VERSION 5.8 ;
BUSBITCHARS "[]" ;
DIVIDERCHAR "/" ;
CLEARANCEMEASURE EUCLIDEAN ;

SITE coresite
    SIZE 0.0450 BY 0.1440 ;
    CLASS CORE ;
    SYMMETRY X Y ;
END coresite

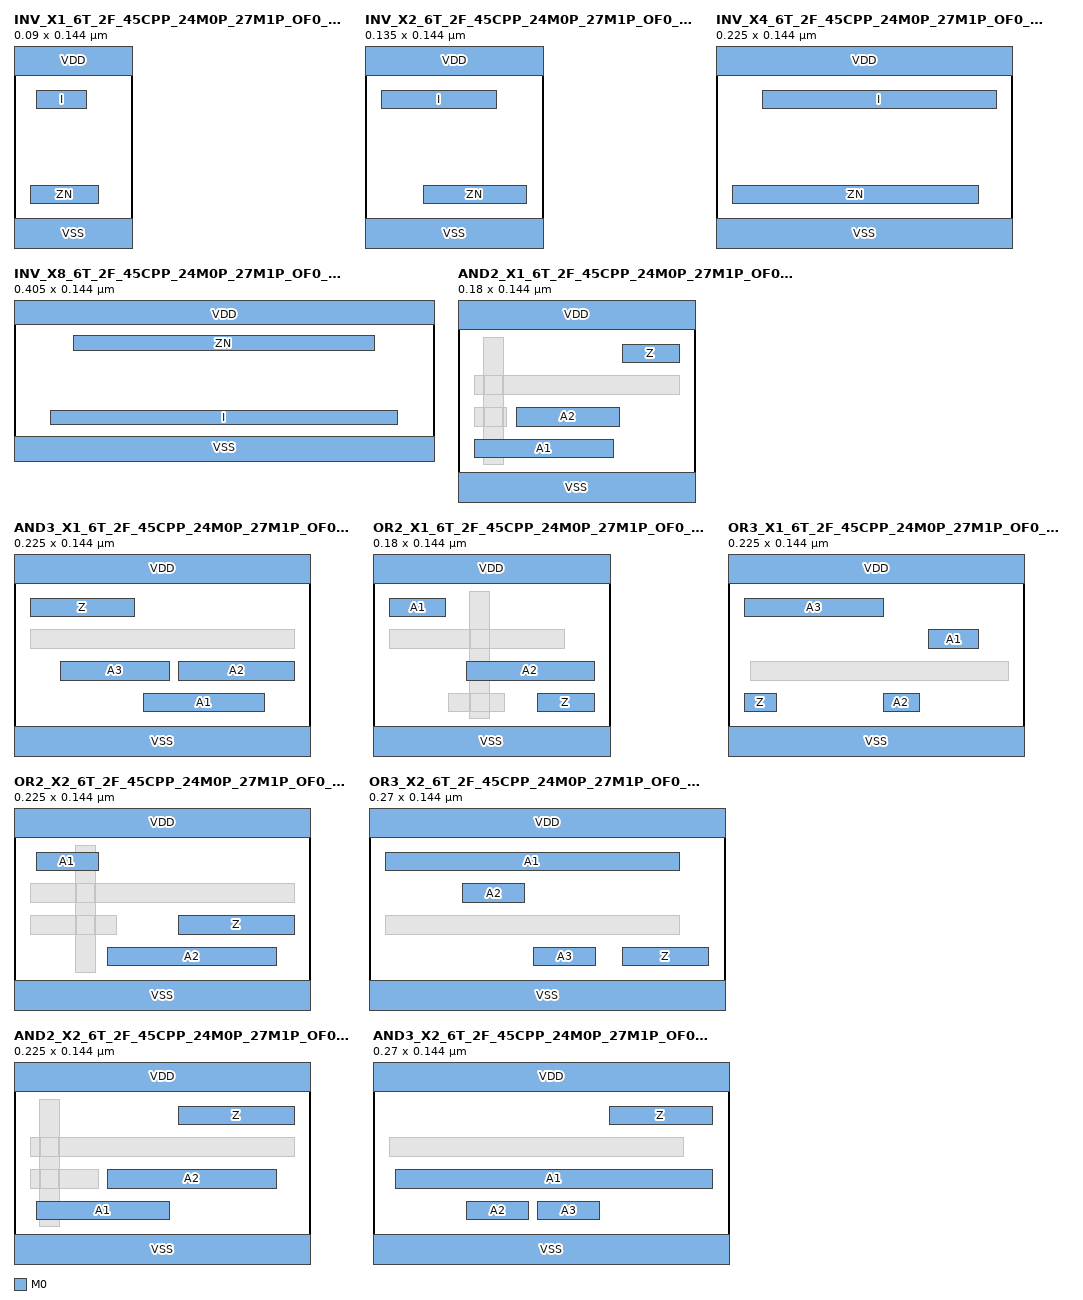
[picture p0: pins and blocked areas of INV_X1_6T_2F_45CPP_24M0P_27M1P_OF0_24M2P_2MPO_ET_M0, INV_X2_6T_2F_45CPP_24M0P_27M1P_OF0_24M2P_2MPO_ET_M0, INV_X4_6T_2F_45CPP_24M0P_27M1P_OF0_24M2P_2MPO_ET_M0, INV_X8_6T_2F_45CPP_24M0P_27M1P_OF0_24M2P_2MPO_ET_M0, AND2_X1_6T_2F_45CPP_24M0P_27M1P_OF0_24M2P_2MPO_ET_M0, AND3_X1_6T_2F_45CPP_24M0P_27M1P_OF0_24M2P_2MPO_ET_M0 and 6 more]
MACRO INV_X1_6T_2F_45CPP_24M0P_27M1P_OF0_24M2P_2MPO_ET_M0
  CLASS CORE ;
  ORIGIN 0 0 ;
  FOREIGN INV_X1_6T_2F_45CPP_24M0P_27M1P_OF0_24M2P_2MPO_ET_M0 0 0 ;
  SIZE 0.0900 BY 0.1440 ;
  SYMMETRY X Y ;
  SITE coresite ;
  PIN I
    DIRECTION INPUT ;
    USE SIGNAL ;
    PORT
      LAYER M0 ;
        RECT 0.0170 0.1150 0.0550 0.1010 ;
    END
  END I
  PIN ZN
    DIRECTION OUTPUT ;
    USE SIGNAL ;
    PORT
      LAYER M0 ;
        RECT 0.0125 0.0430 0.0640 0.0290 ;
    END
  END ZN
  PIN VDD
    DIRECTION INOUT ;
    USE POWER ;
    SHAPE ABUTMENT ;
    PORT
      LAYER M0 ;
        RECT 0.0000 0.1260 0.0900 0.1620 ;
    END
  END VDD
  PIN VSS
    DIRECTION INOUT ;
    USE GROUND ;
    SHAPE ABUTMENT ;
    PORT
      LAYER M0 ;
        RECT 0.0000 -0.0180 0.0900 0.0180 ;
    END
  END VSS
END INV_X1_6T_2F_45CPP_24M0P_27M1P_OF0_24M2P_2MPO_ET_M0

MACRO INV_X2_6T_2F_45CPP_24M0P_27M1P_OF0_24M2P_2MPO_ET_M0
  CLASS CORE ;
  ORIGIN 0 0 ;
  FOREIGN INV_X2_6T_2F_45CPP_24M0P_27M1P_OF0_24M2P_2MPO_ET_M0 0 0 ;
  SIZE 0.1350 BY 0.1440 ;
  SYMMETRY X Y ;
  SITE coresite ;
  PIN I
    DIRECTION INPUT ;
    USE SIGNAL ;
    PORT
      LAYER M0 ;
        RECT 0.0125 0.1150 0.1000 0.1010 ;
    END
  END I
  PIN ZN
    DIRECTION OUTPUT ;
    USE SIGNAL ;
    PORT
      LAYER M0 ;
        RECT 0.0440 0.0430 0.1225 0.0290 ;
    END
  END ZN
  PIN VDD
    DIRECTION INOUT ;
    USE POWER ;
    SHAPE ABUTMENT ;
    PORT
      LAYER M0 ;
        RECT 0.0000 0.1260 0.1350 0.1620 ;
    END
  END VDD
  PIN VSS
    DIRECTION INOUT ;
    USE GROUND ;
    SHAPE ABUTMENT ;
    PORT
      LAYER M0 ;
        RECT 0.0000 -0.0180 0.1350 0.0180 ;
    END
  END VSS
END INV_X2_6T_2F_45CPP_24M0P_27M1P_OF0_24M2P_2MPO_ET_M0

MACRO INV_X4_6T_2F_45CPP_24M0P_27M1P_OF0_24M2P_2MPO_ET_M0
  CLASS CORE ;
  ORIGIN 0 0 ;
  FOREIGN INV_X4_6T_2F_45CPP_24M0P_27M1P_OF0_24M2P_2MPO_ET_M0 0 0 ;
  SIZE 0.2250 BY 0.1440 ;
  SYMMETRY X Y ;
  SITE coresite ;
  PIN I
    DIRECTION INPUT ;
    USE SIGNAL ;
    PORT
      LAYER M0 ;
        RECT 0.0350 0.1150 0.2125 0.1010 ;
    END
  END I
  PIN ZN
    DIRECTION OUTPUT ;
    USE SIGNAL ;
    PORT
      LAYER M0 ;
        RECT 0.0125 0.0430 0.1990 0.0290 ;
    END
  END ZN
  PIN VDD
    DIRECTION INOUT ;
    USE POWER ;
    SHAPE ABUTMENT ;
    PORT
      LAYER M0 ;
        RECT 0.0000 0.1260 0.2250 0.1620 ;
    END
  END VDD
  PIN VSS
    DIRECTION INOUT ;
    USE GROUND ;
    SHAPE ABUTMENT ;
    PORT
      LAYER M0 ;
        RECT 0.0000 -0.0180 0.2250 0.0180 ;
    END
  END VSS
END INV_X4_6T_2F_45CPP_24M0P_27M1P_OF0_24M2P_2MPO_ET_M0

MACRO INV_X8_6T_2F_45CPP_24M0P_27M1P_OF0_24M2P_2MPO_ET_M0
  CLASS CORE ;
  ORIGIN 0 0 ;
  FOREIGN INV_X8_6T_2F_45CPP_24M0P_27M1P_OF0_24M2P_2MPO_ET_M0 0 0 ;
  SIZE 0.4050 BY 0.1440 ;
  SYMMETRY X Y ;
  SITE coresite ;
  PIN ZN
    DIRECTION OUTPUT ;
    USE SIGNAL ;
    PORT
      LAYER M0 ;
        RECT 0.0575 0.1150 0.3475 0.1010 ;
    END
  END ZN
  PIN I
    DIRECTION INPUT ;
    USE SIGNAL ;
    PORT
      LAYER M0 ;
        RECT 0.0350 0.0430 0.3700 0.0290 ;
    END
  END I
  PIN VDD
    DIRECTION INOUT ;
    USE POWER ;
    SHAPE ABUTMENT ;
    PORT
      LAYER M0 ;
        RECT 0.0000 0.1260 0.4050 0.1620 ;
    END
  END VDD
  PIN VSS
    DIRECTION INOUT ;
    USE GROUND ;
    SHAPE ABUTMENT ;
    PORT
      LAYER M0 ;
        RECT 0.0000 -0.0180 0.4050 0.0180 ;
    END
  END VSS
END INV_X8_6T_2F_45CPP_24M0P_27M1P_OF0_24M2P_2MPO_ET_M0

MACRO AND2_X1_6T_2F_45CPP_24M0P_27M1P_OF0_24M2P_2MPO_ET_M0
  CLASS CORE ;
  ORIGIN 0 0 ;
  FOREIGN AND2_X1_6T_2F_45CPP_24M0P_27M1P_OF0_24M2P_2MPO_ET_M0 0 0 ;
  SIZE 0.1800 BY 0.1440 ;
  SYMMETRY X Y ;
  SITE coresite ;
  PIN A2
    DIRECTION INPUT ;
    USE SIGNAL ;
    PORT
      LAYER M0 ;
        RECT 0.0440 0.0670 0.1225 0.0530 ;
    END
  END A2
  PIN A1
    DIRECTION INPUT ;
    USE SIGNAL ;
    PORT
      LAYER M0 ;
        RECT 0.0125 0.0430 0.1180 0.0290 ;
    END
  END A1
  PIN Z
    DIRECTION OUTPUT ;
    USE SIGNAL ;
    PORT
      LAYER M0 ;
        RECT 0.1250 0.1150 0.1675 0.1010 ;
    END
  END Z
  PIN VDD
    DIRECTION INOUT ;
    USE POWER ;
    SHAPE ABUTMENT ;
    PORT
      LAYER M0 ;
        RECT 0.0000 0.1260 0.1800 0.1620 ;
    END
  END VDD
  PIN VSS
    DIRECTION INOUT ;
    USE GROUND ;
    SHAPE ABUTMENT ;
    PORT
      LAYER M0 ;
        RECT 0.0000 -0.0180 0.1800 0.0180 ;
    END
  END VSS
  OBS
      LAYER M0 ;
        RECT 0.0125 0.0770 0.1675 0.0910 ;
        RECT 0.0125 0.0530 0.0370 0.0670 ;
      LAYER M1 ;
        RECT 0.0195 0.1200 0.0345 0.0240 ;
      LAYER V0 ;
        RECT 0.0200 0.0530 0.0340 0.0670 ;
        RECT 0.0200 0.0770 0.0340 0.0910 ;
  END
END AND2_X1_6T_2F_45CPP_24M0P_27M1P_OF0_24M2P_2MPO_ET_M0

MACRO AND3_X1_6T_2F_45CPP_24M0P_27M1P_OF0_24M2P_2MPO_ET_M0
  CLASS CORE ;
  ORIGIN 0 0 ;
  FOREIGN AND3_X1_6T_2F_45CPP_24M0P_27M1P_OF0_24M2P_2MPO_ET_M0 0 0 ;
  SIZE 0.2250 BY 0.1440 ;
  SYMMETRY X Y ;
  SITE coresite ;
  PIN A3
    DIRECTION INPUT ;
    USE SIGNAL ;
    PORT
      LAYER M0 ;
        RECT 0.0350 0.0670 0.1180 0.0530 ;
    END
  END A3
  PIN A2
    DIRECTION INPUT ;
    USE SIGNAL ;
    PORT
      LAYER M0 ;
        RECT 0.1250 0.0670 0.2125 0.0530 ;
    END
  END A2
  PIN Z
    DIRECTION OUTPUT ;
    USE SIGNAL ;
    PORT
      LAYER M0 ;
        RECT 0.0125 0.1150 0.0910 0.1010 ;
    END
  END Z
  PIN A1
    DIRECTION INPUT ;
    USE SIGNAL ;
    PORT
      LAYER M0 ;
        RECT 0.0980 0.0430 0.1900 0.0290 ;
    END
  END A1
  PIN VDD
    DIRECTION INOUT ;
    USE POWER ;
    SHAPE ABUTMENT ;
    PORT
      LAYER M0 ;
        RECT 0.0000 0.1260 0.2250 0.1620 ;
    END
  END VDD
  PIN VSS
    DIRECTION INOUT ;
    USE GROUND ;
    SHAPE ABUTMENT ;
    PORT
      LAYER M0 ;
        RECT 0.0000 -0.0180 0.2250 0.0180 ;
    END
  END VSS
  OBS
      LAYER M0 ;
        RECT 0.0125 0.0770 0.2125 0.0910 ;
  END
END AND3_X1_6T_2F_45CPP_24M0P_27M1P_OF0_24M2P_2MPO_ET_M0

MACRO OR2_X1_6T_2F_45CPP_24M0P_27M1P_OF0_24M2P_2MPO_ET_M0
  CLASS CORE ;
  ORIGIN 0 0 ;
  FOREIGN OR2_X1_6T_2F_45CPP_24M0P_27M1P_OF0_24M2P_2MPO_ET_M0 0 0 ;
  SIZE 0.1800 BY 0.1440 ;
  SYMMETRY X Y ;
  SITE coresite ;
  PIN A1
    DIRECTION INPUT ;
    USE SIGNAL ;
    PORT
      LAYER M0 ;
        RECT 0.0125 0.1150 0.0550 0.1010 ;
    END
  END A1
  PIN A2
    DIRECTION INPUT ;
    USE SIGNAL ;
    PORT
      LAYER M0 ;
        RECT 0.0710 0.0670 0.1675 0.0530 ;
    END
  END A2
  PIN Z
    DIRECTION OUTPUT ;
    USE SIGNAL ;
    PORT
      LAYER M0 ;
        RECT 0.1250 0.0430 0.1675 0.0290 ;
    END
  END Z
  PIN VDD
    DIRECTION INOUT ;
    USE POWER ;
    SHAPE ABUTMENT ;
    PORT
      LAYER M0 ;
        RECT 0.0000 0.1260 0.1800 0.1620 ;
    END
  END VDD
  PIN VSS
    DIRECTION INOUT ;
    USE GROUND ;
    SHAPE ABUTMENT ;
    PORT
      LAYER M0 ;
        RECT 0.0000 -0.0180 0.1800 0.0180 ;
    END
  END VSS
  OBS
      LAYER M0 ;
        RECT 0.0125 0.0770 0.1450 0.0910 ;
        RECT 0.0575 0.0290 0.1000 0.0430 ;
      LAYER M1 ;
        RECT 0.0735 0.1200 0.0885 0.0240 ;
      LAYER V0 ;
        RECT 0.0740 0.0290 0.0880 0.0430 ;
        RECT 0.0740 0.0770 0.0880 0.0910 ;
  END
END OR2_X1_6T_2F_45CPP_24M0P_27M1P_OF0_24M2P_2MPO_ET_M0

MACRO OR3_X1_6T_2F_45CPP_24M0P_27M1P_OF0_24M2P_2MPO_ET_M0
  CLASS CORE ;
  ORIGIN 0 0 ;
  FOREIGN OR3_X1_6T_2F_45CPP_24M0P_27M1P_OF0_24M2P_2MPO_ET_M0 0 0 ;
  SIZE 0.2250 BY 0.1440 ;
  SYMMETRY X Y ;
  SITE coresite ;
  PIN A3
    DIRECTION INPUT ;
    USE SIGNAL ;
    PORT
      LAYER M0 ;
        RECT 0.0125 0.1150 0.1180 0.1010 ;
    END
  END A3
  PIN A2
    DIRECTION INPUT ;
    USE SIGNAL ;
    PORT
      LAYER M0 ;
        RECT 0.1175 0.0430 0.1450 0.0290 ;
    END
  END A2
  PIN A1
    DIRECTION INPUT ;
    USE SIGNAL ;
    PORT
      LAYER M0 ;
        RECT 0.1520 0.0910 0.1900 0.0770 ;
    END
  END A1
  PIN Z
    DIRECTION OUTPUT ;
    USE SIGNAL ;
    PORT
      LAYER M0 ;
        RECT 0.0125 0.0430 0.0370 0.0290 ;
    END
  END Z
  PIN VDD
    DIRECTION INOUT ;
    USE POWER ;
    SHAPE ABUTMENT ;
    PORT
      LAYER M0 ;
        RECT 0.0000 0.1260 0.2250 0.1620 ;
    END
  END VDD
  PIN VSS
    DIRECTION INOUT ;
    USE GROUND ;
    SHAPE ABUTMENT ;
    PORT
      LAYER M0 ;
        RECT 0.0000 -0.0180 0.2250 0.0180 ;
    END
  END VSS
  OBS
      LAYER M0 ;
        RECT 0.0170 0.0530 0.2125 0.0670 ;
  END
END OR3_X1_6T_2F_45CPP_24M0P_27M1P_OF0_24M2P_2MPO_ET_M0

MACRO OR2_X2_6T_2F_45CPP_24M0P_27M1P_OF0_24M2P_2MPO_ET_M0
  CLASS CORE ;
  ORIGIN 0 0 ;
  FOREIGN OR2_X2_6T_2F_45CPP_24M0P_27M1P_OF0_24M2P_2MPO_ET_M0 0 0 ;
  SIZE 0.2250 BY 0.1440 ;
  SYMMETRY X Y ;
  SITE coresite ;
  PIN Z
    DIRECTION OUTPUT ;
    USE SIGNAL ;
    PORT
      LAYER M0 ;
        RECT 0.1250 0.0670 0.2125 0.0530 ;
    END
  END Z
  PIN A1
    DIRECTION INPUT ;
    USE SIGNAL ;
    PORT
      LAYER M0 ;
        RECT 0.0170 0.1150 0.0640 0.1010 ;
    END
  END A1
  PIN A2
    DIRECTION INPUT ;
    USE SIGNAL ;
    PORT
      LAYER M0 ;
        RECT 0.0710 0.0430 0.1990 0.0290 ;
    END
  END A2
  PIN VDD
    DIRECTION INOUT ;
    USE POWER ;
    SHAPE ABUTMENT ;
    PORT
      LAYER M0 ;
        RECT 0.0000 0.1260 0.2250 0.1620 ;
    END
  END VDD
  PIN VSS
    DIRECTION INOUT ;
    USE GROUND ;
    SHAPE ABUTMENT ;
    PORT
      LAYER M0 ;
        RECT 0.0000 -0.0180 0.2250 0.0180 ;
    END
  END VSS
  OBS
      LAYER M0 ;
        RECT 0.0125 0.0770 0.2125 0.0910 ;
        RECT 0.0125 0.0530 0.0775 0.0670 ;
      LAYER M1 ;
        RECT 0.0465 0.1200 0.0615 0.0240 ;
      LAYER V0 ;
        RECT 0.0470 0.0530 0.0610 0.0670 ;
        RECT 0.0470 0.0770 0.0610 0.0910 ;
  END
END OR2_X2_6T_2F_45CPP_24M0P_27M1P_OF0_24M2P_2MPO_ET_M0

MACRO OR3_X2_6T_2F_45CPP_24M0P_27M1P_OF0_24M2P_2MPO_ET_M0
  CLASS CORE ;
  ORIGIN 0 0 ;
  FOREIGN OR3_X2_6T_2F_45CPP_24M0P_27M1P_OF0_24M2P_2MPO_ET_M0 0 0 ;
  SIZE 0.2700 BY 0.1440 ;
  SYMMETRY X Y ;
  SITE coresite ;
  PIN A1
    DIRECTION INPUT ;
    USE SIGNAL ;
    PORT
      LAYER M0 ;
        RECT 0.0125 0.1150 0.2350 0.1010 ;
    END
  END A1
  PIN A2
    DIRECTION INPUT ;
    USE SIGNAL ;
    PORT
      LAYER M0 ;
        RECT 0.0710 0.0910 0.1180 0.0770 ;
    END
  END A2
  PIN A3
    DIRECTION INPUT ;
    USE SIGNAL ;
    PORT
      LAYER M0 ;
        RECT 0.1250 0.0430 0.1720 0.0290 ;
    END
  END A3
  PIN Z
    DIRECTION OUTPUT ;
    USE SIGNAL ;
    PORT
      LAYER M0 ;
        RECT 0.1925 0.0430 0.2575 0.0290 ;
    END
  END Z
  PIN VDD
    DIRECTION INOUT ;
    USE POWER ;
    SHAPE ABUTMENT ;
    PORT
      LAYER M0 ;
        RECT 0.0000 0.1260 0.2700 0.1620 ;
    END
  END VDD
  PIN VSS
    DIRECTION INOUT ;
    USE GROUND ;
    SHAPE ABUTMENT ;
    PORT
      LAYER M0 ;
        RECT 0.0000 -0.0180 0.2700 0.0180 ;
    END
  END VSS
  OBS
      LAYER M0 ;
        RECT 0.0125 0.0530 0.2350 0.0670 ;
  END
END OR3_X2_6T_2F_45CPP_24M0P_27M1P_OF0_24M2P_2MPO_ET_M0

MACRO AND2_X2_6T_2F_45CPP_24M0P_27M1P_OF0_24M2P_2MPO_ET_M0
  CLASS CORE ;
  ORIGIN 0 0 ;
  FOREIGN AND2_X2_6T_2F_45CPP_24M0P_27M1P_OF0_24M2P_2MPO_ET_M0 0 0 ;
  SIZE 0.2250 BY 0.1440 ;
  SYMMETRY X Y ;
  SITE coresite ;
  PIN A2
    DIRECTION INPUT ;
    USE SIGNAL ;
    PORT
      LAYER M0 ;
        RECT 0.0710 0.0670 0.1990 0.0530 ;
    END
  END A2
  PIN A1
    DIRECTION INPUT ;
    USE SIGNAL ;
    PORT
      LAYER M0 ;
        RECT 0.0170 0.0430 0.1180 0.0290 ;
    END
  END A1
  PIN Z
    DIRECTION OUTPUT ;
    USE SIGNAL ;
    PORT
      LAYER M0 ;
        RECT 0.1250 0.1150 0.2125 0.1010 ;
    END
  END Z
  PIN VDD
    DIRECTION INOUT ;
    USE POWER ;
    SHAPE ABUTMENT ;
    PORT
      LAYER M0 ;
        RECT 0.0000 0.1260 0.2250 0.1620 ;
    END
  END VDD
  PIN VSS
    DIRECTION INOUT ;
    USE GROUND ;
    SHAPE ABUTMENT ;
    PORT
      LAYER M0 ;
        RECT 0.0000 -0.0180 0.2250 0.0180 ;
    END
  END VSS
  OBS
      LAYER M0 ;
        RECT 0.0125 0.0770 0.2125 0.0910 ;
        RECT 0.0125 0.0530 0.0640 0.0670 ;
      LAYER M1 ;
        RECT 0.0195 0.1200 0.0345 0.0240 ;
      LAYER V0 ;
        RECT 0.0200 0.0530 0.0340 0.0670 ;
        RECT 0.0200 0.0770 0.0340 0.0910 ;
  END
END AND2_X2_6T_2F_45CPP_24M0P_27M1P_OF0_24M2P_2MPO_ET_M0

MACRO AND3_X2_6T_2F_45CPP_24M0P_27M1P_OF0_24M2P_2MPO_ET_M0
  CLASS CORE ;
  ORIGIN 0 0 ;
  FOREIGN AND3_X2_6T_2F_45CPP_24M0P_27M1P_OF0_24M2P_2MPO_ET_M0 0 0 ;
  SIZE 0.2700 BY 0.1440 ;
  SYMMETRY X Y ;
  SITE coresite ;
  PIN A1
    DIRECTION INPUT ;
    USE SIGNAL ;
    PORT
      LAYER M0 ;
        RECT 0.0170 0.0670 0.2575 0.0530 ;
    END
  END A1
  PIN A2
    DIRECTION INPUT ;
    USE SIGNAL ;
    PORT
      LAYER M0 ;
        RECT 0.0710 0.0430 0.1180 0.0290 ;
    END
  END A2
  PIN A3
    DIRECTION INPUT ;
    USE SIGNAL ;
    PORT
      LAYER M0 ;
        RECT 0.1250 0.0430 0.1720 0.0290 ;
    END
  END A3
  PIN Z
    DIRECTION OUTPUT ;
    USE SIGNAL ;
    PORT
      LAYER M0 ;
        RECT 0.1790 0.1150 0.2575 0.1010 ;
    END
  END Z
  PIN VDD
    DIRECTION INOUT ;
    USE POWER ;
    SHAPE ABUTMENT ;
    PORT
      LAYER M0 ;
        RECT 0.0000 0.1260 0.2700 0.1620 ;
    END
  END VDD
  PIN VSS
    DIRECTION INOUT ;
    USE GROUND ;
    SHAPE ABUTMENT ;
    PORT
      LAYER M0 ;
        RECT 0.0000 -0.0180 0.2700 0.0180 ;
    END
  END VSS
  OBS
      LAYER M0 ;
        RECT 0.0125 0.0770 0.2350 0.0910 ;
  END
END AND3_X2_6T_2F_45CPP_24M0P_27M1P_OF0_24M2P_2MPO_ET_M0

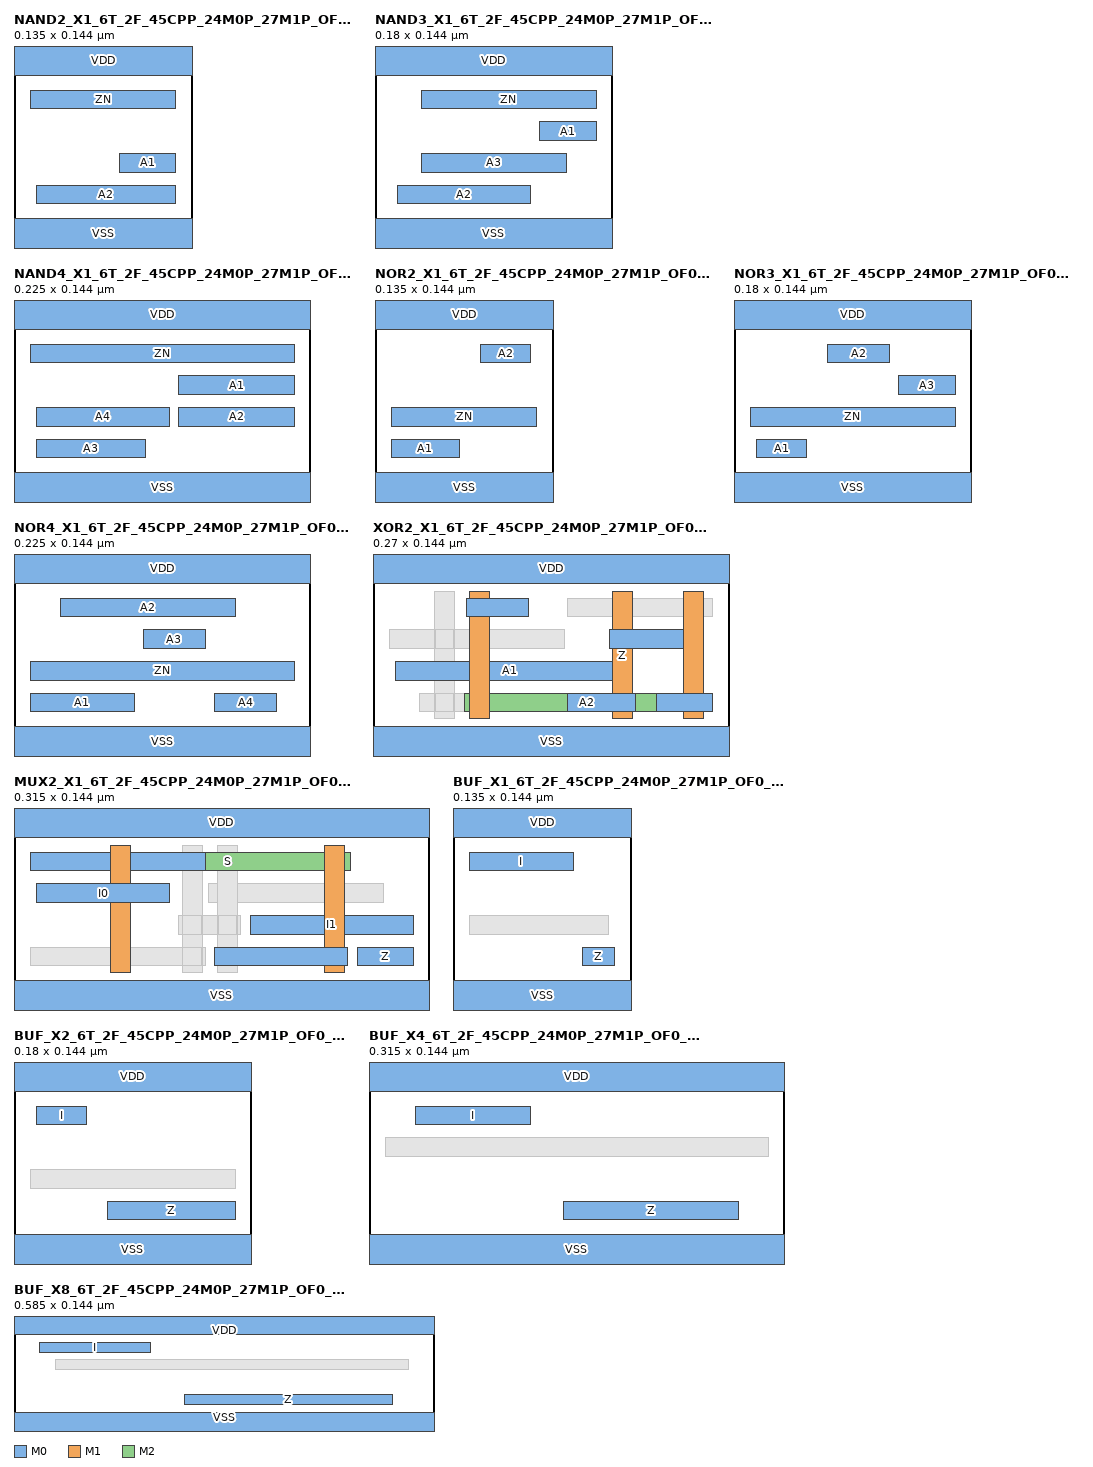
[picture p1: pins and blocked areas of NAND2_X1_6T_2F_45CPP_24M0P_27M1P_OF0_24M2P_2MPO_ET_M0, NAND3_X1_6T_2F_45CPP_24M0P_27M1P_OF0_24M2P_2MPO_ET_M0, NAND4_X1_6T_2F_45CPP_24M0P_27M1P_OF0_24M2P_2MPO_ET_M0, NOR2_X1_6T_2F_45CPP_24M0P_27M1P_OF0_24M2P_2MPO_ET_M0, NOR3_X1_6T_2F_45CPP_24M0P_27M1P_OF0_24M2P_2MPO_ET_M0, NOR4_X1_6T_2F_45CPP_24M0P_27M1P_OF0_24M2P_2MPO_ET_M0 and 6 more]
MACRO NAND2_X1_6T_2F_45CPP_24M0P_27M1P_OF0_24M2P_2MPO_ET_M0
  CLASS CORE ;
  ORIGIN 0 0 ;
  FOREIGN NAND2_X1_6T_2F_45CPP_24M0P_27M1P_OF0_24M2P_2MPO_ET_M0 0 0 ;
  SIZE 0.1350 BY 0.1440 ;
  SYMMETRY X Y ;
  SITE coresite ;
  PIN ZN
    DIRECTION OUTPUT ;
    USE SIGNAL ;
    PORT
      LAYER M0 ;
        RECT 0.0125 0.1150 0.1225 0.1010 ;
    END
  END ZN
  PIN A1
    DIRECTION INPUT ;
    USE SIGNAL ;
    PORT
      LAYER M0 ;
        RECT 0.0800 0.0670 0.1225 0.0530 ;
    END
  END A1
  PIN A2
    DIRECTION INPUT ;
    USE SIGNAL ;
    PORT
      LAYER M0 ;
        RECT 0.0170 0.0430 0.1225 0.0290 ;
    END
  END A2
  PIN VDD
    DIRECTION INOUT ;
    USE POWER ;
    SHAPE ABUTMENT ;
    PORT
      LAYER M0 ;
        RECT 0.0000 0.1260 0.1350 0.1620 ;
    END
  END VDD
  PIN VSS
    DIRECTION INOUT ;
    USE GROUND ;
    SHAPE ABUTMENT ;
    PORT
      LAYER M0 ;
        RECT 0.0000 -0.0180 0.1350 0.0180 ;
    END
  END VSS
END NAND2_X1_6T_2F_45CPP_24M0P_27M1P_OF0_24M2P_2MPO_ET_M0

MACRO NAND3_X1_6T_2F_45CPP_24M0P_27M1P_OF0_24M2P_2MPO_ET_M0
  CLASS CORE ;
  ORIGIN 0 0 ;
  FOREIGN NAND3_X1_6T_2F_45CPP_24M0P_27M1P_OF0_24M2P_2MPO_ET_M0 0 0 ;
  SIZE 0.1800 BY 0.1440 ;
  SYMMETRY X Y ;
  SITE coresite ;
  PIN ZN
    DIRECTION OUTPUT ;
    USE SIGNAL ;
    PORT
      LAYER M0 ;
        RECT 0.0350 0.1150 0.1675 0.1010 ;
    END
  END ZN
  PIN A3
    DIRECTION INPUT ;
    USE SIGNAL ;
    PORT
      LAYER M0 ;
        RECT 0.0350 0.0670 0.1450 0.0530 ;
    END
  END A3
  PIN A2
    DIRECTION INPUT ;
    USE SIGNAL ;
    PORT
      LAYER M0 ;
        RECT 0.0170 0.0430 0.1180 0.0290 ;
    END
  END A2
  PIN A1
    DIRECTION INPUT ;
    USE SIGNAL ;
    PORT
      LAYER M0 ;
        RECT 0.1250 0.0910 0.1675 0.0770 ;
    END
  END A1
  PIN VDD
    DIRECTION INOUT ;
    USE POWER ;
    SHAPE ABUTMENT ;
    PORT
      LAYER M0 ;
        RECT 0.0000 0.1260 0.1800 0.1620 ;
    END
  END VDD
  PIN VSS
    DIRECTION INOUT ;
    USE GROUND ;
    SHAPE ABUTMENT ;
    PORT
      LAYER M0 ;
        RECT 0.0000 -0.0180 0.1800 0.0180 ;
    END
  END VSS
END NAND3_X1_6T_2F_45CPP_24M0P_27M1P_OF0_24M2P_2MPO_ET_M0

MACRO NAND4_X1_6T_2F_45CPP_24M0P_27M1P_OF0_24M2P_2MPO_ET_M0
  CLASS CORE ;
  ORIGIN 0 0 ;
  FOREIGN NAND4_X1_6T_2F_45CPP_24M0P_27M1P_OF0_24M2P_2MPO_ET_M0 0 0 ;
  SIZE 0.2250 BY 0.1440 ;
  SYMMETRY X Y ;
  SITE coresite ;
  PIN ZN
    DIRECTION OUTPUT ;
    USE SIGNAL ;
    PORT
      LAYER M0 ;
        RECT 0.0125 0.1150 0.2125 0.1010 ;
    END
  END ZN
  PIN A4
    DIRECTION INPUT ;
    USE SIGNAL ;
    PORT
      LAYER M0 ;
        RECT 0.0170 0.0670 0.1180 0.0530 ;
    END
  END A4
  PIN A2
    DIRECTION INPUT ;
    USE SIGNAL ;
    PORT
      LAYER M0 ;
        RECT 0.1250 0.0670 0.2125 0.0530 ;
    END
  END A2
  PIN A3
    DIRECTION INPUT ;
    USE SIGNAL ;
    PORT
      LAYER M0 ;
        RECT 0.0170 0.0430 0.1000 0.0290 ;
    END
  END A3
  PIN A1
    DIRECTION INPUT ;
    USE SIGNAL ;
    PORT
      LAYER M0 ;
        RECT 0.1250 0.0910 0.2125 0.0770 ;
    END
  END A1
  PIN VDD
    DIRECTION INOUT ;
    USE POWER ;
    SHAPE ABUTMENT ;
    PORT
      LAYER M0 ;
        RECT 0.0000 0.1260 0.2250 0.1620 ;
    END
  END VDD
  PIN VSS
    DIRECTION INOUT ;
    USE GROUND ;
    SHAPE ABUTMENT ;
    PORT
      LAYER M0 ;
        RECT 0.0000 -0.0180 0.2250 0.0180 ;
    END
  END VSS
END NAND4_X1_6T_2F_45CPP_24M0P_27M1P_OF0_24M2P_2MPO_ET_M0

MACRO NOR2_X1_6T_2F_45CPP_24M0P_27M1P_OF0_24M2P_2MPO_ET_M0
  CLASS CORE ;
  ORIGIN 0 0 ;
  FOREIGN NOR2_X1_6T_2F_45CPP_24M0P_27M1P_OF0_24M2P_2MPO_ET_M0 0 0 ;
  SIZE 0.1350 BY 0.1440 ;
  SYMMETRY X Y ;
  SITE coresite ;
  PIN ZN
    DIRECTION OUTPUT ;
    USE SIGNAL ;
    PORT
      LAYER M0 ;
        RECT 0.0125 0.0670 0.1225 0.0530 ;
    END
  END ZN
  PIN A1
    DIRECTION INPUT ;
    USE SIGNAL ;
    PORT
      LAYER M0 ;
        RECT 0.0125 0.0430 0.0640 0.0290 ;
    END
  END A1
  PIN A2
    DIRECTION INPUT ;
    USE SIGNAL ;
    PORT
      LAYER M0 ;
        RECT 0.0800 0.1150 0.1180 0.1010 ;
    END
  END A2
  PIN VDD
    DIRECTION INOUT ;
    USE POWER ;
    SHAPE ABUTMENT ;
    PORT
      LAYER M0 ;
        RECT 0.0000 0.1260 0.1350 0.1620 ;
    END
  END VDD
  PIN VSS
    DIRECTION INOUT ;
    USE GROUND ;
    SHAPE ABUTMENT ;
    PORT
      LAYER M0 ;
        RECT 0.0000 -0.0180 0.1350 0.0180 ;
    END
  END VSS
END NOR2_X1_6T_2F_45CPP_24M0P_27M1P_OF0_24M2P_2MPO_ET_M0

MACRO NOR3_X1_6T_2F_45CPP_24M0P_27M1P_OF0_24M2P_2MPO_ET_M0
  CLASS CORE ;
  ORIGIN 0 0 ;
  FOREIGN NOR3_X1_6T_2F_45CPP_24M0P_27M1P_OF0_24M2P_2MPO_ET_M0 0 0 ;
  SIZE 0.1800 BY 0.1440 ;
  SYMMETRY X Y ;
  SITE coresite ;
  PIN ZN
    DIRECTION OUTPUT ;
    USE SIGNAL ;
    PORT
      LAYER M0 ;
        RECT 0.0125 0.0670 0.1675 0.0530 ;
    END
  END ZN
  PIN A1
    DIRECTION INPUT ;
    USE SIGNAL ;
    PORT
      LAYER M0 ;
        RECT 0.0170 0.0430 0.0550 0.0290 ;
    END
  END A1
  PIN A2
    DIRECTION INPUT ;
    USE SIGNAL ;
    PORT
      LAYER M0 ;
        RECT 0.0710 0.1150 0.1180 0.1010 ;
    END
  END A2
  PIN A3
    DIRECTION INPUT ;
    USE SIGNAL ;
    PORT
      LAYER M0 ;
        RECT 0.1250 0.0910 0.1675 0.0770 ;
    END
  END A3
  PIN VDD
    DIRECTION INOUT ;
    USE POWER ;
    SHAPE ABUTMENT ;
    PORT
      LAYER M0 ;
        RECT 0.0000 0.1260 0.1800 0.1620 ;
    END
  END VDD
  PIN VSS
    DIRECTION INOUT ;
    USE GROUND ;
    SHAPE ABUTMENT ;
    PORT
      LAYER M0 ;
        RECT 0.0000 -0.0180 0.1800 0.0180 ;
    END
  END VSS
END NOR3_X1_6T_2F_45CPP_24M0P_27M1P_OF0_24M2P_2MPO_ET_M0

MACRO NOR4_X1_6T_2F_45CPP_24M0P_27M1P_OF0_24M2P_2MPO_ET_M0
  CLASS CORE ;
  ORIGIN 0 0 ;
  FOREIGN NOR4_X1_6T_2F_45CPP_24M0P_27M1P_OF0_24M2P_2MPO_ET_M0 0 0 ;
  SIZE 0.2250 BY 0.1440 ;
  SYMMETRY X Y ;
  SITE coresite ;
  PIN A2
    DIRECTION INPUT ;
    USE SIGNAL ;
    PORT
      LAYER M0 ;
        RECT 0.0350 0.1150 0.1675 0.1010 ;
    END
  END A2
  PIN ZN
    DIRECTION OUTPUT ;
    USE SIGNAL ;
    PORT
      LAYER M0 ;
        RECT 0.0125 0.0670 0.2125 0.0530 ;
    END
  END ZN
  PIN A1
    DIRECTION INPUT ;
    USE SIGNAL ;
    PORT
      LAYER M0 ;
        RECT 0.0125 0.0430 0.0910 0.0290 ;
    END
  END A1
  PIN A3
    DIRECTION INPUT ;
    USE SIGNAL ;
    PORT
      LAYER M0 ;
        RECT 0.0980 0.0910 0.1450 0.0770 ;
    END
  END A3
  PIN A4
    DIRECTION INPUT ;
    USE SIGNAL ;
    PORT
      LAYER M0 ;
        RECT 0.1520 0.0430 0.1990 0.0290 ;
    END
  END A4
  PIN VDD
    DIRECTION INOUT ;
    USE POWER ;
    SHAPE ABUTMENT ;
    PORT
      LAYER M0 ;
        RECT 0.0000 0.1260 0.2250 0.1620 ;
    END
  END VDD
  PIN VSS
    DIRECTION INOUT ;
    USE GROUND ;
    SHAPE ABUTMENT ;
    PORT
      LAYER M0 ;
        RECT 0.0000 -0.0180 0.2250 0.0180 ;
    END
  END VSS
END NOR4_X1_6T_2F_45CPP_24M0P_27M1P_OF0_24M2P_2MPO_ET_M0

MACRO XOR2_X1_6T_2F_45CPP_24M0P_27M1P_OF0_24M2P_2MPO_ET_M0
  CLASS CORE ;
  ORIGIN 0 0 ;
  FOREIGN XOR2_X1_6T_2F_45CPP_24M0P_27M1P_OF0_24M2P_2MPO_ET_M0 0 0 ;
  SIZE 0.2700 BY 0.1440 ;
  SYMMETRY X Y ;
  SITE coresite ;
  PIN Z
    DIRECTION OUTPUT ;
    USE SIGNAL ;
    PORT
      LAYER M1 ;
        RECT 0.1815 0.1200 0.1965 0.0240 ;
      LAYER M0 ;
        RECT 0.1790 0.0910 0.2350 0.0770 ;
        RECT 0.1475 0.0430 0.1990 0.0290 ;
    END
  END Z
  PIN A2
    DIRECTION INPUT ;
    USE SIGNAL ;
    PORT
      LAYER M2 ;
        RECT 0.0690 0.0430 0.2550 0.0290 ;
      LAYER M1 ;
        RECT 0.0735 0.1200 0.0885 0.0240 ;
        RECT 0.2355 0.1200 0.2505 0.0240 ;
      LAYER M0 ;
        RECT 0.0710 0.1150 0.1180 0.1010 ;
        RECT 0.2150 0.0430 0.2575 0.0290 ;
    END
  END A2
  PIN A1
    DIRECTION INPUT ;
    USE SIGNAL ;
    PORT
      LAYER M0 ;
        RECT 0.0170 0.0670 0.1900 0.0530 ;
    END
  END A1
  PIN VDD
    DIRECTION INOUT ;
    USE POWER ;
    SHAPE ABUTMENT ;
    PORT
      LAYER M0 ;
        RECT 0.0000 0.1260 0.2700 0.1620 ;
    END
  END VDD
  PIN VSS
    DIRECTION INOUT ;
    USE GROUND ;
    SHAPE ABUTMENT ;
    PORT
      LAYER M0 ;
        RECT 0.0000 -0.0180 0.2700 0.0180 ;
    END
  END VSS
  OBS
      LAYER V1 ;
        RECT 0.2360 0.0290 0.2500 0.0430 ;
        RECT 0.0740 0.0290 0.0880 0.0430 ;
      LAYER M0 ;
        RECT 0.1475 0.1010 0.2575 0.1150 ;
        RECT 0.0125 0.0770 0.1450 0.0910 ;
        RECT 0.0350 0.0290 0.0775 0.0430 ;
      LAYER M1 ;
        RECT 0.0465 0.1200 0.0615 0.0240 ;
      LAYER V0 ;
        RECT 0.0470 0.0290 0.0610 0.0430 ;
        RECT 0.1820 0.0290 0.1960 0.0430 ;
        RECT 0.2360 0.0290 0.2500 0.0430 ;
        RECT 0.0470 0.0770 0.0610 0.0910 ;
        RECT 0.1820 0.0770 0.1960 0.0910 ;
        RECT 0.0740 0.1010 0.0880 0.1150 ;
  END
END XOR2_X1_6T_2F_45CPP_24M0P_27M1P_OF0_24M2P_2MPO_ET_M0

MACRO MUX2_X1_6T_2F_45CPP_24M0P_27M1P_OF0_24M2P_2MPO_ET_M0
  CLASS CORE ;
  ORIGIN 0 0 ;
  FOREIGN MUX2_X1_6T_2F_45CPP_24M0P_27M1P_OF0_24M2P_2MPO_ET_M0 0 0 ;
  SIZE 0.3150 BY 0.1440 ;
  SYMMETRY X Y ;
  SITE coresite ;
  PIN S
    DIRECTION INPUT ;
    USE SIGNAL ;
    PORT
      LAYER M2 ;
        RECT 0.0690 0.1150 0.2550 0.1010 ;
      LAYER M1 ;
        RECT 0.0735 0.1200 0.0885 0.0240 ;
        RECT 0.2355 0.1200 0.2505 0.0240 ;
      LAYER M0 ;
        RECT 0.0125 0.1150 0.1450 0.1010 ;
        RECT 0.1520 0.0430 0.2530 0.0290 ;
    END
  END S
  PIN I0
    DIRECTION INPUT ;
    USE SIGNAL ;
    PORT
      LAYER M0 ;
        RECT 0.0170 0.0910 0.1180 0.0770 ;
    END
  END I0
  PIN I1
    DIRECTION INPUT ;
    USE SIGNAL ;
    PORT
      LAYER M0 ;
        RECT 0.1790 0.0670 0.3025 0.0530 ;
    END
  END I1
  PIN Z
    DIRECTION OUTPUT ;
    USE SIGNAL ;
    PORT
      LAYER M0 ;
        RECT 0.2600 0.0430 0.3025 0.0290 ;
    END
  END Z
  PIN VDD
    DIRECTION INOUT ;
    USE POWER ;
    SHAPE ABUTMENT ;
    PORT
      LAYER M0 ;
        RECT 0.0000 0.1260 0.3150 0.1620 ;
    END
  END VDD
  PIN VSS
    DIRECTION INOUT ;
    USE GROUND ;
    SHAPE ABUTMENT ;
    PORT
      LAYER M0 ;
        RECT 0.0000 -0.0180 0.3150 0.0180 ;
    END
  END VSS
  OBS
      LAYER V1 ;
        RECT 0.2360 0.1010 0.2500 0.1150 ;
        RECT 0.0740 0.1010 0.0880 0.1150 ;
      LAYER M0 ;
        RECT 0.1520 0.1010 0.2125 0.1150 ;
        RECT 0.1475 0.0770 0.2800 0.0910 ;
        RECT 0.1250 0.0530 0.1720 0.0670 ;
        RECT 0.0125 0.0290 0.1450 0.0430 ;
      LAYER M1 ;
        RECT 0.1275 0.1200 0.1425 0.0240 ;
        RECT 0.1545 0.1200 0.1695 0.0240 ;
      LAYER V0 ;
        RECT 0.1280 0.0290 0.1420 0.0430 ;
        RECT 0.2360 0.0290 0.2500 0.0430 ;
        RECT 0.1280 0.0530 0.1420 0.0670 ;
        RECT 0.1550 0.0530 0.1690 0.0670 ;
        RECT 0.0740 0.1010 0.0880 0.1150 ;
        RECT 0.1550 0.1010 0.1690 0.1150 ;
  END
END MUX2_X1_6T_2F_45CPP_24M0P_27M1P_OF0_24M2P_2MPO_ET_M0

MACRO BUF_X1_6T_2F_45CPP_24M0P_27M1P_OF0_24M2P_2MPO_ET_M0
  CLASS CORE ;
  ORIGIN 0 0 ;
  FOREIGN BUF_X1_6T_2F_45CPP_24M0P_27M1P_OF0_24M2P_2MPO_ET_M0 0 0 ;
  SIZE 0.1350 BY 0.1440 ;
  SYMMETRY X Y ;
  SITE coresite ;
  PIN I
    DIRECTION INPUT ;
    USE SIGNAL ;
    PORT
      LAYER M0 ;
        RECT 0.0125 0.1150 0.0910 0.1010 ;
    END
  END I
  PIN Z
    DIRECTION OUTPUT ;
    USE SIGNAL ;
    PORT
      LAYER M0 ;
        RECT 0.0980 0.0430 0.1225 0.0290 ;
    END
  END Z
  PIN VDD
    DIRECTION INOUT ;
    USE POWER ;
    SHAPE ABUTMENT ;
    PORT
      LAYER M0 ;
        RECT 0.0000 0.1260 0.1350 0.1620 ;
    END
  END VDD
  PIN VSS
    DIRECTION INOUT ;
    USE GROUND ;
    SHAPE ABUTMENT ;
    PORT
      LAYER M0 ;
        RECT 0.0000 -0.0180 0.1350 0.0180 ;
    END
  END VSS
  OBS
      LAYER M0 ;
        RECT 0.0125 0.0530 0.1180 0.0670 ;
  END
END BUF_X1_6T_2F_45CPP_24M0P_27M1P_OF0_24M2P_2MPO_ET_M0

MACRO BUF_X2_6T_2F_45CPP_24M0P_27M1P_OF0_24M2P_2MPO_ET_M0
  CLASS CORE ;
  ORIGIN 0 0 ;
  FOREIGN BUF_X2_6T_2F_45CPP_24M0P_27M1P_OF0_24M2P_2MPO_ET_M0 0 0 ;
  SIZE 0.1800 BY 0.1440 ;
  SYMMETRY X Y ;
  SITE coresite ;
  PIN I
    DIRECTION INPUT ;
    USE SIGNAL ;
    PORT
      LAYER M0 ;
        RECT 0.0170 0.1150 0.0550 0.1010 ;
    END
  END I
  PIN Z
    DIRECTION OUTPUT ;
    USE SIGNAL ;
    PORT
      LAYER M0 ;
        RECT 0.0710 0.0430 0.1675 0.0290 ;
    END
  END Z
  PIN VDD
    DIRECTION INOUT ;
    USE POWER ;
    SHAPE ABUTMENT ;
    PORT
      LAYER M0 ;
        RECT 0.0000 0.1260 0.1800 0.1620 ;
    END
  END VDD
  PIN VSS
    DIRECTION INOUT ;
    USE GROUND ;
    SHAPE ABUTMENT ;
    PORT
      LAYER M0 ;
        RECT 0.0000 -0.0180 0.1800 0.0180 ;
    END
  END VSS
  OBS
      LAYER M0 ;
        RECT 0.0125 0.0530 0.1675 0.0670 ;
  END
END BUF_X2_6T_2F_45CPP_24M0P_27M1P_OF0_24M2P_2MPO_ET_M0

MACRO BUF_X4_6T_2F_45CPP_24M0P_27M1P_OF0_24M2P_2MPO_ET_M0
  CLASS CORE ;
  ORIGIN 0 0 ;
  FOREIGN BUF_X4_6T_2F_45CPP_24M0P_27M1P_OF0_24M2P_2MPO_ET_M0 0 0 ;
  SIZE 0.3150 BY 0.1440 ;
  SYMMETRY X Y ;
  SITE coresite ;
  PIN I
    DIRECTION INPUT ;
    USE SIGNAL ;
    PORT
      LAYER M0 ;
        RECT 0.0350 0.1150 0.1225 0.1010 ;
    END
  END I
  PIN Z
    DIRECTION OUTPUT ;
    USE SIGNAL ;
    PORT
      LAYER M0 ;
        RECT 0.1475 0.0430 0.2800 0.0290 ;
    END
  END Z
  PIN VDD
    DIRECTION INOUT ;
    USE POWER ;
    SHAPE ABUTMENT ;
    PORT
      LAYER M0 ;
        RECT 0.0000 0.1260 0.3150 0.1620 ;
    END
  END VDD
  PIN VSS
    DIRECTION INOUT ;
    USE GROUND ;
    SHAPE ABUTMENT ;
    PORT
      LAYER M0 ;
        RECT 0.0000 -0.0180 0.3150 0.0180 ;
    END
  END VSS
  OBS
      LAYER M0 ;
        RECT 0.0125 0.0770 0.3025 0.0910 ;
  END
END BUF_X4_6T_2F_45CPP_24M0P_27M1P_OF0_24M2P_2MPO_ET_M0

MACRO BUF_X8_6T_2F_45CPP_24M0P_27M1P_OF0_24M2P_2MPO_ET_M0
  CLASS CORE ;
  ORIGIN 0 0 ;
  FOREIGN BUF_X8_6T_2F_45CPP_24M0P_27M1P_OF0_24M2P_2MPO_ET_M0 0 0 ;
  SIZE 0.5850 BY 0.1440 ;
  SYMMETRY X Y ;
  SITE coresite ;
  PIN I
    DIRECTION INPUT ;
    USE SIGNAL ;
    PORT
      LAYER M0 ;
        RECT 0.0350 0.1150 0.1900 0.1010 ;
    END
  END I
  PIN Z
    DIRECTION OUTPUT ;
    USE SIGNAL ;
    PORT
      LAYER M0 ;
        RECT 0.2375 0.0430 0.5275 0.0290 ;
    END
  END Z
  PIN VDD
    DIRECTION INOUT ;
    USE POWER ;
    SHAPE ABUTMENT ;
    PORT
      LAYER M0 ;
        RECT 0.0000 0.1260 0.5850 0.1620 ;
    END
  END VDD
  PIN VSS
    DIRECTION INOUT ;
    USE GROUND ;
    SHAPE ABUTMENT ;
    PORT
      LAYER M0 ;
        RECT 0.0000 -0.0180 0.5850 0.0180 ;
    END
  END VSS
  OBS
      LAYER M0 ;
        RECT 0.0575 0.0770 0.5500 0.0910 ;
  END
END BUF_X8_6T_2F_45CPP_24M0P_27M1P_OF0_24M2P_2MPO_ET_M0

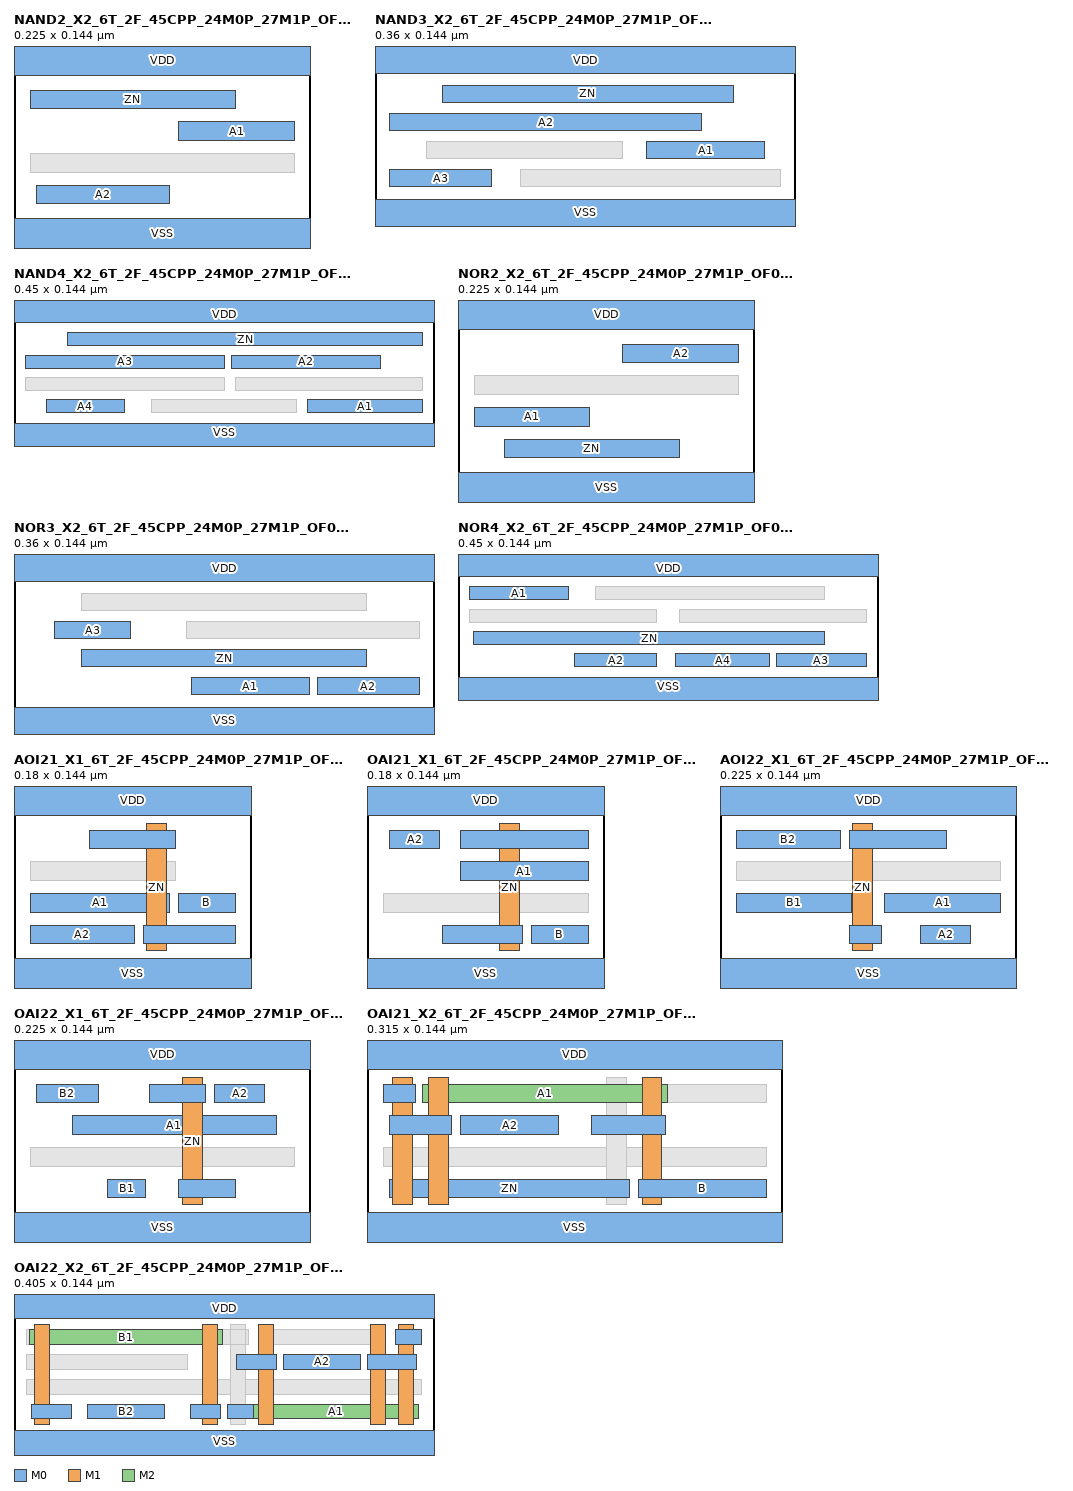
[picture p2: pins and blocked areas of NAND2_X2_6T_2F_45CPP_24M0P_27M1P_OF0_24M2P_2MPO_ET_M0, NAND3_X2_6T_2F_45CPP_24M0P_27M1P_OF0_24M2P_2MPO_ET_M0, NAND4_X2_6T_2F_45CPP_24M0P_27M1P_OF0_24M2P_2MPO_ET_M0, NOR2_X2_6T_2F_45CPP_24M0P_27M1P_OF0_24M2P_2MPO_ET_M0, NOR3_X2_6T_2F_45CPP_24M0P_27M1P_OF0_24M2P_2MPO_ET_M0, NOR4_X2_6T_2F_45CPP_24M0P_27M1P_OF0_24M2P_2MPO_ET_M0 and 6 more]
MACRO NAND2_X2_6T_2F_45CPP_24M0P_27M1P_OF0_24M2P_2MPO_ET_M0
  CLASS CORE ;
  ORIGIN 0 0 ;
  FOREIGN NAND2_X2_6T_2F_45CPP_24M0P_27M1P_OF0_24M2P_2MPO_ET_M0 0 0 ;
  SIZE 0.2250 BY 0.1440 ;
  SYMMETRY X Y ;
  SITE coresite ;
  PIN ZN
    DIRECTION OUTPUT ;
    USE SIGNAL ;
    PORT
      LAYER M0 ;
        RECT 0.0125 0.1150 0.1675 0.1010 ;
    END
  END ZN
  PIN A2
    DIRECTION INPUT ;
    USE SIGNAL ;
    PORT
      LAYER M0 ;
        RECT 0.0170 0.0430 0.1180 0.0290 ;
    END
  END A2
  PIN A1
    DIRECTION INPUT ;
    USE SIGNAL ;
    PORT
      LAYER M0 ;
        RECT 0.1250 0.0910 0.2125 0.0770 ;
    END
  END A1
  PIN VDD
    DIRECTION INOUT ;
    USE POWER ;
    SHAPE ABUTMENT ;
    PORT
      LAYER M0 ;
        RECT 0.0000 0.1260 0.2250 0.1620 ;
    END
  END VDD
  PIN VSS
    DIRECTION INOUT ;
    USE GROUND ;
    SHAPE ABUTMENT ;
    PORT
      LAYER M0 ;
        RECT 0.0000 -0.0180 0.2250 0.0180 ;
    END
  END VSS
  OBS
      LAYER M0 ;
        RECT 0.0125 0.0530 0.2125 0.0670 ;
  END
END NAND2_X2_6T_2F_45CPP_24M0P_27M1P_OF0_24M2P_2MPO_ET_M0

MACRO NAND3_X2_6T_2F_45CPP_24M0P_27M1P_OF0_24M2P_2MPO_ET_M0
  CLASS CORE ;
  ORIGIN 0 0 ;
  FOREIGN NAND3_X2_6T_2F_45CPP_24M0P_27M1P_OF0_24M2P_2MPO_ET_M0 0 0 ;
  SIZE 0.3600 BY 0.1440 ;
  SYMMETRY X Y ;
  SITE coresite ;
  PIN ZN
    DIRECTION OUTPUT ;
    USE SIGNAL ;
    PORT
      LAYER M0 ;
        RECT 0.0575 0.1150 0.3070 0.1010 ;
    END
  END ZN
  PIN A2
    DIRECTION INPUT ;
    USE SIGNAL ;
    PORT
      LAYER M0 ;
        RECT 0.0125 0.0910 0.2800 0.0770 ;
    END
  END A2
  PIN A1
    DIRECTION INPUT ;
    USE SIGNAL ;
    PORT
      LAYER M0 ;
        RECT 0.2330 0.0670 0.3340 0.0530 ;
    END
  END A1
  PIN A3
    DIRECTION INPUT ;
    USE SIGNAL ;
    PORT
      LAYER M0 ;
        RECT 0.0125 0.0430 0.1000 0.0290 ;
    END
  END A3
  PIN VDD
    DIRECTION INOUT ;
    USE POWER ;
    SHAPE ABUTMENT ;
    PORT
      LAYER M0 ;
        RECT 0.0000 0.1260 0.3600 0.1620 ;
    END
  END VDD
  PIN VSS
    DIRECTION INOUT ;
    USE GROUND ;
    SHAPE ABUTMENT ;
    PORT
      LAYER M0 ;
        RECT 0.0000 -0.0180 0.3600 0.0180 ;
    END
  END VSS
  OBS
      LAYER M0 ;
        RECT 0.0440 0.0530 0.2125 0.0670 ;
        RECT 0.1250 0.0290 0.3475 0.0430 ;
  END
END NAND3_X2_6T_2F_45CPP_24M0P_27M1P_OF0_24M2P_2MPO_ET_M0

MACRO NAND4_X2_6T_2F_45CPP_24M0P_27M1P_OF0_24M2P_2MPO_ET_M0
  CLASS CORE ;
  ORIGIN 0 0 ;
  FOREIGN NAND4_X2_6T_2F_45CPP_24M0P_27M1P_OF0_24M2P_2MPO_ET_M0 0 0 ;
  SIZE 0.4500 BY 0.1440 ;
  SYMMETRY X Y ;
  SITE coresite ;
  PIN ZN
    DIRECTION OUTPUT ;
    USE SIGNAL ;
    PORT
      LAYER M0 ;
        RECT 0.0575 0.1150 0.4375 0.1010 ;
    END
  END ZN
  PIN A3
    DIRECTION INPUT ;
    USE SIGNAL ;
    PORT
      LAYER M0 ;
        RECT 0.0125 0.0910 0.2260 0.0770 ;
    END
  END A3
  PIN A2
    DIRECTION INPUT ;
    USE SIGNAL ;
    PORT
      LAYER M0 ;
        RECT 0.2330 0.0910 0.3925 0.0770 ;
    END
  END A2
  PIN A4
    DIRECTION INPUT ;
    USE SIGNAL ;
    PORT
      LAYER M0 ;
        RECT 0.0350 0.0430 0.1180 0.0290 ;
    END
  END A4
  PIN A1
    DIRECTION INPUT ;
    USE SIGNAL ;
    PORT
      LAYER M0 ;
        RECT 0.3140 0.0430 0.4375 0.0290 ;
    END
  END A1
  PIN VDD
    DIRECTION INOUT ;
    USE POWER ;
    SHAPE ABUTMENT ;
    PORT
      LAYER M0 ;
        RECT 0.0000 0.1260 0.4500 0.1620 ;
    END
  END VDD
  PIN VSS
    DIRECTION INOUT ;
    USE GROUND ;
    SHAPE ABUTMENT ;
    PORT
      LAYER M0 ;
        RECT 0.0000 -0.0180 0.4500 0.0180 ;
    END
  END VSS
  OBS
      LAYER M0 ;
        RECT 0.0125 0.0530 0.2260 0.0670 ;
        RECT 0.2375 0.0530 0.4375 0.0670 ;
        RECT 0.1475 0.0290 0.3025 0.0430 ;
  END
END NAND4_X2_6T_2F_45CPP_24M0P_27M1P_OF0_24M2P_2MPO_ET_M0

MACRO NOR2_X2_6T_2F_45CPP_24M0P_27M1P_OF0_24M2P_2MPO_ET_M0
  CLASS CORE ;
  ORIGIN 0 0 ;
  FOREIGN NOR2_X2_6T_2F_45CPP_24M0P_27M1P_OF0_24M2P_2MPO_ET_M0 0 0 ;
  SIZE 0.2250 BY 0.1440 ;
  SYMMETRY X Y ;
  SITE coresite ;
  PIN A1
    DIRECTION INPUT ;
    USE SIGNAL ;
    PORT
      LAYER M0 ;
        RECT 0.0125 0.0670 0.1000 0.0530 ;
    END
  END A1
  PIN A2
    DIRECTION INPUT ;
    USE SIGNAL ;
    PORT
      LAYER M0 ;
        RECT 0.1250 0.1150 0.2125 0.1010 ;
    END
  END A2
  PIN ZN
    DIRECTION OUTPUT ;
    USE SIGNAL ;
    PORT
      LAYER M0 ;
        RECT 0.0350 0.0430 0.1675 0.0290 ;
    END
  END ZN
  PIN VDD
    DIRECTION INOUT ;
    USE POWER ;
    SHAPE ABUTMENT ;
    PORT
      LAYER M0 ;
        RECT 0.0000 0.1260 0.2250 0.1620 ;
    END
  END VDD
  PIN VSS
    DIRECTION INOUT ;
    USE GROUND ;
    SHAPE ABUTMENT ;
    PORT
      LAYER M0 ;
        RECT 0.0000 -0.0180 0.2250 0.0180 ;
    END
  END VSS
  OBS
      LAYER M0 ;
        RECT 0.0125 0.0770 0.2125 0.0910 ;
  END
END NOR2_X2_6T_2F_45CPP_24M0P_27M1P_OF0_24M2P_2MPO_ET_M0

MACRO NOR3_X2_6T_2F_45CPP_24M0P_27M1P_OF0_24M2P_2MPO_ET_M0
  CLASS CORE ;
  ORIGIN 0 0 ;
  FOREIGN NOR3_X2_6T_2F_45CPP_24M0P_27M1P_OF0_24M2P_2MPO_ET_M0 0 0 ;
  SIZE 0.3600 BY 0.1440 ;
  SYMMETRY X Y ;
  SITE coresite ;
  PIN ZN
    DIRECTION OUTPUT ;
    USE SIGNAL ;
    PORT
      LAYER M0 ;
        RECT 0.0575 0.0670 0.3025 0.0530 ;
    END
  END ZN
  PIN A3
    DIRECTION INPUT ;
    USE SIGNAL ;
    PORT
      LAYER M0 ;
        RECT 0.0350 0.0910 0.1000 0.0770 ;
    END
  END A3
  PIN A1
    DIRECTION INPUT ;
    USE SIGNAL ;
    PORT
      LAYER M0 ;
        RECT 0.1520 0.0430 0.2530 0.0290 ;
    END
  END A1
  PIN A2
    DIRECTION INPUT ;
    USE SIGNAL ;
    PORT
      LAYER M0 ;
        RECT 0.2600 0.0430 0.3475 0.0290 ;
    END
  END A2
  PIN VDD
    DIRECTION INOUT ;
    USE POWER ;
    SHAPE ABUTMENT ;
    PORT
      LAYER M0 ;
        RECT 0.0000 0.1260 0.3600 0.1620 ;
    END
  END VDD
  PIN VSS
    DIRECTION INOUT ;
    USE GROUND ;
    SHAPE ABUTMENT ;
    PORT
      LAYER M0 ;
        RECT 0.0000 -0.0180 0.3600 0.0180 ;
    END
  END VSS
  OBS
      LAYER M0 ;
        RECT 0.0575 0.1010 0.3025 0.1150 ;
        RECT 0.1475 0.0770 0.3475 0.0910 ;
  END
END NOR3_X2_6T_2F_45CPP_24M0P_27M1P_OF0_24M2P_2MPO_ET_M0

MACRO NOR4_X2_6T_2F_45CPP_24M0P_27M1P_OF0_24M2P_2MPO_ET_M0
  CLASS CORE ;
  ORIGIN 0 0 ;
  FOREIGN NOR4_X2_6T_2F_45CPP_24M0P_27M1P_OF0_24M2P_2MPO_ET_M0 0 0 ;
  SIZE 0.4500 BY 0.1440 ;
  SYMMETRY X Y ;
  SITE coresite ;
  PIN ZN
    DIRECTION OUTPUT ;
    USE SIGNAL ;
    PORT
      LAYER M0 ;
        RECT 0.0170 0.0670 0.3925 0.0530 ;
    END
  END ZN
  PIN A1
    DIRECTION INPUT ;
    USE SIGNAL ;
    PORT
      LAYER M0 ;
        RECT 0.0125 0.1150 0.1180 0.1010 ;
    END
  END A1
  PIN A2
    DIRECTION INPUT ;
    USE SIGNAL ;
    PORT
      LAYER M0 ;
        RECT 0.1250 0.0430 0.2125 0.0290 ;
    END
  END A2
  PIN A4
    DIRECTION INPUT ;
    USE SIGNAL ;
    PORT
      LAYER M0 ;
        RECT 0.2330 0.0430 0.3340 0.0290 ;
    END
  END A4
  PIN A3
    DIRECTION INPUT ;
    USE SIGNAL ;
    PORT
      LAYER M0 ;
        RECT 0.3410 0.0430 0.4375 0.0290 ;
    END
  END A3
  PIN VDD
    DIRECTION INOUT ;
    USE POWER ;
    SHAPE ABUTMENT ;
    PORT
      LAYER M0 ;
        RECT 0.0000 0.1260 0.4500 0.1620 ;
    END
  END VDD
  PIN VSS
    DIRECTION INOUT ;
    USE GROUND ;
    SHAPE ABUTMENT ;
    PORT
      LAYER M0 ;
        RECT 0.0000 -0.0180 0.4500 0.0180 ;
    END
  END VSS
  OBS
      LAYER M0 ;
        RECT 0.1475 0.1010 0.3925 0.1150 ;
        RECT 0.0125 0.0770 0.2125 0.0910 ;
        RECT 0.2375 0.0770 0.4375 0.0910 ;
  END
END NOR4_X2_6T_2F_45CPP_24M0P_27M1P_OF0_24M2P_2MPO_ET_M0

MACRO AOI21_X1_6T_2F_45CPP_24M0P_27M1P_OF0_24M2P_2MPO_ET_M0
  CLASS CORE ;
  ORIGIN 0 0 ;
  FOREIGN AOI21_X1_6T_2F_45CPP_24M0P_27M1P_OF0_24M2P_2MPO_ET_M0 0 0 ;
  SIZE 0.1800 BY 0.1440 ;
  SYMMETRY X Y ;
  SITE coresite ;
  PIN ZN
    DIRECTION OUTPUT ;
    USE SIGNAL ;
    PORT
      LAYER M1 ;
        RECT 0.1005 0.1200 0.1155 0.0240 ;
      LAYER M0 ;
        RECT 0.0575 0.1150 0.1225 0.1010 ;
        RECT 0.0980 0.0430 0.1675 0.0290 ;
    END
  END ZN
  PIN A1
    DIRECTION INPUT ;
    USE SIGNAL ;
    PORT
      LAYER M0 ;
        RECT 0.0125 0.0670 0.1180 0.0530 ;
    END
  END A1
  PIN B
    DIRECTION INPUT ;
    USE SIGNAL ;
    PORT
      LAYER M0 ;
        RECT 0.1250 0.0670 0.1675 0.0530 ;
    END
  END B
  PIN A2
    DIRECTION INPUT ;
    USE SIGNAL ;
    PORT
      LAYER M0 ;
        RECT 0.0125 0.0430 0.0910 0.0290 ;
    END
  END A2
  PIN VDD
    DIRECTION INOUT ;
    USE POWER ;
    SHAPE ABUTMENT ;
    PORT
      LAYER M0 ;
        RECT 0.0000 0.1260 0.1800 0.1620 ;
    END
  END VDD
  PIN VSS
    DIRECTION INOUT ;
    USE GROUND ;
    SHAPE ABUTMENT ;
    PORT
      LAYER M0 ;
        RECT 0.0000 -0.0180 0.1800 0.0180 ;
    END
  END VSS
  OBS
      LAYER M0 ;
        RECT 0.0125 0.0770 0.1225 0.0910 ;
      LAYER V0 ;
        RECT 0.1010 0.0290 0.1150 0.0430 ;
        RECT 0.1010 0.1010 0.1150 0.1150 ;
  END
END AOI21_X1_6T_2F_45CPP_24M0P_27M1P_OF0_24M2P_2MPO_ET_M0

MACRO OAI21_X1_6T_2F_45CPP_24M0P_27M1P_OF0_24M2P_2MPO_ET_M0
  CLASS CORE ;
  ORIGIN 0 0 ;
  FOREIGN OAI21_X1_6T_2F_45CPP_24M0P_27M1P_OF0_24M2P_2MPO_ET_M0 0 0 ;
  SIZE 0.1800 BY 0.1440 ;
  SYMMETRY X Y ;
  SITE coresite ;
  PIN ZN
    DIRECTION OUTPUT ;
    USE SIGNAL ;
    PORT
      LAYER M1 ;
        RECT 0.1005 0.1200 0.1155 0.0240 ;
      LAYER M0 ;
        RECT 0.0710 0.1150 0.1675 0.1010 ;
        RECT 0.0575 0.0430 0.1180 0.0290 ;
    END
  END ZN
  PIN A2
    DIRECTION INPUT ;
    USE SIGNAL ;
    PORT
      LAYER M0 ;
        RECT 0.0170 0.1150 0.0550 0.1010 ;
    END
  END A2
  PIN A1
    DIRECTION INPUT ;
    USE SIGNAL ;
    PORT
      LAYER M0 ;
        RECT 0.0710 0.0910 0.1675 0.0770 ;
    END
  END A1
  PIN B
    DIRECTION INPUT ;
    USE SIGNAL ;
    PORT
      LAYER M0 ;
        RECT 0.1250 0.0430 0.1675 0.0290 ;
    END
  END B
  PIN VDD
    DIRECTION INOUT ;
    USE POWER ;
    SHAPE ABUTMENT ;
    PORT
      LAYER M0 ;
        RECT 0.0000 0.1260 0.1800 0.1620 ;
    END
  END VDD
  PIN VSS
    DIRECTION INOUT ;
    USE GROUND ;
    SHAPE ABUTMENT ;
    PORT
      LAYER M0 ;
        RECT 0.0000 -0.0180 0.1800 0.0180 ;
    END
  END VSS
  OBS
      LAYER M0 ;
        RECT 0.0125 0.0530 0.1675 0.0670 ;
      LAYER V0 ;
        RECT 0.1010 0.0290 0.1150 0.0430 ;
        RECT 0.1010 0.1010 0.1150 0.1150 ;
  END
END OAI21_X1_6T_2F_45CPP_24M0P_27M1P_OF0_24M2P_2MPO_ET_M0

MACRO AOI22_X1_6T_2F_45CPP_24M0P_27M1P_OF0_24M2P_2MPO_ET_M0
  CLASS CORE ;
  ORIGIN 0 0 ;
  FOREIGN AOI22_X1_6T_2F_45CPP_24M0P_27M1P_OF0_24M2P_2MPO_ET_M0 0 0 ;
  SIZE 0.2250 BY 0.1440 ;
  SYMMETRY X Y ;
  SITE coresite ;
  PIN ZN
    DIRECTION OUTPUT ;
    USE SIGNAL ;
    PORT
      LAYER M1 ;
        RECT 0.1005 0.1200 0.1155 0.0240 ;
      LAYER M0 ;
        RECT 0.0980 0.1150 0.1720 0.1010 ;
        RECT 0.0980 0.0430 0.1225 0.0290 ;
    END
  END ZN
  PIN B1
    DIRECTION INPUT ;
    USE SIGNAL ;
    PORT
      LAYER M0 ;
        RECT 0.0125 0.0670 0.1000 0.0530 ;
    END
  END B1
  PIN A1
    DIRECTION INPUT ;
    USE SIGNAL ;
    PORT
      LAYER M0 ;
        RECT 0.1250 0.0670 0.2125 0.0530 ;
    END
  END A1
  PIN B2
    DIRECTION INPUT ;
    USE SIGNAL ;
    PORT
      LAYER M0 ;
        RECT 0.0125 0.1150 0.0910 0.1010 ;
    END
  END B2
  PIN A2
    DIRECTION INPUT ;
    USE SIGNAL ;
    PORT
      LAYER M0 ;
        RECT 0.1520 0.0430 0.1900 0.0290 ;
    END
  END A2
  PIN VDD
    DIRECTION INOUT ;
    USE POWER ;
    SHAPE ABUTMENT ;
    PORT
      LAYER M0 ;
        RECT 0.0000 0.1260 0.2250 0.1620 ;
    END
  END VDD
  PIN VSS
    DIRECTION INOUT ;
    USE GROUND ;
    SHAPE ABUTMENT ;
    PORT
      LAYER M0 ;
        RECT 0.0000 -0.0180 0.2250 0.0180 ;
    END
  END VSS
  OBS
      LAYER M0 ;
        RECT 0.0125 0.0770 0.2125 0.0910 ;
      LAYER V0 ;
        RECT 0.1010 0.0290 0.1150 0.0430 ;
        RECT 0.1010 0.1010 0.1150 0.1150 ;
  END
END AOI22_X1_6T_2F_45CPP_24M0P_27M1P_OF0_24M2P_2MPO_ET_M0

MACRO OAI22_X1_6T_2F_45CPP_24M0P_27M1P_OF0_24M2P_2MPO_ET_M0
  CLASS CORE ;
  ORIGIN 0 0 ;
  FOREIGN OAI22_X1_6T_2F_45CPP_24M0P_27M1P_OF0_24M2P_2MPO_ET_M0 0 0 ;
  SIZE 0.2250 BY 0.1440 ;
  SYMMETRY X Y ;
  SITE coresite ;
  PIN ZN
    DIRECTION OUTPUT ;
    USE SIGNAL ;
    PORT
      LAYER M1 ;
        RECT 0.1275 0.1200 0.1425 0.0240 ;
      LAYER M0 ;
        RECT 0.1025 0.1150 0.1450 0.1010 ;
        RECT 0.1250 0.0430 0.1675 0.0290 ;
    END
  END ZN
  PIN A2
    DIRECTION INPUT ;
    USE SIGNAL ;
    PORT
      LAYER M0 ;
        RECT 0.1520 0.1150 0.1900 0.1010 ;
    END
  END A2
  PIN A1
    DIRECTION INPUT ;
    USE SIGNAL ;
    PORT
      LAYER M0 ;
        RECT 0.0440 0.0910 0.1990 0.0770 ;
    END
  END A1
  PIN B2
    DIRECTION INPUT ;
    USE SIGNAL ;
    PORT
      LAYER M0 ;
        RECT 0.0170 0.1150 0.0640 0.1010 ;
    END
  END B2
  PIN B1
    DIRECTION INPUT ;
    USE SIGNAL ;
    PORT
      LAYER M0 ;
        RECT 0.0710 0.0430 0.1000 0.0290 ;
    END
  END B1
  PIN VDD
    DIRECTION INOUT ;
    USE POWER ;
    SHAPE ABUTMENT ;
    PORT
      LAYER M0 ;
        RECT 0.0000 0.1260 0.2250 0.1620 ;
    END
  END VDD
  PIN VSS
    DIRECTION INOUT ;
    USE GROUND ;
    SHAPE ABUTMENT ;
    PORT
      LAYER M0 ;
        RECT 0.0000 -0.0180 0.2250 0.0180 ;
    END
  END VSS
  OBS
      LAYER M0 ;
        RECT 0.0125 0.0530 0.2125 0.0670 ;
      LAYER V0 ;
        RECT 0.1280 0.0290 0.1420 0.0430 ;
        RECT 0.1280 0.1010 0.1420 0.1150 ;
  END
END OAI22_X1_6T_2F_45CPP_24M0P_27M1P_OF0_24M2P_2MPO_ET_M0

MACRO OAI21_X2_6T_2F_45CPP_24M0P_27M1P_OF0_24M2P_2MPO_ET_M0
  CLASS CORE ;
  ORIGIN 0 0 ;
  FOREIGN OAI21_X2_6T_2F_45CPP_24M0P_27M1P_OF0_24M2P_2MPO_ET_M0 0 0 ;
  SIZE 0.3150 BY 0.1440 ;
  SYMMETRY X Y ;
  SITE coresite ;
  PIN ZN
    DIRECTION OUTPUT ;
    USE SIGNAL ;
    PORT
      LAYER M1 ;
        RECT 0.0195 0.1200 0.0345 0.0240 ;
      LAYER M0 ;
        RECT 0.0125 0.1150 0.0370 0.1010 ;
        RECT 0.0170 0.0430 0.1990 0.0290 ;
    END
  END ZN
  PIN A1
    DIRECTION INPUT ;
    USE SIGNAL ;
    PORT
      LAYER M2 ;
        RECT 0.0420 0.1150 0.2280 0.1010 ;
      LAYER M1 ;
        RECT 0.0465 0.1200 0.0615 0.0240 ;
        RECT 0.2085 0.1200 0.2235 0.0240 ;
      LAYER M0 ;
        RECT 0.0170 0.0910 0.0640 0.0770 ;
        RECT 0.1700 0.0910 0.2260 0.0770 ;
    END
  END A1
  PIN A2
    DIRECTION INPUT ;
    USE SIGNAL ;
    PORT
      LAYER M0 ;
        RECT 0.0710 0.0910 0.1450 0.0770 ;
    END
  END A2
  PIN B
    DIRECTION INPUT ;
    USE SIGNAL ;
    PORT
      LAYER M0 ;
        RECT 0.2060 0.0430 0.3025 0.0290 ;
    END
  END B
  PIN VDD
    DIRECTION INOUT ;
    USE POWER ;
    SHAPE ABUTMENT ;
    PORT
      LAYER M0 ;
        RECT 0.0000 0.1260 0.3150 0.1620 ;
    END
  END VDD
  PIN VSS
    DIRECTION INOUT ;
    USE GROUND ;
    SHAPE ABUTMENT ;
    PORT
      LAYER M0 ;
        RECT 0.0000 -0.0180 0.3150 0.0180 ;
    END
  END VSS
  OBS
      LAYER V1 ;
        RECT 0.2090 0.1010 0.2230 0.1150 ;
        RECT 0.0470 0.1010 0.0610 0.1150 ;
      LAYER M0 ;
        RECT 0.0575 0.1010 0.1675 0.1150 ;
        RECT 0.1790 0.1010 0.3025 0.1150 ;
        RECT 0.0125 0.0530 0.3025 0.0670 ;
      LAYER M1 ;
        RECT 0.1815 0.1200 0.1965 0.0240 ;
      LAYER V0 ;
        RECT 0.0200 0.0290 0.0340 0.0430 ;
        RECT 0.1820 0.0290 0.1960 0.0430 ;
        RECT 0.0470 0.0770 0.0610 0.0910 ;
        RECT 0.2090 0.0770 0.2230 0.0910 ;
        RECT 0.0200 0.1010 0.0340 0.1150 ;
        RECT 0.1820 0.1010 0.1960 0.1150 ;
  END
END OAI21_X2_6T_2F_45CPP_24M0P_27M1P_OF0_24M2P_2MPO_ET_M0

MACRO OAI22_X2_6T_2F_45CPP_24M0P_27M1P_OF0_24M2P_2MPO_ET_M0
  CLASS CORE ;
  ORIGIN 0 0 ;
  FOREIGN OAI22_X2_6T_2F_45CPP_24M0P_27M1P_OF0_24M2P_2MPO_ET_M0 0 0 ;
  SIZE 0.4050 BY 0.1440 ;
  SYMMETRY X Y ;
  SITE coresite ;
  PIN ZN
    DIRECTION OUTPUT ;
    USE SIGNAL ;
    PORT
      LAYER M1 ;
        RECT 0.3705 0.1200 0.3855 0.0240 ;
      LAYER M0 ;
        RECT 0.3680 0.1150 0.3925 0.1010 ;
        RECT 0.2060 0.0430 0.3880 0.0290 ;
    END
  END ZN
  PIN B1
    DIRECTION INPUT ;
    USE SIGNAL ;
    PORT
      LAYER M2 ;
        RECT 0.0150 0.1150 0.2010 0.1010 ;
      LAYER M1 ;
        RECT 0.0195 0.1200 0.0345 0.0240 ;
        RECT 0.1815 0.1200 0.1965 0.0240 ;
      LAYER M0 ;
        RECT 0.0170 0.0430 0.0550 0.0290 ;
        RECT 0.1700 0.0430 0.1990 0.0290 ;
    END
  END B1
  PIN A1
    DIRECTION INPUT ;
    USE SIGNAL ;
    PORT
      LAYER M2 ;
        RECT 0.2310 0.0430 0.3900 0.0290 ;
      LAYER M1 ;
        RECT 0.2355 0.1200 0.2505 0.0240 ;
        RECT 0.3435 0.1200 0.3585 0.0240 ;
      LAYER M0 ;
        RECT 0.2150 0.0910 0.2530 0.0770 ;
        RECT 0.3410 0.0910 0.3880 0.0770 ;
    END
  END A1
  PIN A2
    DIRECTION INPUT ;
    USE SIGNAL ;
    PORT
      LAYER M0 ;
        RECT 0.2600 0.0910 0.3340 0.0770 ;
    END
  END A2
  PIN B2
    DIRECTION INPUT ;
    USE SIGNAL ;
    PORT
      LAYER M0 ;
        RECT 0.0710 0.0430 0.1450 0.0290 ;
    END
  END B2
  PIN VDD
    DIRECTION INOUT ;
    USE POWER ;
    SHAPE ABUTMENT ;
    PORT
      LAYER M0 ;
        RECT 0.0000 0.1260 0.4050 0.1620 ;
    END
  END VDD
  PIN VSS
    DIRECTION INOUT ;
    USE GROUND ;
    SHAPE ABUTMENT ;
    PORT
      LAYER M0 ;
        RECT 0.0000 -0.0180 0.4050 0.0180 ;
    END
  END VSS
  OBS
      LAYER V1 ;
        RECT 0.3440 0.0290 0.3580 0.0430 ;
        RECT 0.2360 0.0290 0.2500 0.0430 ;
        RECT 0.1820 0.1010 0.1960 0.1150 ;
        RECT 0.0200 0.1010 0.0340 0.1150 ;
      LAYER M0 ;
        RECT 0.0125 0.1010 0.2260 0.1150 ;
        RECT 0.2375 0.1010 0.3475 0.1150 ;
        RECT 0.0125 0.0770 0.1675 0.0910 ;
        RECT 0.0125 0.0530 0.3925 0.0670 ;
      LAYER M1 ;
        RECT 0.2085 0.1200 0.2235 0.0240 ;
      LAYER V0 ;
        RECT 0.0200 0.0290 0.0340 0.0430 ;
        RECT 0.1820 0.0290 0.1960 0.0430 ;
        RECT 0.2090 0.0290 0.2230 0.0430 ;
        RECT 0.3710 0.0290 0.3850 0.0430 ;
        RECT 0.2360 0.0770 0.2500 0.0910 ;
        RECT 0.3440 0.0770 0.3580 0.0910 ;
        RECT 0.2090 0.1010 0.2230 0.1150 ;
        RECT 0.3710 0.1010 0.3850 0.1150 ;
  END
END OAI22_X2_6T_2F_45CPP_24M0P_27M1P_OF0_24M2P_2MPO_ET_M0

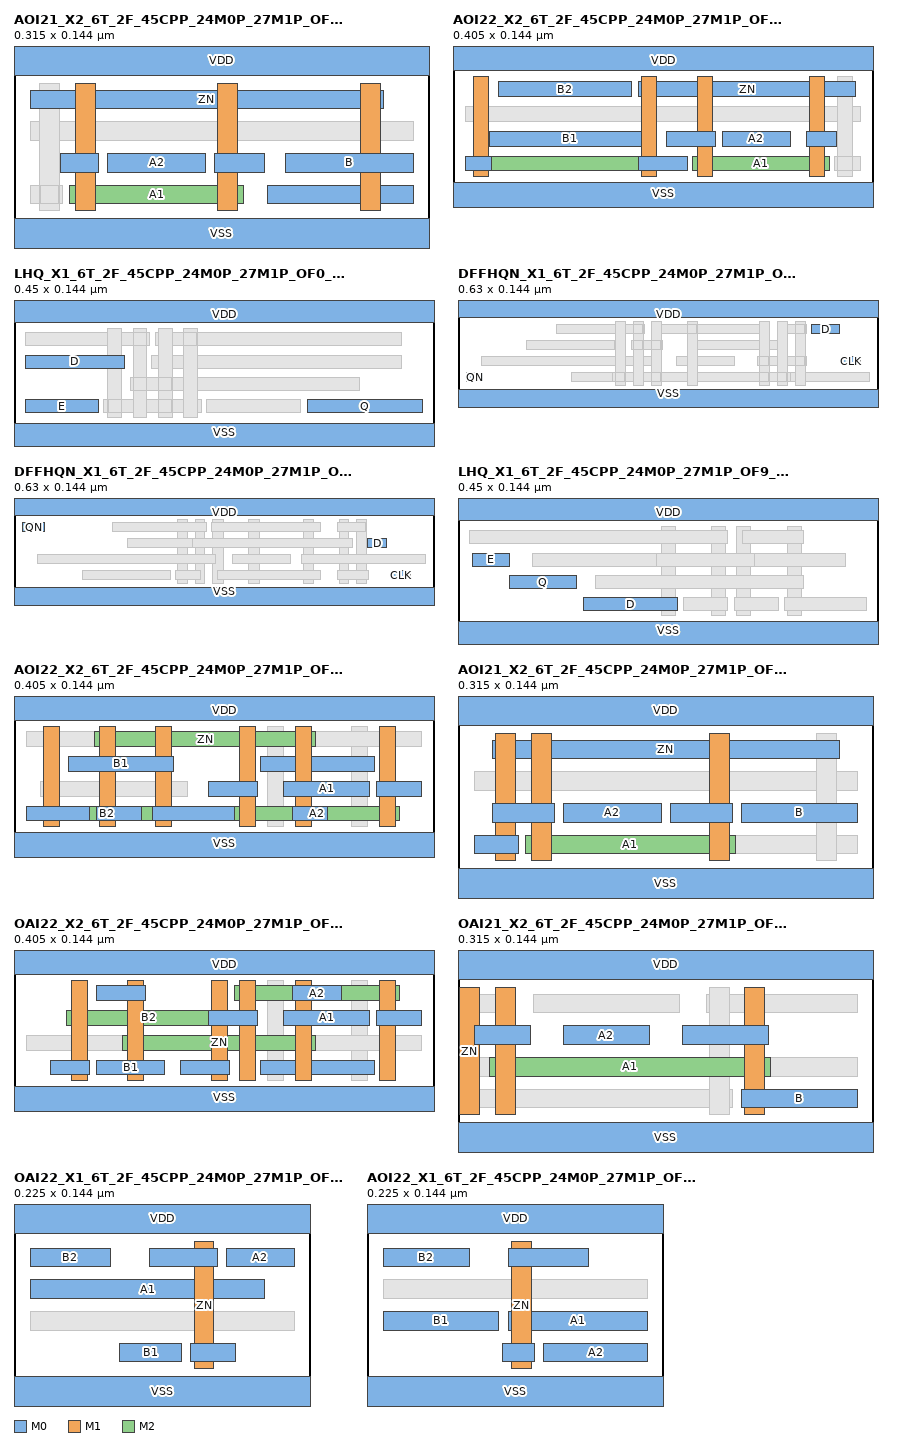
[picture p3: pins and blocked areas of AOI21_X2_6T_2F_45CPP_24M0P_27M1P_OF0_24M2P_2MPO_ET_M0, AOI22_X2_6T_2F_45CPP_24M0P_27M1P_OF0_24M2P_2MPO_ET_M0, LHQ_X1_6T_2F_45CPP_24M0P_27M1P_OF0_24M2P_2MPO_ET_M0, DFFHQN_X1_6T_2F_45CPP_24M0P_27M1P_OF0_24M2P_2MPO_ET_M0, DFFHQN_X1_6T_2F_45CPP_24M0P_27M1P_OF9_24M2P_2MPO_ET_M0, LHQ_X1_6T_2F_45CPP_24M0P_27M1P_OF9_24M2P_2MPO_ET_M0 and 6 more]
MACRO AOI21_X2_6T_2F_45CPP_24M0P_27M1P_OF0_24M2P_2MPO_ET_M0
  CLASS CORE ;
  ORIGIN 0 0 ;
  FOREIGN AOI21_X2_6T_2F_45CPP_24M0P_27M1P_OF0_24M2P_2MPO_ET_M0 0 0 ;
  SIZE 0.3150 BY 0.1440 ;
  SYMMETRY X Y ;
  SITE coresite ;
  PIN ZN
    DIRECTION OUTPUT ;
    USE SIGNAL ;
    PORT
      LAYER M1 ;
        RECT 0.2625 0.1200 0.2775 0.0240 ;
      LAYER M0 ;
        RECT 0.0125 0.1150 0.2800 0.1010 ;
        RECT 0.1925 0.0430 0.3025 0.0290 ;
    END
  END ZN
  PIN A1
    DIRECTION INPUT ;
    USE SIGNAL ;
    PORT
      LAYER M2 ;
        RECT 0.0420 0.0430 0.1740 0.0290 ;
      LAYER M1 ;
        RECT 0.0465 0.1200 0.0615 0.0240 ;
        RECT 0.1545 0.1200 0.1695 0.0240 ;
      LAYER M0 ;
        RECT 0.0350 0.0670 0.0640 0.0530 ;
        RECT 0.1520 0.0670 0.1900 0.0530 ;
    END
  END A1
  PIN A2
    DIRECTION INPUT ;
    USE SIGNAL ;
    PORT
      LAYER M0 ;
        RECT 0.0710 0.0670 0.1450 0.0530 ;
    END
  END A2
  PIN B
    DIRECTION INPUT ;
    USE SIGNAL ;
    PORT
      LAYER M0 ;
        RECT 0.2060 0.0670 0.3025 0.0530 ;
    END
  END B
  PIN VDD
    DIRECTION INOUT ;
    USE POWER ;
    SHAPE ABUTMENT ;
    PORT
      LAYER M0 ;
        RECT 0.0000 0.1260 0.3150 0.1620 ;
    END
  END VDD
  PIN VSS
    DIRECTION INOUT ;
    USE GROUND ;
    SHAPE ABUTMENT ;
    PORT
      LAYER M0 ;
        RECT 0.0000 -0.0180 0.3150 0.0180 ;
    END
  END VSS
  OBS
      LAYER V1 ;
        RECT 0.1550 0.0290 0.1690 0.0430 ;
        RECT 0.0470 0.0290 0.0610 0.0430 ;
      LAYER M0 ;
        RECT 0.0125 0.0770 0.3025 0.0910 ;
        RECT 0.0125 0.0290 0.0370 0.0430 ;
        RECT 0.0575 0.0290 0.1675 0.0430 ;
      LAYER M1 ;
        RECT 0.0195 0.1200 0.0345 0.0240 ;
      LAYER V0 ;
        RECT 0.0200 0.0290 0.0340 0.0430 ;
        RECT 0.2630 0.0290 0.2770 0.0430 ;
        RECT 0.0470 0.0530 0.0610 0.0670 ;
        RECT 0.1550 0.0530 0.1690 0.0670 ;
        RECT 0.0200 0.1010 0.0340 0.1150 ;
        RECT 0.2630 0.1010 0.2770 0.1150 ;
  END
END AOI21_X2_6T_2F_45CPP_24M0P_27M1P_OF0_24M2P_2MPO_ET_M0

MACRO AOI22_X2_6T_2F_45CPP_24M0P_27M1P_OF0_24M2P_2MPO_ET_M0
  CLASS CORE ;
  ORIGIN 0 0 ;
  FOREIGN AOI22_X2_6T_2F_45CPP_24M0P_27M1P_OF0_24M2P_2MPO_ET_M0 0 0 ;
  SIZE 0.4050 BY 0.1440 ;
  SYMMETRY X Y ;
  SITE coresite ;
  PIN ZN
    DIRECTION OUTPUT ;
    USE SIGNAL ;
    PORT
      LAYER M2 ;
        RECT 0.0150 0.0430 0.2010 0.0290 ;
      LAYER M1 ;
        RECT 0.0195 0.1200 0.0345 0.0240 ;
        RECT 0.1815 0.1200 0.1965 0.0240 ;
      LAYER M0 ;
        RECT 0.0125 0.0430 0.0370 0.0290 ;
        RECT 0.1790 0.1150 0.3880 0.1010 ;
        RECT 0.1790 0.0430 0.2260 0.0290 ;
    END
  END ZN
  PIN A1
    DIRECTION INPUT ;
    USE SIGNAL ;
    PORT
      LAYER M2 ;
        RECT 0.2310 0.0430 0.3630 0.0290 ;
      LAYER M1 ;
        RECT 0.2355 0.1200 0.2505 0.0240 ;
        RECT 0.3435 0.1200 0.3585 0.0240 ;
      LAYER M0 ;
        RECT 0.2060 0.0670 0.2530 0.0530 ;
        RECT 0.3410 0.0670 0.3700 0.0530 ;
    END
  END A1
  PIN B2
    DIRECTION INPUT ;
    USE SIGNAL ;
    PORT
      LAYER M0 ;
        RECT 0.0440 0.1150 0.1720 0.1010 ;
    END
  END B2
  PIN B1
    DIRECTION INPUT ;
    USE SIGNAL ;
    PORT
      LAYER M0 ;
        RECT 0.0350 0.0670 0.1900 0.0530 ;
    END
  END B1
  PIN A2
    DIRECTION INPUT ;
    USE SIGNAL ;
    PORT
      LAYER M0 ;
        RECT 0.2600 0.0670 0.3250 0.0530 ;
    END
  END A2
  PIN VDD
    DIRECTION INOUT ;
    USE POWER ;
    SHAPE ABUTMENT ;
    PORT
      LAYER M0 ;
        RECT 0.0000 0.1260 0.4050 0.1620 ;
    END
  END VDD
  PIN VSS
    DIRECTION INOUT ;
    USE GROUND ;
    SHAPE ABUTMENT ;
    PORT
      LAYER M0 ;
        RECT 0.0000 -0.0180 0.4050 0.0180 ;
    END
  END VSS
  OBS
      LAYER V1 ;
        RECT 0.3440 0.0290 0.3580 0.0430 ;
        RECT 0.2360 0.0290 0.2500 0.0430 ;
        RECT 0.1820 0.0290 0.1960 0.0430 ;
        RECT 0.0200 0.0290 0.0340 0.0430 ;
      LAYER M0 ;
        RECT 0.0125 0.0770 0.3925 0.0910 ;
        RECT 0.0575 0.0290 0.1675 0.0430 ;
        RECT 0.2375 0.0290 0.3475 0.0430 ;
        RECT 0.3680 0.0290 0.3925 0.0430 ;
      LAYER M1 ;
        RECT 0.3705 0.1200 0.3855 0.0240 ;
      LAYER V0 ;
        RECT 0.0200 0.0290 0.0340 0.0430 ;
        RECT 0.1820 0.0290 0.1960 0.0430 ;
        RECT 0.3710 0.0290 0.3850 0.0430 ;
        RECT 0.2360 0.0530 0.2500 0.0670 ;
        RECT 0.3440 0.0530 0.3580 0.0670 ;
        RECT 0.1820 0.1010 0.1960 0.1150 ;
        RECT 0.3710 0.1010 0.3850 0.1150 ;
  END
END AOI22_X2_6T_2F_45CPP_24M0P_27M1P_OF0_24M2P_2MPO_ET_M0

MACRO LHQ_X1_6T_2F_45CPP_24M0P_27M1P_OF0_24M2P_2MPO_ET_M0
  CLASS CORE ;
  ORIGIN 0 0 ;
  FOREIGN LHQ_X1_6T_2F_45CPP_24M0P_27M1P_OF0_24M2P_2MPO_ET_M0 0 0 ;
  SIZE 0.4500 BY 0.1440 ;
  SYMMETRY X Y ;
  SITE coresite ;
  PIN D
    DIRECTION INPUT ;
    USE SIGNAL ;
    PORT
      LAYER M0 ;
        RECT 0.0125 0.0910 0.1180 0.0770 ;
    END
  END D
  PIN E
    DIRECTION INPUT ;
    USE SIGNAL ;
    PORT
      LAYER M0 ;
        RECT 0.0125 0.0430 0.0910 0.0290 ;
    END
  END E
  PIN Q
    DIRECTION OUTPUT ;
    USE SIGNAL ;
    PORT
      LAYER M0 ;
        RECT 0.3140 0.0430 0.4375 0.0290 ;
    END
  END Q
  PIN VDD
    DIRECTION INOUT ;
    USE POWER ;
    SHAPE ABUTMENT ;
    PORT
      LAYER M0 ;
        RECT 0.0000 0.1260 0.4500 0.1620 ;
    END
  END VDD
  PIN VSS
    DIRECTION INOUT ;
    USE GROUND ;
    SHAPE ABUTMENT ;
    PORT
      LAYER M0 ;
        RECT 0.0000 -0.0180 0.4500 0.0180 ;
    END
  END VSS
  OBS
      LAYER M0 ;
        RECT 0.0125 0.1010 0.1450 0.1150 ;
        RECT 0.1520 0.1010 0.4150 0.1150 ;
        RECT 0.1475 0.0770 0.4150 0.0910 ;
        RECT 0.1250 0.0530 0.3700 0.0670 ;
        RECT 0.0980 0.0290 0.1450 0.0430 ;
        RECT 0.1520 0.0290 0.1900 0.0430 ;
        RECT 0.2060 0.0290 0.3070 0.0430 ;
      LAYER M2 ;
        RECT 0.0960 0.0290 0.2010 0.0430 ;
      LAYER V1 ;
        RECT 0.1820 0.0290 0.1960 0.0430 ;
        RECT 0.1010 0.0290 0.1150 0.0430 ;
      LAYER M1 ;
        RECT 0.1005 0.1200 0.1155 0.0240 ;
        RECT 0.1275 0.1200 0.1425 0.0240 ;
        RECT 0.1545 0.1200 0.1695 0.0240 ;
        RECT 0.1815 0.1200 0.1965 0.0240 ;
      LAYER V0 ;
        RECT 0.1010 0.0290 0.1150 0.0430 ;
        RECT 0.1550 0.0290 0.1690 0.0430 ;
        RECT 0.1280 0.0530 0.1420 0.0670 ;
        RECT 0.1550 0.0530 0.1690 0.0670 ;
        RECT 0.1280 0.1010 0.1420 0.1150 ;
        RECT 0.1820 0.1010 0.1960 0.1150 ;
  END
END LHQ_X1_6T_2F_45CPP_24M0P_27M1P_OF0_24M2P_2MPO_ET_M0

MACRO DFFHQN_X1_6T_2F_45CPP_24M0P_27M1P_OF0_24M2P_2MPO_ET_M0
  CLASS CORE ;
  ORIGIN 0 0 ;
  FOREIGN DFFHQN_X1_6T_2F_45CPP_24M0P_27M1P_OF0_24M2P_2MPO_ET_M0 0 0 ;
  SIZE 0.6300 BY 0.1440 ;
  SYMMETRY X Y ;
  SITE coresite ;
  PIN D
    DIRECTION INPUT ;
    USE SIGNAL ;
    PORT
      LAYER M0 ;
        RECT 0.5300 0.1150 0.5725 0.1010 ;
    END
  END D
  PIN CLK
    DIRECTION INPUT ;
    USE SIGNAL ;
    PORT
      LAYER M0 ;
        RECT 0.5750 0.0670 0.6040 0.0530 ;
    END
  END CLK
  PIN QN
    DIRECTION OUTPUT ;
    USE SIGNAL ;
    PORT
      LAYER M0 ;
        RECT 0.0125 0.0430 0.0370 0.0290 ;
    END
  END QN
  PIN VDD
    DIRECTION INOUT ;
    USE POWER ;
    SHAPE ABUTMENT ;
    PORT
      LAYER M0 ;
        RECT 0.0000 0.1260 0.6300 0.1620 ;
    END
  END VDD
  PIN VSS
    DIRECTION INOUT ;
    USE GROUND ;
    SHAPE ABUTMENT ;
    PORT
      LAYER M0 ;
        RECT 0.0000 -0.0180 0.6300 0.0180 ;
    END
  END VSS
  OBS
      LAYER M0 ;
        RECT 0.1475 0.1010 0.2800 0.1150 ;
        RECT 0.3050 0.1010 0.4600 0.1150 ;
        RECT 0.4850 0.1010 0.5230 0.1150 ;
        RECT 0.1025 0.0770 0.2350 0.0910 ;
        RECT 0.2600 0.0770 0.3070 0.0910 ;
        RECT 0.3500 0.0770 0.4825 0.0910 ;
        RECT 0.0350 0.0530 0.3025 0.0670 ;
        RECT 0.3275 0.0530 0.4150 0.0670 ;
        RECT 0.4490 0.0530 0.5230 0.0670 ;
        RECT 0.1700 0.0290 0.2800 0.0430 ;
        RECT 0.2870 0.0290 0.4690 0.0430 ;
        RECT 0.4760 0.0290 0.6175 0.0430 ;
      LAYER M2 ;
        RECT 0.2310 0.0290 0.4980 0.0430 ;
      LAYER V1 ;
        RECT 0.4790 0.0290 0.4930 0.0430 ;
        RECT 0.3440 0.0290 0.3580 0.0430 ;
        RECT 0.2360 0.0290 0.2500 0.0430 ;
      LAYER M1 ;
        RECT 0.2355 0.1200 0.2505 0.0240 ;
        RECT 0.2625 0.1200 0.2775 0.0240 ;
        RECT 0.2895 0.1200 0.3045 0.0240 ;
        RECT 0.3435 0.1200 0.3585 0.0240 ;
        RECT 0.4515 0.1200 0.4665 0.0240 ;
        RECT 0.4785 0.1200 0.4935 0.0240 ;
        RECT 0.5055 0.1200 0.5205 0.0240 ;
      LAYER V0 ;
        RECT 0.2360 0.0290 0.2500 0.0430 ;
        RECT 0.2900 0.0290 0.3040 0.0430 ;
        RECT 0.4520 0.0290 0.4660 0.0430 ;
        RECT 0.4790 0.0290 0.4930 0.0430 ;
        RECT 0.4520 0.0530 0.4660 0.0670 ;
        RECT 0.5060 0.0530 0.5200 0.0670 ;
        RECT 0.2630 0.0770 0.2770 0.0910 ;
        RECT 0.2900 0.0770 0.3040 0.0910 ;
        RECT 0.2630 0.1010 0.2770 0.1150 ;
        RECT 0.3440 0.1010 0.3580 0.1150 ;
        RECT 0.5060 0.1010 0.5200 0.1150 ;
  END
END DFFHQN_X1_6T_2F_45CPP_24M0P_27M1P_OF0_24M2P_2MPO_ET_M0


MACRO DFFHQN_X1_6T_2F_45CPP_24M0P_27M1P_OF9_24M2P_2MPO_ET_M0
  CLASS CORE ;
  ORIGIN 0 0 ;
  FOREIGN DFFHQN_X1_6T_2F_45CPP_24M0P_27M1P_OF9_24M2P_2MPO_ET_M0 0 0 ;
  SIZE 0.6300 BY 0.1440 ;
  SYMMETRY X Y ;
  SITE coresite ;
  PIN D
    DIRECTION INPUT ;
    USE SIGNAL ;
    PORT
      LAYER M0 ;
        RECT 0.5300 0.0910 0.5590 0.0770 ;
    END
  END D
  PIN QN
    DIRECTION OUTPUT ;
    USE SIGNAL ;
    PORT
      LAYER M0 ;
        RECT 0.0125 0.1150 0.0460 0.1010 ;
    END
  END QN
  PIN CLK
    DIRECTION INPUT ;
    USE SIGNAL ;
    PORT
      LAYER M0 ;
        RECT 0.5660 0.0430 0.5950 0.0290 ;
    END
  END CLK
  PIN VDD
    DIRECTION INOUT ;
    USE POWER ;
    SHAPE ABUTMENT ;
    PORT
      LAYER M0 ;
        RECT 0.0000 0.1260 0.6300 0.1620 ;
    END
  END VDD
  PIN VSS
    DIRECTION INOUT ;
    USE GROUND ;
    SHAPE ABUTMENT ;
    PORT
      LAYER M0 ;
        RECT 0.0000 -0.0180 0.6300 0.0180 ;
    END
  END VSS
  OBS
      LAYER V0 ;
        RECT 0.2450 0.0290 0.2590 0.0430 ;
        RECT 0.3530 0.0290 0.3670 0.0430 ;
        RECT 0.5150 0.0290 0.5290 0.0430 ;
        RECT 0.4340 0.0530 0.4480 0.0670 ;
        RECT 0.5150 0.0530 0.5290 0.0670 ;
        RECT 0.2450 0.0770 0.2590 0.0910 ;
        RECT 0.2990 0.0770 0.3130 0.0910 ;
        RECT 0.2720 0.1010 0.2860 0.1150 ;
        RECT 0.2990 0.1010 0.3130 0.1150 ;
        RECT 0.4340 0.1010 0.4480 0.1150 ;
        RECT 0.4880 0.1010 0.5020 0.1150 ;
      LAYER M1 ;
        RECT 0.2445 0.1200 0.2595 0.0240 ;
        RECT 0.2715 0.1200 0.2865 0.0240 ;
        RECT 0.2985 0.1200 0.3135 0.0240 ;
        RECT 0.3525 0.1200 0.3675 0.0240 ;
        RECT 0.4335 0.1200 0.4485 0.0240 ;
        RECT 0.4875 0.1200 0.5025 0.0240 ;
        RECT 0.5145 0.1200 0.5295 0.0240 ;
      LAYER V1 ;
        RECT 0.4880 0.0770 0.5020 0.0910 ;
        RECT 0.3530 0.0770 0.3670 0.0910 ;
        RECT 0.2720 0.0770 0.2860 0.0910 ;
      LAYER M0 ;
        RECT 0.1475 0.1010 0.2890 0.1150 ;
        RECT 0.2960 0.1010 0.4600 0.1150 ;
        RECT 0.4850 0.1010 0.5275 0.1150 ;
        RECT 0.1700 0.0770 0.3160 0.0910 ;
        RECT 0.3500 0.0770 0.4825 0.0910 ;
        RECT 0.0350 0.0530 0.3025 0.0670 ;
        RECT 0.3275 0.0530 0.4150 0.0670 ;
        RECT 0.4310 0.0530 0.6175 0.0670 ;
        RECT 0.1025 0.0290 0.2350 0.0430 ;
        RECT 0.2420 0.0290 0.2800 0.0430 ;
        RECT 0.3050 0.0290 0.4600 0.0430 ;
        RECT 0.4850 0.0290 0.5320 0.0430 ;
      LAYER M2 ;
        RECT 0.2670 0.0770 0.5070 0.0910 ;
  END
END DFFHQN_X1_6T_2F_45CPP_24M0P_27M1P_OF9_24M2P_2MPO_ET_M0

MACRO LHQ_X1_6T_2F_45CPP_24M0P_27M1P_OF9_24M2P_2MPO_ET_M0
  CLASS CORE ;
  ORIGIN 0 0 ;
  FOREIGN LHQ_X1_6T_2F_45CPP_24M0P_27M1P_OF9_24M2P_2MPO_ET_M0 0 0 ;
  SIZE 0.4500 BY 0.1440 ;
  SYMMETRY X Y ;
  SITE coresite ;
  PIN E
    DIRECTION INPUT ;
    USE SIGNAL ;
    PORT
      LAYER M0 ;
        RECT 0.0155 0.0910 0.0550 0.0770 ;
    END
  END E
  PIN Q
    DIRECTION OUTPUT ;
    USE SIGNAL ;
    PORT
      LAYER M0 ;
        RECT 0.0555 0.0670 0.1270 0.0530 ;
    END
  END Q
  PIN D
    DIRECTION INPUT ;
    USE SIGNAL ;
    PORT
      LAYER M0 ;
        RECT 0.1340 0.0430 0.2350 0.0290 ;
    END
  END D
  PIN VDD
    DIRECTION INOUT ;
    USE POWER ;
    SHAPE ABUTMENT ;
    PORT
      LAYER M0 ;
        RECT 0.0000 0.1260 0.4500 0.1620 ;
    END
  END VDD
  PIN VSS
    DIRECTION INOUT ;
    USE GROUND ;
    SHAPE ABUTMENT ;
    PORT
      LAYER M0 ;
        RECT 0.0000 -0.0180 0.4500 0.0180 ;
    END
  END VSS
  OBS
      LAYER V0 ;
        RECT 0.2720 0.0290 0.2860 0.0430 ;
        RECT 0.2990 0.0290 0.3130 0.0430 ;
        RECT 0.2720 0.0530 0.2860 0.0670 ;
        RECT 0.3530 0.0530 0.3670 0.0670 ;
        RECT 0.2180 0.1010 0.2320 0.1150 ;
        RECT 0.3530 0.1010 0.3670 0.1150 ;
      LAYER M1 ;
        RECT 0.2175 0.1200 0.2325 0.0240 ;
        RECT 0.2715 0.1200 0.2865 0.0240 ;
        RECT 0.2985 0.1200 0.3135 0.0240 ;
        RECT 0.3525 0.1200 0.3675 0.0240 ;
      LAYER V1 ;
        RECT 0.2990 0.0770 0.3130 0.0910 ;
        RECT 0.2180 0.0770 0.2320 0.0910 ;
      LAYER M0 ;
        RECT 0.0125 0.1010 0.2890 0.1150 ;
        RECT 0.3050 0.1010 0.3700 0.1150 ;
        RECT 0.0800 0.0770 0.4150 0.0910 ;
        RECT 0.1475 0.0530 0.3700 0.0670 ;
        RECT 0.2420 0.0290 0.2890 0.0430 ;
        RECT 0.2960 0.0290 0.3430 0.0430 ;
        RECT 0.3500 0.0290 0.4375 0.0430 ;
      LAYER M2 ;
        RECT 0.2130 0.0770 0.3180 0.0910 ;
  END
END LHQ_X1_6T_2F_45CPP_24M0P_27M1P_OF9_24M2P_2MPO_ET_M0

MACRO AOI22_X2_6T_2F_45CPP_24M0P_27M1P_OF9_24M2P_2MPO_ET_M0
  CLASS CORE ;
  ORIGIN 0 0 ;
  FOREIGN AOI22_X2_6T_2F_45CPP_24M0P_27M1P_OF9_24M2P_2MPO_ET_M0 0 0 ;
  SIZE 0.4050 BY 0.1440 ;
  SYMMETRY X Y ;
  SITE coresite ;
  PIN ZN
    DIRECTION OUTPUT ;
    USE SIGNAL ;
    PORT
      LAYER M2 ;
        RECT 0.0780 0.1150 0.2910 0.1010 ;
      LAYER M1 ;
        RECT 0.0825 0.1200 0.0975 0.0240 ;
        RECT 0.2715 0.1200 0.2865 0.0240 ;
      LAYER M0 ;
        RECT 0.0800 0.0430 0.1225 0.0290 ;
        RECT 0.2375 0.0910 0.3475 0.0770 ;
        RECT 0.2690 0.0430 0.3025 0.0290 ;
    END
  END ZN
  PIN B2
    DIRECTION INPUT ;
    USE SIGNAL ;
    PORT
      LAYER M2 ;
        RECT 0.0240 0.0430 0.1560 0.0290 ;
      LAYER M1 ;
        RECT 0.0285 0.1200 0.0435 0.0240 ;
        RECT 0.1365 0.1200 0.1515 0.0240 ;
      LAYER M0 ;
        RECT 0.0125 0.0430 0.0730 0.0290 ;
        RECT 0.1340 0.0430 0.2125 0.0290 ;
    END
  END B2
  PIN A2
    DIRECTION INPUT ;
    USE SIGNAL ;
    PORT
      LAYER M2 ;
        RECT 0.2130 0.0430 0.3720 0.0290 ;
      LAYER M1 ;
        RECT 0.2175 0.1200 0.2325 0.0240 ;
        RECT 0.3525 0.1200 0.3675 0.0240 ;
      LAYER M0 ;
        RECT 0.1880 0.0670 0.2350 0.0530 ;
        RECT 0.3500 0.0670 0.3925 0.0530 ;
    END
  END A2
  PIN B1
    DIRECTION INPUT ;
    USE SIGNAL ;
    PORT
      LAYER M0 ;
        RECT 0.0530 0.0910 0.1540 0.0770 ;
    END
  END B1
  PIN A1
    DIRECTION INPUT ;
    USE SIGNAL ;
    PORT
      LAYER M0 ;
        RECT 0.2600 0.0670 0.3430 0.0530 ;
    END
  END A1
  PIN VDD
    DIRECTION INOUT ;
    USE POWER ;
    SHAPE ABUTMENT ;
    PORT
      LAYER M0 ;
        RECT 0.0000 0.1260 0.4050 0.1620 ;
    END
  END VDD
  PIN VSS
    DIRECTION INOUT ;
    USE GROUND ;
    SHAPE ABUTMENT ;
    PORT
      LAYER M0 ;
        RECT 0.0000 -0.0180 0.4050 0.0180 ;
    END
  END VSS
  OBS
      LAYER V0 ;
        RECT 0.0290 0.0290 0.0430 0.0430 ;
        RECT 0.0830 0.0290 0.0970 0.0430 ;
        RECT 0.1370 0.0290 0.1510 0.0430 ;
        RECT 0.2450 0.0290 0.2590 0.0430 ;
        RECT 0.2720 0.0290 0.2860 0.0430 ;
        RECT 0.3260 0.0290 0.3400 0.0430 ;
        RECT 0.2180 0.0530 0.2320 0.0670 ;
        RECT 0.3530 0.0530 0.3670 0.0670 ;
        RECT 0.2720 0.0770 0.2860 0.0910 ;
      LAYER M1 ;
        RECT 0.2445 0.1200 0.2595 0.0240 ;
        RECT 0.3255 0.1200 0.3405 0.0240 ;
      LAYER V1 ;
        RECT 0.3530 0.0290 0.3670 0.0430 ;
        RECT 0.2180 0.0290 0.2320 0.0430 ;
        RECT 0.1370 0.0290 0.1510 0.0430 ;
        RECT 0.0290 0.0290 0.0430 0.0430 ;
        RECT 0.3260 0.0770 0.3400 0.0910 ;
        RECT 0.2450 0.0770 0.2590 0.0910 ;
        RECT 0.2720 0.1010 0.2860 0.1150 ;
        RECT 0.0830 0.1010 0.0970 0.1150 ;
      LAYER M0 ;
        RECT 0.0125 0.1010 0.3925 0.1150 ;
        RECT 0.0260 0.0530 0.1675 0.0670 ;
        RECT 0.2375 0.0290 0.2620 0.0430 ;
        RECT 0.3230 0.0290 0.3700 0.0430 ;
      LAYER M2 ;
        RECT 0.2400 0.0770 0.3450 0.0910 ;
  END
END AOI22_X2_6T_2F_45CPP_24M0P_27M1P_OF9_24M2P_2MPO_ET_M0

MACRO AOI21_X2_6T_2F_45CPP_24M0P_27M1P_OF9_24M2P_2MPO_ET_M0
  CLASS CORE ;
  ORIGIN 0 0 ;
  FOREIGN AOI21_X2_6T_2F_45CPP_24M0P_27M1P_OF9_24M2P_2MPO_ET_M0 0 0 ;
  SIZE 0.3150 BY 0.1440 ;
  SYMMETRY X Y ;
  SITE coresite ;
  PIN ZN
    DIRECTION OUTPUT ;
    USE SIGNAL ;
    PORT
      LAYER M1 ;
        RECT 0.0285 0.1200 0.0435 0.0240 ;
      LAYER M0 ;
        RECT 0.0260 0.1150 0.2890 0.1010 ;
        RECT 0.0125 0.0430 0.0460 0.0290 ;
    END
  END ZN
  PIN A1
    DIRECTION INPUT ;
    USE SIGNAL ;
    PORT
      LAYER M2 ;
        RECT 0.0510 0.0430 0.2100 0.0290 ;
      LAYER M1 ;
        RECT 0.0555 0.1200 0.0705 0.0240 ;
        RECT 0.1905 0.1200 0.2055 0.0240 ;
      LAYER M0 ;
        RECT 0.0260 0.0670 0.0730 0.0530 ;
        RECT 0.1610 0.0670 0.2080 0.0530 ;
    END
  END A1
  PIN A2
    DIRECTION INPUT ;
    USE SIGNAL ;
    PORT
      LAYER M0 ;
        RECT 0.0800 0.0670 0.1540 0.0530 ;
    END
  END A2
  PIN B
    DIRECTION INPUT ;
    USE SIGNAL ;
    PORT
      LAYER M0 ;
        RECT 0.2150 0.0670 0.3025 0.0530 ;
    END
  END B
  PIN VDD
    DIRECTION INOUT ;
    USE POWER ;
    SHAPE ABUTMENT ;
    PORT
      LAYER M0 ;
        RECT 0.0000 0.1260 0.3150 0.1620 ;
    END
  END VDD
  PIN VSS
    DIRECTION INOUT ;
    USE GROUND ;
    SHAPE ABUTMENT ;
    PORT
      LAYER M0 ;
        RECT 0.0000 -0.0180 0.3150 0.0180 ;
    END
  END VSS
  OBS
      LAYER V0 ;
        RECT 0.0290 0.0290 0.0430 0.0430 ;
        RECT 0.2720 0.0290 0.2860 0.0430 ;
        RECT 0.0560 0.0530 0.0700 0.0670 ;
        RECT 0.1910 0.0530 0.2050 0.0670 ;
        RECT 0.0290 0.1010 0.0430 0.1150 ;
        RECT 0.2720 0.1010 0.2860 0.1150 ;
      LAYER V1 ;
        RECT 0.1910 0.0290 0.2050 0.0430 ;
        RECT 0.0560 0.0290 0.0700 0.0430 ;
      LAYER M0 ;
        RECT 0.0125 0.0770 0.3025 0.0910 ;
        RECT 0.0575 0.0290 0.1810 0.0430 ;
        RECT 0.1880 0.0290 0.3025 0.0430 ;
      LAYER M1 ;
        RECT 0.2715 0.1200 0.2865 0.0240 ;
  END
END AOI21_X2_6T_2F_45CPP_24M0P_27M1P_OF9_24M2P_2MPO_ET_M0

MACRO OAI22_X2_6T_2F_45CPP_24M0P_27M1P_OF9_24M2P_2MPO_ET_M0
  CLASS CORE ;
  ORIGIN 0 0 ;
  FOREIGN OAI22_X2_6T_2F_45CPP_24M0P_27M1P_OF9_24M2P_2MPO_ET_M0 0 0 ;
  SIZE 0.4050 BY 0.1440 ;
  SYMMETRY X Y ;
  SITE coresite ;
  PIN A2
    DIRECTION INPUT ;
    USE SIGNAL ;
    PORT
      LAYER M2 ;
        RECT 0.2130 0.1150 0.3720 0.1010 ;
      LAYER M1 ;
        RECT 0.2175 0.1200 0.2325 0.0240 ;
        RECT 0.3525 0.1200 0.3675 0.0240 ;
      LAYER M0 ;
        RECT 0.1880 0.0910 0.2350 0.0770 ;
        RECT 0.3500 0.0910 0.3925 0.0770 ;
    END
  END A2
  PIN ZN
    DIRECTION OUTPUT ;
    USE SIGNAL ;
    PORT
      LAYER M2 ;
        RECT 0.1050 0.0670 0.2910 0.0530 ;
      LAYER M1 ;
        RECT 0.1095 0.1200 0.1245 0.0240 ;
        RECT 0.2715 0.1200 0.2865 0.0240 ;
      LAYER M0 ;
        RECT 0.0800 0.1150 0.1270 0.1010 ;
        RECT 0.2690 0.1150 0.3160 0.1010 ;
        RECT 0.2375 0.0430 0.3475 0.0290 ;
    END
  END ZN
  PIN B2
    DIRECTION INPUT ;
    USE SIGNAL ;
    PORT
      LAYER M2 ;
        RECT 0.0510 0.0910 0.2100 0.0770 ;
      LAYER M1 ;
        RECT 0.0555 0.1200 0.0705 0.0240 ;
        RECT 0.1905 0.1200 0.2055 0.0240 ;
      LAYER M0 ;
        RECT 0.0350 0.0430 0.0730 0.0290 ;
        RECT 0.1610 0.0430 0.2080 0.0290 ;
    END
  END B2
  PIN A1
    DIRECTION INPUT ;
    USE SIGNAL ;
    PORT
      LAYER M0 ;
        RECT 0.2600 0.0910 0.3430 0.0770 ;
    END
  END A1
  PIN B1
    DIRECTION INPUT ;
    USE SIGNAL ;
    PORT
      LAYER M0 ;
        RECT 0.0800 0.0430 0.1450 0.0290 ;
    END
  END B1
  PIN VDD
    DIRECTION INOUT ;
    USE POWER ;
    SHAPE ABUTMENT ;
    PORT
      LAYER M0 ;
        RECT 0.0000 0.1260 0.4050 0.1620 ;
    END
  END VDD
  PIN VSS
    DIRECTION INOUT ;
    USE GROUND ;
    SHAPE ABUTMENT ;
    PORT
      LAYER M0 ;
        RECT 0.0000 -0.0180 0.4050 0.0180 ;
    END
  END VSS
  OBS
      LAYER V0 ;
        RECT 0.0560 0.0290 0.0700 0.0430 ;
        RECT 0.1910 0.0290 0.2050 0.0430 ;
        RECT 0.2720 0.0290 0.2860 0.0430 ;
        RECT 0.2180 0.0770 0.2320 0.0910 ;
        RECT 0.3530 0.0770 0.3670 0.0910 ;
        RECT 0.1100 0.1010 0.1240 0.1150 ;
        RECT 0.2450 0.1010 0.2590 0.1150 ;
        RECT 0.2720 0.1010 0.2860 0.1150 ;
        RECT 0.3260 0.1010 0.3400 0.1150 ;
      LAYER M1 ;
        RECT 0.2445 0.1200 0.2595 0.0240 ;
        RECT 0.3255 0.1200 0.3405 0.0240 ;
      LAYER V1 ;
        RECT 0.3260 0.0290 0.3400 0.0430 ;
        RECT 0.2450 0.0290 0.2590 0.0430 ;
        RECT 0.2720 0.0530 0.2860 0.0670 ;
        RECT 0.1100 0.0530 0.1240 0.0670 ;
        RECT 0.3530 0.1010 0.3670 0.1150 ;
        RECT 0.2180 0.1010 0.2320 0.1150 ;
        RECT 0.1910 0.0770 0.2050 0.0910 ;
        RECT 0.0560 0.0770 0.0700 0.0910 ;
      LAYER M0 ;
        RECT 0.2375 0.1010 0.2620 0.1150 ;
        RECT 0.3230 0.1010 0.3475 0.1150 ;
        RECT 0.0575 0.0770 0.1675 0.0910 ;
        RECT 0.0125 0.0530 0.3925 0.0670 ;
      LAYER M2 ;
        RECT 0.2400 0.0290 0.3450 0.0430 ;
  END
END OAI22_X2_6T_2F_45CPP_24M0P_27M1P_OF9_24M2P_2MPO_ET_M0

MACRO OAI21_X2_6T_2F_45CPP_24M0P_27M1P_OF9_24M2P_2MPO_ET_M0
  CLASS CORE ;
  ORIGIN 0 0 ;
  FOREIGN OAI21_X2_6T_2F_45CPP_24M0P_27M1P_OF9_24M2P_2MPO_ET_M0 0 0 ;
  SIZE 0.3150 BY 0.1440 ;
  SYMMETRY X Y ;
  SITE coresite ;
  PIN ZN
    DIRECTION OUTPUT ;
    USE SIGNAL ;
    PORT
      LAYER M1 ;
        RECT 0.0015 0.1200 0.0165 0.0240 ;
    END
  END ZN
  PIN A1
    DIRECTION INPUT ;
    USE SIGNAL ;
    PORT
      LAYER M2 ;
        RECT 0.0240 0.0670 0.2370 0.0530 ;
      LAYER M1 ;
        RECT 0.0285 0.1200 0.0435 0.0240 ;
        RECT 0.2175 0.1200 0.2325 0.0240 ;
      LAYER M0 ;
        RECT 0.0125 0.0910 0.0550 0.0770 ;
        RECT 0.1700 0.0910 0.2350 0.0770 ;
    END
  END A1
  PIN A2
    DIRECTION INPUT ;
    USE SIGNAL ;
    PORT
      LAYER M0 ;
        RECT 0.0800 0.0910 0.1450 0.0770 ;
    END
  END A2
  PIN B
    DIRECTION INPUT ;
    USE SIGNAL ;
    PORT
      LAYER M0 ;
        RECT 0.2150 0.0430 0.3025 0.0290 ;
    END
  END B
  PIN VDD
    DIRECTION INOUT ;
    USE POWER ;
    SHAPE ABUTMENT ;
    PORT
      LAYER M0 ;
        RECT 0.0000 0.1260 0.3150 0.1620 ;
    END
  END VDD
  PIN VSS
    DIRECTION INOUT ;
    USE GROUND ;
    SHAPE ABUTMENT ;
    PORT
      LAYER M0 ;
        RECT 0.0000 -0.0180 0.3150 0.0180 ;
    END
  END VSS
  OBS
      LAYER V0 ;
        RECT 0.0020 0.0290 0.0160 0.0430 ;
        RECT 0.1910 0.0290 0.2050 0.0430 ;
        RECT 0.0290 0.0770 0.0430 0.0910 ;
        RECT 0.2180 0.0770 0.2320 0.0910 ;
        RECT 0.0020 0.1010 0.0160 0.1150 ;
        RECT 0.1910 0.1010 0.2050 0.1150 ;
      LAYER V1 ;
        RECT 0.2180 0.0530 0.2320 0.0670 ;
        RECT 0.0290 0.0530 0.0430 0.0670 ;
      LAYER M0 ;
        RECT 0.0125 0.1010 0.0325 0.1150 ;
        RECT 0.0575 0.1010 0.1675 0.1150 ;
        RECT 0.1880 0.1010 0.3025 0.1150 ;
        RECT 0.0125 0.0530 0.3025 0.0670 ;
        RECT 0.0125 0.0290 0.2080 0.0430 ;
      LAYER M1 ;
        RECT 0.1905 0.1200 0.2055 0.0240 ;
  END
END OAI21_X2_6T_2F_45CPP_24M0P_27M1P_OF9_24M2P_2MPO_ET_M0

MACRO OAI22_X1_6T_2F_45CPP_24M0P_27M1P_OF9_24M2P_2MPO_ET_M0
  CLASS CORE ;
  ORIGIN 0 0 ;
  FOREIGN OAI22_X1_6T_2F_45CPP_24M0P_27M1P_OF9_24M2P_2MPO_ET_M0 0 0 ;
  SIZE 0.2250 BY 0.1440 ;
  SYMMETRY X Y ;
  SITE coresite ;
  PIN ZN
    DIRECTION OUTPUT ;
    USE SIGNAL ;
    PORT
      LAYER M1 ;
        RECT 0.1365 0.1200 0.1515 0.0240 ;
      LAYER M0 ;
        RECT 0.1025 0.1150 0.1540 0.1010 ;
        RECT 0.1340 0.0430 0.1675 0.0290 ;
    END
  END ZN
  PIN A2
    DIRECTION INPUT ;
    USE SIGNAL ;
    PORT
      LAYER M0 ;
        RECT 0.1610 0.1150 0.2125 0.1010 ;
    END
  END A2
  PIN A1
    DIRECTION INPUT ;
    USE SIGNAL ;
    PORT
      LAYER M0 ;
        RECT 0.0125 0.0910 0.1900 0.0770 ;
    END
  END A1
  PIN B2
    DIRECTION INPUT ;
    USE SIGNAL ;
    PORT
      LAYER M0 ;
        RECT 0.0125 0.1150 0.0730 0.1010 ;
    END
  END B2
  PIN B1
    DIRECTION INPUT ;
    USE SIGNAL ;
    PORT
      LAYER M0 ;
        RECT 0.0800 0.0430 0.1270 0.0290 ;
    END
  END B1
  PIN VDD
    DIRECTION INOUT ;
    USE POWER ;
    SHAPE ABUTMENT ;
    PORT
      LAYER M0 ;
        RECT 0.0000 0.1260 0.2250 0.1620 ;
    END
  END VDD
  PIN VSS
    DIRECTION INOUT ;
    USE GROUND ;
    SHAPE ABUTMENT ;
    PORT
      LAYER M0 ;
        RECT 0.0000 -0.0180 0.2250 0.0180 ;
    END
  END VSS
  OBS
      LAYER V0 ;
        RECT 0.1370 0.0290 0.1510 0.0430 ;
        RECT 0.1370 0.1010 0.1510 0.1150 ;
      LAYER M0 ;
        RECT 0.0125 0.0530 0.2125 0.0670 ;
  END
END OAI22_X1_6T_2F_45CPP_24M0P_27M1P_OF9_24M2P_2MPO_ET_M0

MACRO AOI22_X1_6T_2F_45CPP_24M0P_27M1P_OF9_24M2P_2MPO_ET_M0
  CLASS CORE ;
  ORIGIN 0 0 ;
  FOREIGN AOI22_X1_6T_2F_45CPP_24M0P_27M1P_OF9_24M2P_2MPO_ET_M0 0 0 ;
  SIZE 0.2250 BY 0.1440 ;
  SYMMETRY X Y ;
  SITE coresite ;
  PIN ZN
    DIRECTION OUTPUT ;
    USE SIGNAL ;
    PORT
      LAYER M1 ;
        RECT 0.1095 0.1200 0.1245 0.0240 ;
      LAYER M0 ;
        RECT 0.1070 0.1150 0.1675 0.1010 ;
        RECT 0.1025 0.0430 0.1270 0.0290 ;
    END
  END ZN
  PIN B1
    DIRECTION INPUT ;
    USE SIGNAL ;
    PORT
      LAYER M0 ;
        RECT 0.0125 0.0670 0.1000 0.0530 ;
    END
  END B1
  PIN A1
    DIRECTION INPUT ;
    USE SIGNAL ;
    PORT
      LAYER M0 ;
        RECT 0.1070 0.0670 0.2125 0.0530 ;
    END
  END A1
  PIN B2
    DIRECTION INPUT ;
    USE SIGNAL ;
    PORT
      LAYER M0 ;
        RECT 0.0125 0.1150 0.0775 0.1010 ;
    END
  END B2
  PIN A2
    DIRECTION INPUT ;
    USE SIGNAL ;
    PORT
      LAYER M0 ;
        RECT 0.1340 0.0430 0.2125 0.0290 ;
    END
  END A2
  PIN VDD
    DIRECTION INOUT ;
    USE POWER ;
    SHAPE ABUTMENT ;
    PORT
      LAYER M0 ;
        RECT 0.0000 0.1260 0.2250 0.1620 ;
    END
  END VDD
  PIN VSS
    DIRECTION INOUT ;
    USE GROUND ;
    SHAPE ABUTMENT ;
    PORT
      LAYER M0 ;
        RECT 0.0000 -0.0180 0.2250 0.0180 ;
    END
  END VSS
  OBS
      LAYER V0 ;
        RECT 0.1100 0.0290 0.1240 0.0430 ;
        RECT 0.1100 0.1010 0.1240 0.1150 ;
      LAYER M0 ;
        RECT 0.0125 0.0770 0.2125 0.0910 ;
  END
END AOI22_X1_6T_2F_45CPP_24M0P_27M1P_OF9_24M2P_2MPO_ET_M0

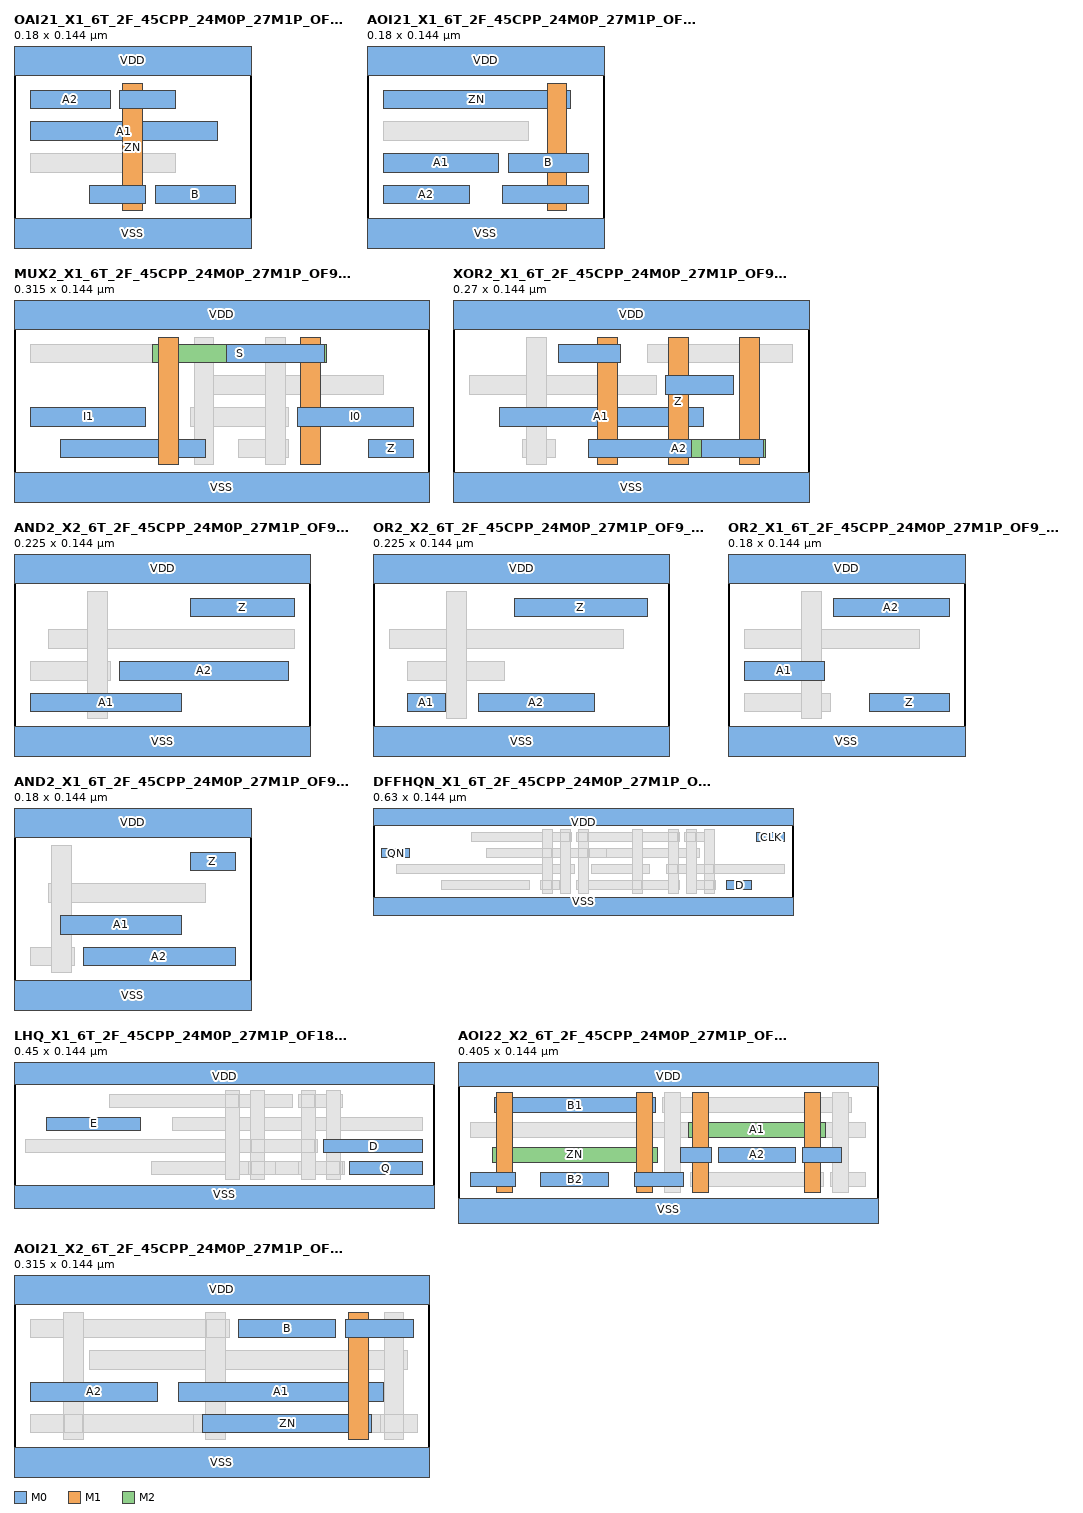
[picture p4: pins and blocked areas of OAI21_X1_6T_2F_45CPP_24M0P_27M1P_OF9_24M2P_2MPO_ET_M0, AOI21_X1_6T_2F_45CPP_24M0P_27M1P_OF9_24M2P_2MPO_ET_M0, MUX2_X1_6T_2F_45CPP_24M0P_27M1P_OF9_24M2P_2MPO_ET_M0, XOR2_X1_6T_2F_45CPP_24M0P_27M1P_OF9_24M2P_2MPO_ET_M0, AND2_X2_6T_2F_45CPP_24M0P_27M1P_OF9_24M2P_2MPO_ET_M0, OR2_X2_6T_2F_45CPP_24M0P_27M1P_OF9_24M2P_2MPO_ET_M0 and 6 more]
MACRO OAI21_X1_6T_2F_45CPP_24M0P_27M1P_OF9_24M2P_2MPO_ET_M0
  CLASS CORE ;
  ORIGIN 0 0 ;
  FOREIGN OAI21_X1_6T_2F_45CPP_24M0P_27M1P_OF9_24M2P_2MPO_ET_M0 0 0 ;
  SIZE 0.1800 BY 0.1440 ;
  SYMMETRY X Y ;
  SITE coresite ;
  PIN ZN
    DIRECTION OUTPUT ;
    USE SIGNAL ;
    PORT
      LAYER M1 ;
        RECT 0.0825 0.1200 0.0975 0.0240 ;
      LAYER M0 ;
        RECT 0.0800 0.1150 0.1225 0.1010 ;
        RECT 0.0575 0.0430 0.1000 0.0290 ;
    END
  END ZN
  PIN A2
    DIRECTION INPUT ;
    USE SIGNAL ;
    PORT
      LAYER M0 ;
        RECT 0.0125 0.1150 0.0730 0.1010 ;
    END
  END A2
  PIN A1
    DIRECTION INPUT ;
    USE SIGNAL ;
    PORT
      LAYER M0 ;
        RECT 0.0125 0.0910 0.1540 0.0770 ;
    END
  END A1
  PIN B
    DIRECTION INPUT ;
    USE SIGNAL ;
    PORT
      LAYER M0 ;
        RECT 0.1070 0.0430 0.1675 0.0290 ;
    END
  END B
  PIN VDD
    DIRECTION INOUT ;
    USE POWER ;
    SHAPE ABUTMENT ;
    PORT
      LAYER M0 ;
        RECT 0.0000 0.1260 0.1800 0.1620 ;
    END
  END VDD
  PIN VSS
    DIRECTION INOUT ;
    USE GROUND ;
    SHAPE ABUTMENT ;
    PORT
      LAYER M0 ;
        RECT 0.0000 -0.0180 0.1800 0.0180 ;
    END
  END VSS
  OBS
      LAYER V0 ;
        RECT 0.0830 0.0290 0.0970 0.0430 ;
        RECT 0.0830 0.1010 0.0970 0.1150 ;
      LAYER M0 ;
        RECT 0.0125 0.0530 0.1225 0.0670 ;
  END
END OAI21_X1_6T_2F_45CPP_24M0P_27M1P_OF9_24M2P_2MPO_ET_M0

MACRO AOI21_X1_6T_2F_45CPP_24M0P_27M1P_OF9_24M2P_2MPO_ET_M0
  CLASS CORE ;
  ORIGIN 0 0 ;
  FOREIGN AOI21_X1_6T_2F_45CPP_24M0P_27M1P_OF9_24M2P_2MPO_ET_M0 0 0 ;
  SIZE 0.1800 BY 0.1440 ;
  SYMMETRY X Y ;
  SITE coresite ;
  PIN ZN
    DIRECTION OUTPUT ;
    USE SIGNAL ;
    PORT
      LAYER M1 ;
        RECT 0.1365 0.1200 0.1515 0.0240 ;
      LAYER M0 ;
        RECT 0.0125 0.1150 0.1540 0.1010 ;
        RECT 0.1025 0.0430 0.1675 0.0290 ;
    END
  END ZN
  PIN A1
    DIRECTION INPUT ;
    USE SIGNAL ;
    PORT
      LAYER M0 ;
        RECT 0.0125 0.0670 0.1000 0.0530 ;
    END
  END A1
  PIN B
    DIRECTION INPUT ;
    USE SIGNAL ;
    PORT
      LAYER M0 ;
        RECT 0.1070 0.0670 0.1675 0.0530 ;
    END
  END B
  PIN A2
    DIRECTION INPUT ;
    USE SIGNAL ;
    PORT
      LAYER M0 ;
        RECT 0.0125 0.0430 0.0775 0.0290 ;
    END
  END A2
  PIN VDD
    DIRECTION INOUT ;
    USE POWER ;
    SHAPE ABUTMENT ;
    PORT
      LAYER M0 ;
        RECT 0.0000 0.1260 0.1800 0.1620 ;
    END
  END VDD
  PIN VSS
    DIRECTION INOUT ;
    USE GROUND ;
    SHAPE ABUTMENT ;
    PORT
      LAYER M0 ;
        RECT 0.0000 -0.0180 0.1800 0.0180 ;
    END
  END VSS
  OBS
      LAYER V0 ;
        RECT 0.1370 0.0290 0.1510 0.0430 ;
        RECT 0.1370 0.1010 0.1510 0.1150 ;
      LAYER M0 ;
        RECT 0.0125 0.0770 0.1225 0.0910 ;
  END
END AOI21_X1_6T_2F_45CPP_24M0P_27M1P_OF9_24M2P_2MPO_ET_M0

MACRO MUX2_X1_6T_2F_45CPP_24M0P_27M1P_OF9_24M2P_2MPO_ET_M0
  CLASS CORE ;
  ORIGIN 0 0 ;
  FOREIGN MUX2_X1_6T_2F_45CPP_24M0P_27M1P_OF9_24M2P_2MPO_ET_M0 0 0 ;
  SIZE 0.3150 BY 0.1440 ;
  SYMMETRY X Y ;
  SITE coresite ;
  PIN S
    DIRECTION INPUT ;
    USE SIGNAL ;
    PORT
      LAYER M2 ;
        RECT 0.1050 0.1150 0.2370 0.1010 ;
      LAYER M1 ;
        RECT 0.1095 0.1200 0.1245 0.0240 ;
        RECT 0.2175 0.1200 0.2325 0.0240 ;
      LAYER M0 ;
        RECT 0.0350 0.0430 0.1450 0.0290 ;
        RECT 0.1610 0.1150 0.2350 0.1010 ;
    END
  END S
  PIN I1
    DIRECTION INPUT ;
    USE SIGNAL ;
    PORT
      LAYER M0 ;
        RECT 0.0125 0.0670 0.1000 0.0530 ;
    END
  END I1
  PIN I0
    DIRECTION INPUT ;
    USE SIGNAL ;
    PORT
      LAYER M0 ;
        RECT 0.2150 0.0670 0.3025 0.0530 ;
    END
  END I0
  PIN Z
    DIRECTION OUTPUT ;
    USE SIGNAL ;
    PORT
      LAYER M0 ;
        RECT 0.2690 0.0430 0.3025 0.0290 ;
    END
  END Z
  PIN VDD
    DIRECTION INOUT ;
    USE POWER ;
    SHAPE ABUTMENT ;
    PORT
      LAYER M0 ;
        RECT 0.0000 0.1260 0.3150 0.1620 ;
    END
  END VDD
  PIN VSS
    DIRECTION INOUT ;
    USE GROUND ;
    SHAPE ABUTMENT ;
    PORT
      LAYER M0 ;
        RECT 0.0000 -0.0180 0.3150 0.0180 ;
    END
  END VSS
  OBS
      LAYER V0 ;
        RECT 0.1100 0.0290 0.1240 0.0430 ;
        RECT 0.1910 0.0290 0.2050 0.0430 ;
        RECT 0.1370 0.0530 0.1510 0.0670 ;
        RECT 0.1910 0.0530 0.2050 0.0670 ;
        RECT 0.1370 0.1010 0.1510 0.1150 ;
        RECT 0.2180 0.1010 0.2320 0.1150 ;
      LAYER V1 ;
        RECT 0.2180 0.1010 0.2320 0.1150 ;
        RECT 0.1100 0.1010 0.1240 0.1150 ;
      LAYER M0 ;
        RECT 0.0125 0.1010 0.1540 0.1150 ;
        RECT 0.1475 0.0770 0.2800 0.0910 ;
        RECT 0.1340 0.0530 0.2080 0.0670 ;
        RECT 0.1700 0.0290 0.2080 0.0430 ;
      LAYER M1 ;
        RECT 0.1365 0.1200 0.1515 0.0240 ;
        RECT 0.1905 0.1200 0.2055 0.0240 ;
  END
END MUX2_X1_6T_2F_45CPP_24M0P_27M1P_OF9_24M2P_2MPO_ET_M0

MACRO XOR2_X1_6T_2F_45CPP_24M0P_27M1P_OF9_24M2P_2MPO_ET_M0
  CLASS CORE ;
  ORIGIN 0 0 ;
  FOREIGN XOR2_X1_6T_2F_45CPP_24M0P_27M1P_OF9_24M2P_2MPO_ET_M0 0 0 ;
  SIZE 0.2700 BY 0.1440 ;
  SYMMETRY X Y ;
  SITE coresite ;
  PIN Z
    DIRECTION OUTPUT ;
    USE SIGNAL ;
    PORT
      LAYER M1 ;
        RECT 0.1635 0.1200 0.1785 0.0240 ;
      LAYER M0 ;
        RECT 0.1610 0.0910 0.2125 0.0770 ;
        RECT 0.1025 0.0430 0.1810 0.0290 ;
    END
  END Z
  PIN A2
    DIRECTION INPUT ;
    USE SIGNAL ;
    PORT
      LAYER M2 ;
        RECT 0.1050 0.0430 0.2370 0.0290 ;
      LAYER M1 ;
        RECT 0.1095 0.1200 0.1245 0.0240 ;
        RECT 0.2175 0.1200 0.2325 0.0240 ;
      LAYER M0 ;
        RECT 0.0800 0.1150 0.1270 0.1010 ;
        RECT 0.1880 0.0430 0.2350 0.0290 ;
    END
  END A2
  PIN A1
    DIRECTION INPUT ;
    USE SIGNAL ;
    PORT
      LAYER M0 ;
        RECT 0.0350 0.0670 0.1900 0.0530 ;
    END
  END A1
  PIN VDD
    DIRECTION INOUT ;
    USE POWER ;
    SHAPE ABUTMENT ;
    PORT
      LAYER M0 ;
        RECT 0.0000 0.1260 0.2700 0.1620 ;
    END
  END VDD
  PIN VSS
    DIRECTION INOUT ;
    USE GROUND ;
    SHAPE ABUTMENT ;
    PORT
      LAYER M0 ;
        RECT 0.0000 -0.0180 0.2700 0.0180 ;
    END
  END VSS
  OBS
      LAYER V0 ;
        RECT 0.0560 0.0290 0.0700 0.0430 ;
        RECT 0.1640 0.0290 0.1780 0.0430 ;
        RECT 0.2180 0.0290 0.2320 0.0430 ;
        RECT 0.0560 0.0770 0.0700 0.0910 ;
        RECT 0.1640 0.0770 0.1780 0.0910 ;
        RECT 0.1100 0.1010 0.1240 0.1150 ;
      LAYER V1 ;
        RECT 0.2180 0.0290 0.2320 0.0430 ;
        RECT 0.1100 0.0290 0.1240 0.0430 ;
      LAYER M0 ;
        RECT 0.1475 0.1010 0.2575 0.1150 ;
        RECT 0.0125 0.0770 0.1540 0.0910 ;
        RECT 0.0530 0.0290 0.0775 0.0430 ;
      LAYER M1 ;
        RECT 0.0555 0.1200 0.0705 0.0240 ;
  END
END XOR2_X1_6T_2F_45CPP_24M0P_27M1P_OF9_24M2P_2MPO_ET_M0

MACRO AND2_X2_6T_2F_45CPP_24M0P_27M1P_OF9_24M2P_2MPO_ET_M0
  CLASS CORE ;
  ORIGIN 0 0 ;
  FOREIGN AND2_X2_6T_2F_45CPP_24M0P_27M1P_OF9_24M2P_2MPO_ET_M0 0 0 ;
  SIZE 0.2250 BY 0.1440 ;
  SYMMETRY X Y ;
  SITE coresite ;
  PIN A2
    DIRECTION INPUT ;
    USE SIGNAL ;
    PORT
      LAYER M0 ;
        RECT 0.0800 0.0670 0.2080 0.0530 ;
    END
  END A2
  PIN A1
    DIRECTION INPUT ;
    USE SIGNAL ;
    PORT
      LAYER M0 ;
        RECT 0.0125 0.0430 0.1270 0.0290 ;
    END
  END A1
  PIN Z
    DIRECTION OUTPUT ;
    USE SIGNAL ;
    PORT
      LAYER M0 ;
        RECT 0.1340 0.1150 0.2125 0.1010 ;
    END
  END Z
  PIN VDD
    DIRECTION INOUT ;
    USE POWER ;
    SHAPE ABUTMENT ;
    PORT
      LAYER M0 ;
        RECT 0.0000 0.1260 0.2250 0.1620 ;
    END
  END VDD
  PIN VSS
    DIRECTION INOUT ;
    USE GROUND ;
    SHAPE ABUTMENT ;
    PORT
      LAYER M0 ;
        RECT 0.0000 -0.0180 0.2250 0.0180 ;
    END
  END VSS
  OBS
      LAYER V0 ;
        RECT 0.0560 0.0530 0.0700 0.0670 ;
        RECT 0.0560 0.0770 0.0700 0.0910 ;
      LAYER M0 ;
        RECT 0.0260 0.0770 0.2125 0.0910 ;
        RECT 0.0125 0.0530 0.0730 0.0670 ;
      LAYER M1 ;
        RECT 0.0555 0.1200 0.0705 0.0240 ;
  END
END AND2_X2_6T_2F_45CPP_24M0P_27M1P_OF9_24M2P_2MPO_ET_M0

MACRO OR2_X2_6T_2F_45CPP_24M0P_27M1P_OF9_24M2P_2MPO_ET_M0
  CLASS CORE ;
  ORIGIN 0 0 ;
  FOREIGN OR2_X2_6T_2F_45CPP_24M0P_27M1P_OF9_24M2P_2MPO_ET_M0 0 0 ;
  SIZE 0.2250 BY 0.1440 ;
  SYMMETRY X Y ;
  SITE coresite ;
  PIN Z
    DIRECTION OUTPUT ;
    USE SIGNAL ;
    PORT
      LAYER M0 ;
        RECT 0.1070 0.1150 0.2080 0.1010 ;
    END
  END Z
  PIN A1
    DIRECTION INPUT ;
    USE SIGNAL ;
    PORT
      LAYER M0 ;
        RECT 0.0260 0.0430 0.0550 0.0290 ;
    END
  END A1
  PIN A2
    DIRECTION INPUT ;
    USE SIGNAL ;
    PORT
      LAYER M0 ;
        RECT 0.0800 0.0430 0.1675 0.0290 ;
    END
  END A2
  PIN VDD
    DIRECTION INOUT ;
    USE POWER ;
    SHAPE ABUTMENT ;
    PORT
      LAYER M0 ;
        RECT 0.0000 0.1260 0.2250 0.1620 ;
    END
  END VDD
  PIN VSS
    DIRECTION INOUT ;
    USE GROUND ;
    SHAPE ABUTMENT ;
    PORT
      LAYER M0 ;
        RECT 0.0000 -0.0180 0.2250 0.0180 ;
    END
  END VSS
  OBS
      LAYER V0 ;
        RECT 0.0560 0.0530 0.0700 0.0670 ;
        RECT 0.0560 0.0770 0.0700 0.0910 ;
      LAYER M0 ;
        RECT 0.0125 0.0770 0.1900 0.0910 ;
        RECT 0.0260 0.0530 0.1000 0.0670 ;
      LAYER M1 ;
        RECT 0.0555 0.1200 0.0705 0.0240 ;
  END
END OR2_X2_6T_2F_45CPP_24M0P_27M1P_OF9_24M2P_2MPO_ET_M0

MACRO OR2_X1_6T_2F_45CPP_24M0P_27M1P_OF9_24M2P_2MPO_ET_M0
  CLASS CORE ;
  ORIGIN 0 0 ;
  FOREIGN OR2_X1_6T_2F_45CPP_24M0P_27M1P_OF9_24M2P_2MPO_ET_M0 0 0 ;
  SIZE 0.1800 BY 0.1440 ;
  SYMMETRY X Y ;
  SITE coresite ;
  PIN A1
    DIRECTION INPUT ;
    USE SIGNAL ;
    PORT
      LAYER M0 ;
        RECT 0.0125 0.0670 0.0730 0.0530 ;
    END
  END A1
  PIN A2
    DIRECTION INPUT ;
    USE SIGNAL ;
    PORT
      LAYER M0 ;
        RECT 0.0800 0.1150 0.1675 0.1010 ;
    END
  END A2
  PIN Z
    DIRECTION OUTPUT ;
    USE SIGNAL ;
    PORT
      LAYER M0 ;
        RECT 0.1070 0.0430 0.1675 0.0290 ;
    END
  END Z
  PIN VDD
    DIRECTION INOUT ;
    USE POWER ;
    SHAPE ABUTMENT ;
    PORT
      LAYER M0 ;
        RECT 0.0000 0.1260 0.1800 0.1620 ;
    END
  END VDD
  PIN VSS
    DIRECTION INOUT ;
    USE GROUND ;
    SHAPE ABUTMENT ;
    PORT
      LAYER M0 ;
        RECT 0.0000 -0.0180 0.1800 0.0180 ;
    END
  END VSS
  OBS
      LAYER V0 ;
        RECT 0.0560 0.0290 0.0700 0.0430 ;
        RECT 0.0560 0.0770 0.0700 0.0910 ;
      LAYER M0 ;
        RECT 0.0125 0.0770 0.1450 0.0910 ;
        RECT 0.0125 0.0290 0.0775 0.0430 ;
      LAYER M1 ;
        RECT 0.0555 0.1200 0.0705 0.0240 ;
  END
END OR2_X1_6T_2F_45CPP_24M0P_27M1P_OF9_24M2P_2MPO_ET_M0

MACRO AND2_X1_6T_2F_45CPP_24M0P_27M1P_OF9_24M2P_2MPO_ET_M0
  CLASS CORE ;
  ORIGIN 0 0 ;
  FOREIGN AND2_X1_6T_2F_45CPP_24M0P_27M1P_OF9_24M2P_2MPO_ET_M0 0 0 ;
  SIZE 0.1800 BY 0.1440 ;
  SYMMETRY X Y ;
  SITE coresite ;
  PIN A1
    DIRECTION INPUT ;
    USE SIGNAL ;
    PORT
      LAYER M0 ;
        RECT 0.0350 0.0670 0.1270 0.0530 ;
    END
  END A1
  PIN Z
    DIRECTION OUTPUT ;
    USE SIGNAL ;
    PORT
      LAYER M0 ;
        RECT 0.1340 0.1150 0.1675 0.1010 ;
    END
  END Z
  PIN A2
    DIRECTION INPUT ;
    USE SIGNAL ;
    PORT
      LAYER M0 ;
        RECT 0.0530 0.0430 0.1675 0.0290 ;
    END
  END A2
  PIN VDD
    DIRECTION INOUT ;
    USE POWER ;
    SHAPE ABUTMENT ;
    PORT
      LAYER M0 ;
        RECT 0.0000 0.1260 0.1800 0.1620 ;
    END
  END VDD
  PIN VSS
    DIRECTION INOUT ;
    USE GROUND ;
    SHAPE ABUTMENT ;
    PORT
      LAYER M0 ;
        RECT 0.0000 -0.0180 0.1800 0.0180 ;
    END
  END VSS
  OBS
      LAYER V0 ;
        RECT 0.0290 0.0290 0.0430 0.0430 ;
        RECT 0.0290 0.0770 0.0430 0.0910 ;
      LAYER M0 ;
        RECT 0.0260 0.0770 0.1450 0.0910 ;
        RECT 0.0125 0.0290 0.0460 0.0430 ;
      LAYER M1 ;
        RECT 0.0285 0.1200 0.0435 0.0240 ;
  END
END AND2_X1_6T_2F_45CPP_24M0P_27M1P_OF9_24M2P_2MPO_ET_M0

MACRO DFFHQN_X1_6T_2F_45CPP_24M0P_27M1P_OF18_24M2P_2MPO_ET_M0
  CLASS CORE ;
  ORIGIN 0 0 ;
  FOREIGN DFFHQN_X1_6T_2F_45CPP_24M0P_27M1P_OF18_24M2P_2MPO_ET_M0 0 0 ;
  SIZE 0.6300 BY 0.1440 ;
  SYMMETRY X Y ;
  SITE coresite ;
  PIN QN
    DIRECTION OUTPUT ;
    USE SIGNAL ;
    PORT
      LAYER M0 ;
        RECT 0.0125 0.0910 0.0550 0.0770 ;
    END
  END QN
  PIN D
    DIRECTION INPUT ;
    USE SIGNAL ;
    PORT
      LAYER M0 ;
        RECT 0.5300 0.0430 0.5680 0.0290 ;
    END
  END D
  PIN CLK
    DIRECTION INPUT ;
    USE SIGNAL ;
    PORT
      LAYER M0 ;
        RECT 0.5750 0.1150 0.6175 0.1010 ;
    END
  END CLK
  PIN VDD
    DIRECTION INOUT ;
    USE POWER ;
    SHAPE ABUTMENT ;
    PORT
      LAYER M0 ;
        RECT 0.0000 0.1260 0.6300 0.1620 ;
    END
  END VDD
  PIN VSS
    DIRECTION INOUT ;
    USE GROUND ;
    SHAPE ABUTMENT ;
    PORT
      LAYER M0 ;
        RECT 0.0000 -0.0180 0.6300 0.0180 ;
    END
  END VSS
  OBS
      LAYER M2 ;
        RECT 0.2760 0.0770 0.4890 0.0910 ;
      LAYER M0 ;
        RECT 0.1475 0.1010 0.2980 0.1150 ;
        RECT 0.3050 0.1010 0.4600 0.1150 ;
        RECT 0.4670 0.1010 0.5050 0.1150 ;
        RECT 0.1700 0.0770 0.3250 0.0910 ;
        RECT 0.3500 0.0770 0.4825 0.0910 ;
        RECT 0.0350 0.0530 0.3025 0.0670 ;
        RECT 0.3275 0.0530 0.4150 0.0670 ;
        RECT 0.4400 0.0530 0.6175 0.0670 ;
        RECT 0.1025 0.0290 0.2350 0.0430 ;
        RECT 0.2510 0.0290 0.2800 0.0430 ;
        RECT 0.3050 0.0290 0.4600 0.0430 ;
        RECT 0.4850 0.0290 0.5140 0.0430 ;
      LAYER V1 ;
        RECT 0.4700 0.0770 0.4840 0.0910 ;
        RECT 0.3890 0.0770 0.4030 0.0910 ;
        RECT 0.2810 0.0770 0.2950 0.0910 ;
      LAYER M1 ;
        RECT 0.2535 0.1200 0.2685 0.0240 ;
        RECT 0.2805 0.1200 0.2955 0.0240 ;
        RECT 0.3075 0.1200 0.3225 0.0240 ;
        RECT 0.3885 0.1200 0.4035 0.0240 ;
        RECT 0.4425 0.1200 0.4575 0.0240 ;
        RECT 0.4695 0.1200 0.4845 0.0240 ;
        RECT 0.4965 0.1200 0.5115 0.0240 ;
      LAYER V0 ;
        RECT 0.2540 0.0290 0.2680 0.0430 ;
        RECT 0.3890 0.0290 0.4030 0.0430 ;
        RECT 0.4970 0.0290 0.5110 0.0430 ;
        RECT 0.4430 0.0530 0.4570 0.0670 ;
        RECT 0.4970 0.0530 0.5110 0.0670 ;
        RECT 0.2540 0.0770 0.2680 0.0910 ;
        RECT 0.3080 0.0770 0.3220 0.0910 ;
        RECT 0.2810 0.1010 0.2950 0.1150 ;
        RECT 0.3080 0.1010 0.3220 0.1150 ;
        RECT 0.4430 0.1010 0.4570 0.1150 ;
        RECT 0.4700 0.1010 0.4840 0.1150 ;
  END
END DFFHQN_X1_6T_2F_45CPP_24M0P_27M1P_OF18_24M2P_2MPO_ET_M0

MACRO LHQ_X1_6T_2F_45CPP_24M0P_27M1P_OF18_24M2P_2MPO_ET_M0
  CLASS CORE ;
  ORIGIN 0 0 ;
  FOREIGN LHQ_X1_6T_2F_45CPP_24M0P_27M1P_OF18_24M2P_2MPO_ET_M0 0 0 ;
  SIZE 0.4500 BY 0.1440 ;
  SYMMETRY X Y ;
  SITE coresite ;
  PIN D
    DIRECTION INPUT ;
    USE SIGNAL ;
    PORT
      LAYER M0 ;
        RECT 0.3320 0.0670 0.4375 0.0530 ;
    END
  END D
  PIN E
    DIRECTION INPUT ;
    USE SIGNAL ;
    PORT
      LAYER M0 ;
        RECT 0.0350 0.0910 0.1360 0.0770 ;
    END
  END E
  PIN Q
    DIRECTION OUTPUT ;
    USE SIGNAL ;
    PORT
      LAYER M0 ;
        RECT 0.3590 0.0430 0.4375 0.0290 ;
    END
  END Q
  PIN VDD
    DIRECTION INOUT ;
    USE POWER ;
    SHAPE ABUTMENT ;
    PORT
      LAYER M0 ;
        RECT 0.0000 0.1260 0.4500 0.1620 ;
    END
  END VDD
  PIN VSS
    DIRECTION INOUT ;
    USE GROUND ;
    SHAPE ABUTMENT ;
    PORT
      LAYER M0 ;
        RECT 0.0000 -0.0180 0.4500 0.0180 ;
    END
  END VSS
  OBS
      LAYER M2 ;
        RECT 0.2220 0.0290 0.3540 0.0430 ;
      LAYER M0 ;
        RECT 0.1025 0.1010 0.2980 0.1150 ;
        RECT 0.3050 0.1010 0.3520 0.1150 ;
        RECT 0.1700 0.0770 0.4375 0.0910 ;
        RECT 0.0125 0.0530 0.3250 0.0670 ;
        RECT 0.1475 0.0290 0.2350 0.0430 ;
        RECT 0.2510 0.0290 0.2800 0.0430 ;
        RECT 0.3050 0.0290 0.3520 0.0430 ;
      LAYER V1 ;
        RECT 0.3350 0.0290 0.3490 0.0430 ;
        RECT 0.2270 0.0290 0.2410 0.0430 ;
      LAYER M1 ;
        RECT 0.2265 0.1200 0.2415 0.0240 ;
        RECT 0.2535 0.1200 0.2685 0.0240 ;
        RECT 0.3075 0.1200 0.3225 0.0240 ;
        RECT 0.3345 0.1200 0.3495 0.0240 ;
      LAYER V0 ;
        RECT 0.2540 0.0290 0.2680 0.0430 ;
        RECT 0.3350 0.0290 0.3490 0.0430 ;
        RECT 0.2540 0.0530 0.2680 0.0670 ;
        RECT 0.3080 0.0530 0.3220 0.0670 ;
        RECT 0.2270 0.1010 0.2410 0.1150 ;
        RECT 0.3080 0.1010 0.3220 0.1150 ;
  END
END LHQ_X1_6T_2F_45CPP_24M0P_27M1P_OF18_24M2P_2MPO_ET_M0

MACRO AOI22_X2_6T_2F_45CPP_24M0P_27M1P_OF18_24M2P_2MPO_ET_M0
  CLASS CORE ;
  ORIGIN 0 0 ;
  FOREIGN AOI22_X2_6T_2F_45CPP_24M0P_27M1P_OF18_24M2P_2MPO_ET_M0 0 0 ;
  SIZE 0.4050 BY 0.1440 ;
  SYMMETRY X Y ;
  SITE coresite ;
  PIN ZN
    DIRECTION OUTPUT ;
    USE SIGNAL ;
    PORT
      LAYER M2 ;
        RECT 0.0330 0.0670 0.1920 0.0530 ;
      LAYER M1 ;
        RECT 0.0375 0.1200 0.0525 0.0240 ;
        RECT 0.1725 0.1200 0.1875 0.0240 ;
      LAYER M0 ;
        RECT 0.0125 0.0430 0.0550 0.0290 ;
        RECT 0.1700 0.0430 0.2170 0.0290 ;
    END
  END ZN
  PIN A1
    DIRECTION INPUT ;
    USE SIGNAL ;
    PORT
      LAYER M2 ;
        RECT 0.2220 0.0910 0.3540 0.0770 ;
      LAYER M1 ;
        RECT 0.2265 0.1200 0.2415 0.0240 ;
        RECT 0.3345 0.1200 0.3495 0.0240 ;
      LAYER M0 ;
        RECT 0.2150 0.0670 0.2440 0.0530 ;
        RECT 0.3320 0.0670 0.3700 0.0530 ;
    END
  END A1
  PIN B1
    DIRECTION INPUT ;
    USE SIGNAL ;
    PORT
      LAYER M0 ;
        RECT 0.0350 0.1150 0.1900 0.1010 ;
    END
  END B1
  PIN A2
    DIRECTION INPUT ;
    USE SIGNAL ;
    PORT
      LAYER M0 ;
        RECT 0.2510 0.0670 0.3250 0.0530 ;
    END
  END A2
  PIN B2
    DIRECTION INPUT ;
    USE SIGNAL ;
    PORT
      LAYER M0 ;
        RECT 0.0800 0.0430 0.1450 0.0290 ;
    END
  END B2
  PIN VDD
    DIRECTION INOUT ;
    USE POWER ;
    SHAPE ABUTMENT ;
    PORT
      LAYER M0 ;
        RECT 0.0000 0.1260 0.4050 0.1620 ;
    END
  END VDD
  PIN VSS
    DIRECTION INOUT ;
    USE GROUND ;
    SHAPE ABUTMENT ;
    PORT
      LAYER M0 ;
        RECT 0.0000 -0.0180 0.4050 0.0180 ;
    END
  END VSS
  OBS
      LAYER V1 ;
        RECT 0.3350 0.0770 0.3490 0.0910 ;
        RECT 0.2270 0.0770 0.2410 0.0910 ;
        RECT 0.1730 0.0530 0.1870 0.0670 ;
        RECT 0.0380 0.0530 0.0520 0.0670 ;
      LAYER V0 ;
        RECT 0.0380 0.0290 0.0520 0.0430 ;
        RECT 0.1730 0.0290 0.1870 0.0430 ;
        RECT 0.2000 0.0290 0.2140 0.0430 ;
        RECT 0.3620 0.0290 0.3760 0.0430 ;
        RECT 0.2270 0.0530 0.2410 0.0670 ;
        RECT 0.3350 0.0530 0.3490 0.0670 ;
        RECT 0.2000 0.1010 0.2140 0.1150 ;
        RECT 0.3620 0.1010 0.3760 0.1150 ;
      LAYER M0 ;
        RECT 0.1970 0.1010 0.3790 0.1150 ;
        RECT 0.0125 0.0770 0.3925 0.0910 ;
        RECT 0.0350 0.0530 0.1675 0.0670 ;
        RECT 0.2240 0.0290 0.3520 0.0430 ;
        RECT 0.3590 0.0290 0.3925 0.0430 ;
      LAYER M1 ;
        RECT 0.1995 0.1200 0.2145 0.0240 ;
        RECT 0.3615 0.1200 0.3765 0.0240 ;
  END
END AOI22_X2_6T_2F_45CPP_24M0P_27M1P_OF18_24M2P_2MPO_ET_M0

MACRO AOI21_X2_6T_2F_45CPP_24M0P_27M1P_OF18_24M2P_2MPO_ET_M0
  CLASS CORE ;
  ORIGIN 0 0 ;
  FOREIGN AOI21_X2_6T_2F_45CPP_24M0P_27M1P_OF18_24M2P_2MPO_ET_M0 0 0 ;
  SIZE 0.3150 BY 0.1440 ;
  SYMMETRY X Y ;
  SITE coresite ;
  PIN ZN
    DIRECTION OUTPUT ;
    USE SIGNAL ;
    PORT
      LAYER M1 ;
        RECT 0.2535 0.1200 0.2685 0.0240 ;
      LAYER M0 ;
        RECT 0.2510 0.1150 0.3025 0.1010 ;
        RECT 0.1430 0.0430 0.2710 0.0290 ;
    END
  END ZN
  PIN B
    DIRECTION INPUT ;
    USE SIGNAL ;
    PORT
      LAYER M0 ;
        RECT 0.1700 0.1150 0.2440 0.1010 ;
    END
  END B
  PIN A2
    DIRECTION INPUT ;
    USE SIGNAL ;
    PORT
      LAYER M0 ;
        RECT 0.0125 0.0670 0.1090 0.0530 ;
    END
  END A2
  PIN A1
    DIRECTION INPUT ;
    USE SIGNAL ;
    PORT
      LAYER M0 ;
        RECT 0.1250 0.0670 0.2800 0.0530 ;
    END
  END A1
  PIN VDD
    DIRECTION INOUT ;
    USE POWER ;
    SHAPE ABUTMENT ;
    PORT
      LAYER M0 ;
        RECT 0.0000 0.1260 0.3150 0.1620 ;
    END
  END VDD
  PIN VSS
    DIRECTION INOUT ;
    USE GROUND ;
    SHAPE ABUTMENT ;
    PORT
      LAYER M0 ;
        RECT 0.0000 -0.0180 0.3150 0.0180 ;
    END
  END VSS
  OBS
      LAYER M2 ;
        RECT 0.0330 0.0290 0.3000 0.0430 ;
      LAYER M0 ;
        RECT 0.0125 0.1010 0.1630 0.1150 ;
        RECT 0.0575 0.0770 0.2980 0.0910 ;
        RECT 0.0125 0.0290 0.1360 0.0430 ;
        RECT 0.2780 0.0290 0.3055 0.0430 ;
      LAYER V1 ;
        RECT 0.2810 0.0290 0.2950 0.0430 ;
        RECT 0.0380 0.0290 0.0520 0.0430 ;
      LAYER M1 ;
        RECT 0.0375 0.1200 0.0525 0.0240 ;
        RECT 0.1455 0.1200 0.1605 0.0240 ;
        RECT 0.2805 0.1200 0.2955 0.0240 ;
      LAYER V0 ;
        RECT 0.0380 0.0290 0.0520 0.0430 ;
        RECT 0.1460 0.0290 0.1600 0.0430 ;
        RECT 0.2540 0.0290 0.2680 0.0430 ;
        RECT 0.2810 0.0290 0.2950 0.0430 ;
        RECT 0.1460 0.1010 0.1600 0.1150 ;
        RECT 0.2540 0.1010 0.2680 0.1150 ;
  END
END AOI21_X2_6T_2F_45CPP_24M0P_27M1P_OF18_24M2P_2MPO_ET_M0

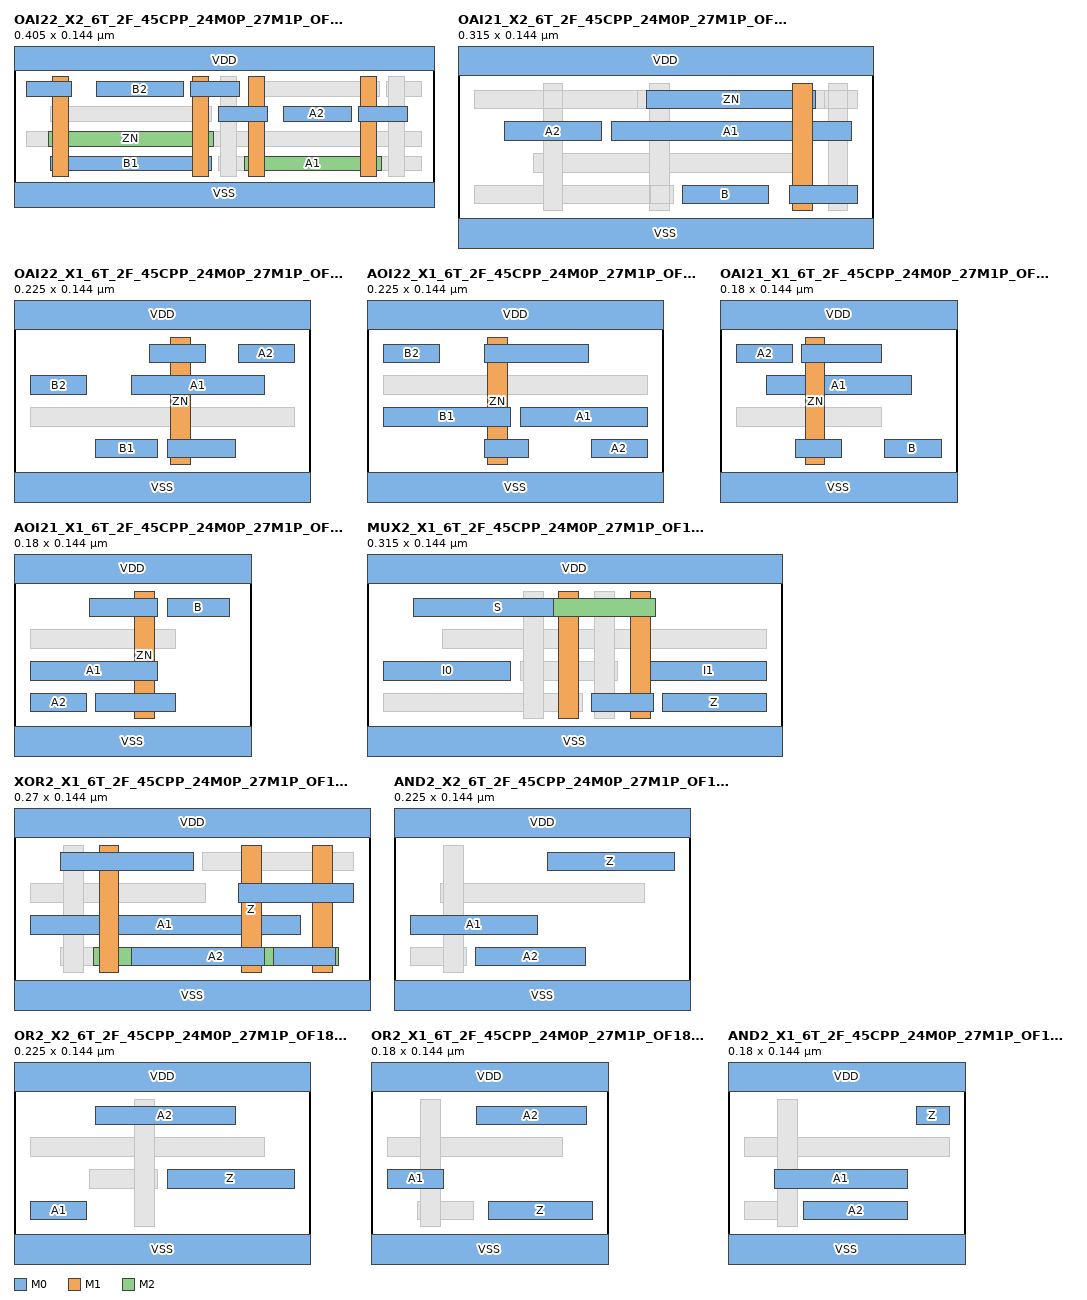
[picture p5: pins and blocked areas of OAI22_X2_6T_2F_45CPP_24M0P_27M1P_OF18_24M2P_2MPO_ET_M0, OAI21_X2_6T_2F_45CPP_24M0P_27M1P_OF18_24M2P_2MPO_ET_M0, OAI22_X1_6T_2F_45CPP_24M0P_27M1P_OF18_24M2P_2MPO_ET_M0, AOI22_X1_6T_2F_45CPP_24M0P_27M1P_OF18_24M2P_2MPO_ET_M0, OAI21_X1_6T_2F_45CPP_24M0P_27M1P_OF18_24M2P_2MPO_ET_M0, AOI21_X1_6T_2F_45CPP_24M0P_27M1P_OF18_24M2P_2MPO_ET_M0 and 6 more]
MACRO OAI22_X2_6T_2F_45CPP_24M0P_27M1P_OF18_24M2P_2MPO_ET_M0
  CLASS CORE ;
  ORIGIN 0 0 ;
  FOREIGN OAI22_X2_6T_2F_45CPP_24M0P_27M1P_OF18_24M2P_2MPO_ET_M0 0 0 ;
  SIZE 0.4050 BY 0.1440 ;
  SYMMETRY X Y ;
  SITE coresite ;
  PIN ZN
    DIRECTION OUTPUT ;
    USE SIGNAL ;
    PORT
      LAYER M2 ;
        RECT 0.0330 0.0670 0.1920 0.0530 ;
      LAYER M1 ;
        RECT 0.0375 0.1200 0.0525 0.0240 ;
        RECT 0.1725 0.1200 0.1875 0.0240 ;
      LAYER M0 ;
        RECT 0.0125 0.1150 0.0550 0.1010 ;
        RECT 0.1700 0.1150 0.2170 0.1010 ;
    END
  END ZN
  PIN A1
    DIRECTION INPUT ;
    USE SIGNAL ;
    PORT
      LAYER M2 ;
        RECT 0.2220 0.0430 0.3540 0.0290 ;
      LAYER M1 ;
        RECT 0.2265 0.1200 0.2415 0.0240 ;
        RECT 0.3345 0.1200 0.3495 0.0240 ;
      LAYER M0 ;
        RECT 0.1970 0.0910 0.2440 0.0770 ;
        RECT 0.3320 0.0910 0.3790 0.0770 ;
    END
  END A1
  PIN B2
    DIRECTION INPUT ;
    USE SIGNAL ;
    PORT
      LAYER M0 ;
        RECT 0.0800 0.1150 0.1630 0.1010 ;
    END
  END B2
  PIN A2
    DIRECTION INPUT ;
    USE SIGNAL ;
    PORT
      LAYER M0 ;
        RECT 0.2600 0.0910 0.3250 0.0770 ;
    END
  END A2
  PIN B1
    DIRECTION INPUT ;
    USE SIGNAL ;
    PORT
      LAYER M0 ;
        RECT 0.0350 0.0430 0.1900 0.0290 ;
    END
  END B1
  PIN VDD
    DIRECTION INOUT ;
    USE POWER ;
    SHAPE ABUTMENT ;
    PORT
      LAYER M0 ;
        RECT 0.0000 0.1260 0.4050 0.1620 ;
    END
  END VDD
  PIN VSS
    DIRECTION INOUT ;
    USE GROUND ;
    SHAPE ABUTMENT ;
    PORT
      LAYER M0 ;
        RECT 0.0000 -0.0180 0.4050 0.0180 ;
    END
  END VSS
  OBS
      LAYER V1 ;
        RECT 0.3350 0.0290 0.3490 0.0430 ;
        RECT 0.2270 0.0290 0.2410 0.0430 ;
        RECT 0.1730 0.0530 0.1870 0.0670 ;
        RECT 0.0380 0.0530 0.0520 0.0670 ;
      LAYER V0 ;
        RECT 0.2000 0.0290 0.2140 0.0430 ;
        RECT 0.3620 0.0290 0.3760 0.0430 ;
        RECT 0.2270 0.0770 0.2410 0.0910 ;
        RECT 0.3350 0.0770 0.3490 0.0910 ;
        RECT 0.0380 0.1010 0.0520 0.1150 ;
        RECT 0.1730 0.1010 0.1870 0.1150 ;
        RECT 0.2000 0.1010 0.2140 0.1150 ;
        RECT 0.3620 0.1010 0.3760 0.1150 ;
      LAYER M0 ;
        RECT 0.2375 0.1010 0.3520 0.1150 ;
        RECT 0.3590 0.1010 0.3925 0.1150 ;
        RECT 0.0350 0.0770 0.1900 0.0910 ;
        RECT 0.0125 0.0530 0.3925 0.0670 ;
        RECT 0.1970 0.0290 0.3925 0.0430 ;
      LAYER M1 ;
        RECT 0.1995 0.1200 0.2145 0.0240 ;
        RECT 0.3615 0.1200 0.3765 0.0240 ;
  END
END OAI22_X2_6T_2F_45CPP_24M0P_27M1P_OF18_24M2P_2MPO_ET_M0

MACRO OAI21_X2_6T_2F_45CPP_24M0P_27M1P_OF18_24M2P_2MPO_ET_M0
  CLASS CORE ;
  ORIGIN 0 0 ;
  FOREIGN OAI21_X2_6T_2F_45CPP_24M0P_27M1P_OF18_24M2P_2MPO_ET_M0 0 0 ;
  SIZE 0.3150 BY 0.1440 ;
  SYMMETRY X Y ;
  SITE coresite ;
  PIN ZN
    DIRECTION OUTPUT ;
    USE SIGNAL ;
    PORT
      LAYER M1 ;
        RECT 0.2535 0.1200 0.2685 0.0240 ;
      LAYER M0 ;
        RECT 0.1430 0.1150 0.2710 0.1010 ;
        RECT 0.2510 0.0430 0.3025 0.0290 ;
    END
  END ZN
  PIN A2
    DIRECTION INPUT ;
    USE SIGNAL ;
    PORT
      LAYER M0 ;
        RECT 0.0350 0.0910 0.1090 0.0770 ;
    END
  END A2
  PIN A1
    DIRECTION INPUT ;
    USE SIGNAL ;
    PORT
      LAYER M0 ;
        RECT 0.1160 0.0910 0.2980 0.0770 ;
    END
  END A1
  PIN B
    DIRECTION INPUT ;
    USE SIGNAL ;
    PORT
      LAYER M0 ;
        RECT 0.1700 0.0430 0.2350 0.0290 ;
    END
  END B
  PIN VDD
    DIRECTION INOUT ;
    USE POWER ;
    SHAPE ABUTMENT ;
    PORT
      LAYER M0 ;
        RECT 0.0000 0.1260 0.3150 0.1620 ;
    END
  END VDD
  PIN VSS
    DIRECTION INOUT ;
    USE GROUND ;
    SHAPE ABUTMENT ;
    PORT
      LAYER M0 ;
        RECT 0.0000 -0.0180 0.3150 0.0180 ;
    END
  END VSS
  OBS
      LAYER M2 ;
        RECT 0.0600 0.1010 0.3000 0.1150 ;
      LAYER M0 ;
        RECT 0.0125 0.1010 0.1360 0.1150 ;
        RECT 0.2780 0.1010 0.3025 0.1150 ;
        RECT 0.0575 0.0530 0.2575 0.0670 ;
        RECT 0.0125 0.0290 0.1630 0.0430 ;
      LAYER V1 ;
        RECT 0.2810 0.1010 0.2950 0.1150 ;
        RECT 0.0650 0.1010 0.0790 0.1150 ;
      LAYER M1 ;
        RECT 0.0645 0.1200 0.0795 0.0240 ;
        RECT 0.1455 0.1200 0.1605 0.0240 ;
        RECT 0.2805 0.1200 0.2955 0.0240 ;
      LAYER V0 ;
        RECT 0.1460 0.0290 0.1600 0.0430 ;
        RECT 0.2540 0.0290 0.2680 0.0430 ;
        RECT 0.0650 0.1010 0.0790 0.1150 ;
        RECT 0.1460 0.1010 0.1600 0.1150 ;
        RECT 0.2540 0.1010 0.2680 0.1150 ;
        RECT 0.2810 0.1010 0.2950 0.1150 ;
  END
END OAI21_X2_6T_2F_45CPP_24M0P_27M1P_OF18_24M2P_2MPO_ET_M0

MACRO OAI22_X1_6T_2F_45CPP_24M0P_27M1P_OF18_24M2P_2MPO_ET_M0
  CLASS CORE ;
  ORIGIN 0 0 ;
  FOREIGN OAI22_X1_6T_2F_45CPP_24M0P_27M1P_OF18_24M2P_2MPO_ET_M0 0 0 ;
  SIZE 0.2250 BY 0.1440 ;
  SYMMETRY X Y ;
  SITE coresite ;
  PIN ZN
    DIRECTION OUTPUT ;
    USE SIGNAL ;
    PORT
      LAYER M1 ;
        RECT 0.1185 0.1200 0.1335 0.0240 ;
      LAYER M0 ;
        RECT 0.1025 0.1150 0.1450 0.1010 ;
        RECT 0.1160 0.0430 0.1675 0.0290 ;
    END
  END ZN
  PIN A2
    DIRECTION INPUT ;
    USE SIGNAL ;
    PORT
      LAYER M0 ;
        RECT 0.1700 0.1150 0.2125 0.1010 ;
    END
  END A2
  PIN A1
    DIRECTION INPUT ;
    USE SIGNAL ;
    PORT
      LAYER M0 ;
        RECT 0.0890 0.0910 0.1900 0.0770 ;
    END
  END A1
  PIN B2
    DIRECTION INPUT ;
    USE SIGNAL ;
    PORT
      LAYER M0 ;
        RECT 0.0125 0.0910 0.0550 0.0770 ;
    END
  END B2
  PIN B1
    DIRECTION INPUT ;
    USE SIGNAL ;
    PORT
      LAYER M0 ;
        RECT 0.0620 0.0430 0.1090 0.0290 ;
    END
  END B1
  PIN VDD
    DIRECTION INOUT ;
    USE POWER ;
    SHAPE ABUTMENT ;
    PORT
      LAYER M0 ;
        RECT 0.0000 0.1260 0.2250 0.1620 ;
    END
  END VDD
  PIN VSS
    DIRECTION INOUT ;
    USE GROUND ;
    SHAPE ABUTMENT ;
    PORT
      LAYER M0 ;
        RECT 0.0000 -0.0180 0.2250 0.0180 ;
    END
  END VSS
  OBS
      LAYER V0 ;
        RECT 0.1190 0.0290 0.1330 0.0430 ;
        RECT 0.1190 0.1010 0.1330 0.1150 ;
      LAYER M0 ;
        RECT 0.0125 0.0530 0.2125 0.0670 ;
  END
END OAI22_X1_6T_2F_45CPP_24M0P_27M1P_OF18_24M2P_2MPO_ET_M0

MACRO AOI22_X1_6T_2F_45CPP_24M0P_27M1P_OF18_24M2P_2MPO_ET_M0
  CLASS CORE ;
  ORIGIN 0 0 ;
  FOREIGN AOI22_X1_6T_2F_45CPP_24M0P_27M1P_OF18_24M2P_2MPO_ET_M0 0 0 ;
  SIZE 0.2250 BY 0.1440 ;
  SYMMETRY X Y ;
  SITE coresite ;
  PIN ZN
    DIRECTION OUTPUT ;
    USE SIGNAL ;
    PORT
      LAYER M1 ;
        RECT 0.0915 0.1200 0.1065 0.0240 ;
      LAYER M0 ;
        RECT 0.0890 0.1150 0.1675 0.1010 ;
        RECT 0.0890 0.0430 0.1225 0.0290 ;
    END
  END ZN
  PIN B1
    DIRECTION INPUT ;
    USE SIGNAL ;
    PORT
      LAYER M0 ;
        RECT 0.0125 0.0670 0.1090 0.0530 ;
    END
  END B1
  PIN A1
    DIRECTION INPUT ;
    USE SIGNAL ;
    PORT
      LAYER M0 ;
        RECT 0.1160 0.0670 0.2125 0.0530 ;
    END
  END A1
  PIN B2
    DIRECTION INPUT ;
    USE SIGNAL ;
    PORT
      LAYER M0 ;
        RECT 0.0125 0.1150 0.0550 0.1010 ;
    END
  END B2
  PIN A2
    DIRECTION INPUT ;
    USE SIGNAL ;
    PORT
      LAYER M0 ;
        RECT 0.1700 0.0430 0.2125 0.0290 ;
    END
  END A2
  PIN VDD
    DIRECTION INOUT ;
    USE POWER ;
    SHAPE ABUTMENT ;
    PORT
      LAYER M0 ;
        RECT 0.0000 0.1260 0.2250 0.1620 ;
    END
  END VDD
  PIN VSS
    DIRECTION INOUT ;
    USE GROUND ;
    SHAPE ABUTMENT ;
    PORT
      LAYER M0 ;
        RECT 0.0000 -0.0180 0.2250 0.0180 ;
    END
  END VSS
  OBS
      LAYER V0 ;
        RECT 0.0920 0.0290 0.1060 0.0430 ;
        RECT 0.0920 0.1010 0.1060 0.1150 ;
      LAYER M0 ;
        RECT 0.0125 0.0770 0.2125 0.0910 ;
  END
END AOI22_X1_6T_2F_45CPP_24M0P_27M1P_OF18_24M2P_2MPO_ET_M0

MACRO OAI21_X1_6T_2F_45CPP_24M0P_27M1P_OF18_24M2P_2MPO_ET_M0
  CLASS CORE ;
  ORIGIN 0 0 ;
  FOREIGN OAI21_X1_6T_2F_45CPP_24M0P_27M1P_OF18_24M2P_2MPO_ET_M0 0 0 ;
  SIZE 0.1800 BY 0.1440 ;
  SYMMETRY X Y ;
  SITE coresite ;
  PIN ZN
    DIRECTION OUTPUT ;
    USE SIGNAL ;
    PORT
      LAYER M1 ;
        RECT 0.0645 0.1200 0.0795 0.0240 ;
      LAYER M0 ;
        RECT 0.0620 0.1150 0.1225 0.1010 ;
        RECT 0.0575 0.0430 0.0920 0.0290 ;
    END
  END ZN
  PIN A2
    DIRECTION INPUT ;
    USE SIGNAL ;
    PORT
      LAYER M0 ;
        RECT 0.0125 0.1150 0.0550 0.1010 ;
    END
  END A2
  PIN A1
    DIRECTION INPUT ;
    USE SIGNAL ;
    PORT
      LAYER M0 ;
        RECT 0.0350 0.0910 0.1450 0.0770 ;
    END
  END A1
  PIN B
    DIRECTION INPUT ;
    USE SIGNAL ;
    PORT
      LAYER M0 ;
        RECT 0.1250 0.0430 0.1675 0.0290 ;
    END
  END B
  PIN VDD
    DIRECTION INOUT ;
    USE POWER ;
    SHAPE ABUTMENT ;
    PORT
      LAYER M0 ;
        RECT 0.0000 0.1260 0.1800 0.1620 ;
    END
  END VDD
  PIN VSS
    DIRECTION INOUT ;
    USE GROUND ;
    SHAPE ABUTMENT ;
    PORT
      LAYER M0 ;
        RECT 0.0000 -0.0180 0.1800 0.0180 ;
    END
  END VSS
  OBS
      LAYER V0 ;
        RECT 0.0650 0.0290 0.0790 0.0430 ;
        RECT 0.0650 0.1010 0.0790 0.1150 ;
      LAYER M0 ;
        RECT 0.0125 0.0530 0.1225 0.0670 ;
  END
END OAI21_X1_6T_2F_45CPP_24M0P_27M1P_OF18_24M2P_2MPO_ET_M0

MACRO AOI21_X1_6T_2F_45CPP_24M0P_27M1P_OF18_24M2P_2MPO_ET_M0
  CLASS CORE ;
  ORIGIN 0 0 ;
  FOREIGN AOI21_X1_6T_2F_45CPP_24M0P_27M1P_OF18_24M2P_2MPO_ET_M0 0 0 ;
  SIZE 0.1800 BY 0.1440 ;
  SYMMETRY X Y ;
  SITE coresite ;
  PIN ZN
    DIRECTION OUTPUT ;
    USE SIGNAL ;
    PORT
      LAYER M1 ;
        RECT 0.0915 0.1200 0.1065 0.0240 ;
      LAYER M0 ;
        RECT 0.0575 0.1150 0.1090 0.1010 ;
        RECT 0.0620 0.0430 0.1225 0.0290 ;
    END
  END ZN
  PIN A1
    DIRECTION INPUT ;
    USE SIGNAL ;
    PORT
      LAYER M0 ;
        RECT 0.0125 0.0670 0.1090 0.0530 ;
    END
  END A1
  PIN B
    DIRECTION INPUT ;
    USE SIGNAL ;
    PORT
      LAYER M0 ;
        RECT 0.1160 0.1150 0.1630 0.1010 ;
    END
  END B
  PIN A2
    DIRECTION INPUT ;
    USE SIGNAL ;
    PORT
      LAYER M0 ;
        RECT 0.0125 0.0430 0.0550 0.0290 ;
    END
  END A2
  PIN VDD
    DIRECTION INOUT ;
    USE POWER ;
    SHAPE ABUTMENT ;
    PORT
      LAYER M0 ;
        RECT 0.0000 0.1260 0.1800 0.1620 ;
    END
  END VDD
  PIN VSS
    DIRECTION INOUT ;
    USE GROUND ;
    SHAPE ABUTMENT ;
    PORT
      LAYER M0 ;
        RECT 0.0000 -0.0180 0.1800 0.0180 ;
    END
  END VSS
  OBS
      LAYER V0 ;
        RECT 0.0920 0.0290 0.1060 0.0430 ;
        RECT 0.0920 0.1010 0.1060 0.1150 ;
      LAYER M0 ;
        RECT 0.0125 0.0770 0.1225 0.0910 ;
  END
END AOI21_X1_6T_2F_45CPP_24M0P_27M1P_OF18_24M2P_2MPO_ET_M0

MACRO MUX2_X1_6T_2F_45CPP_24M0P_27M1P_OF18_24M2P_2MPO_ET_M0
  CLASS CORE ;
  ORIGIN 0 0 ;
  FOREIGN MUX2_X1_6T_2F_45CPP_24M0P_27M1P_OF18_24M2P_2MPO_ET_M0 0 0 ;
  SIZE 0.3150 BY 0.1440 ;
  SYMMETRY X Y ;
  SITE coresite ;
  PIN S
    DIRECTION INPUT ;
    USE SIGNAL ;
    PORT
      LAYER M2 ;
        RECT 0.1410 0.1150 0.2190 0.1010 ;
      LAYER M1 ;
        RECT 0.1455 0.1200 0.1605 0.0240 ;
        RECT 0.1995 0.1200 0.2145 0.0240 ;
      LAYER M0 ;
        RECT 0.0350 0.1150 0.1630 0.1010 ;
        RECT 0.1700 0.0430 0.2170 0.0290 ;
    END
  END S
  PIN I0
    DIRECTION INPUT ;
    USE SIGNAL ;
    PORT
      LAYER M0 ;
        RECT 0.0125 0.0670 0.1090 0.0530 ;
    END
  END I0
  PIN I1
    DIRECTION INPUT ;
    USE SIGNAL ;
    PORT
      LAYER M0 ;
        RECT 0.2150 0.0670 0.3025 0.0530 ;
    END
  END I1
  PIN Z
    DIRECTION OUTPUT ;
    USE SIGNAL ;
    PORT
      LAYER M0 ;
        RECT 0.2240 0.0430 0.3025 0.0290 ;
    END
  END Z
  PIN VDD
    DIRECTION INOUT ;
    USE POWER ;
    SHAPE ABUTMENT ;
    PORT
      LAYER M0 ;
        RECT 0.0000 0.1260 0.3150 0.1620 ;
    END
  END VDD
  PIN VSS
    DIRECTION INOUT ;
    USE GROUND ;
    SHAPE ABUTMENT ;
    PORT
      LAYER M0 ;
        RECT 0.0000 -0.0180 0.3150 0.0180 ;
    END
  END VSS
  OBS
      LAYER V1 ;
        RECT 0.2000 0.1010 0.2140 0.1150 ;
        RECT 0.1460 0.1010 0.1600 0.1150 ;
      LAYER V0 ;
        RECT 0.1190 0.0290 0.1330 0.0430 ;
        RECT 0.2000 0.0290 0.2140 0.0430 ;
        RECT 0.1190 0.0530 0.1330 0.0670 ;
        RECT 0.1730 0.0530 0.1870 0.0670 ;
        RECT 0.1460 0.1010 0.1600 0.1150 ;
        RECT 0.1730 0.1010 0.1870 0.1150 ;
      LAYER M0 ;
        RECT 0.1700 0.1010 0.2125 0.1150 ;
        RECT 0.0575 0.0770 0.3025 0.0910 ;
        RECT 0.1160 0.0530 0.1900 0.0670 ;
        RECT 0.0125 0.0290 0.1630 0.0430 ;
      LAYER M1 ;
        RECT 0.1185 0.1200 0.1335 0.0240 ;
        RECT 0.1725 0.1200 0.1875 0.0240 ;
  END
END MUX2_X1_6T_2F_45CPP_24M0P_27M1P_OF18_24M2P_2MPO_ET_M0

MACRO XOR2_X1_6T_2F_45CPP_24M0P_27M1P_OF18_24M2P_2MPO_ET_M0
  CLASS CORE ;
  ORIGIN 0 0 ;
  FOREIGN XOR2_X1_6T_2F_45CPP_24M0P_27M1P_OF18_24M2P_2MPO_ET_M0 0 0 ;
  SIZE 0.2700 BY 0.1440 ;
  SYMMETRY X Y ;
  SITE coresite ;
  PIN Z
    DIRECTION OUTPUT ;
    USE SIGNAL ;
    PORT
      LAYER M1 ;
        RECT 0.1725 0.1200 0.1875 0.0240 ;
      LAYER M0 ;
        RECT 0.1700 0.0910 0.2575 0.0770 ;
        RECT 0.0890 0.0430 0.1900 0.0290 ;
    END
  END Z
  PIN A2
    DIRECTION INPUT ;
    USE SIGNAL ;
    PORT
      LAYER M2 ;
        RECT 0.0600 0.0430 0.2460 0.0290 ;
      LAYER M1 ;
        RECT 0.0645 0.1200 0.0795 0.0240 ;
        RECT 0.2265 0.1200 0.2415 0.0240 ;
      LAYER M0 ;
        RECT 0.0350 0.1150 0.1360 0.1010 ;
        RECT 0.1970 0.0430 0.2440 0.0290 ;
    END
  END A2
  PIN A1
    DIRECTION INPUT ;
    USE SIGNAL ;
    PORT
      LAYER M0 ;
        RECT 0.0125 0.0670 0.2170 0.0530 ;
    END
  END A1
  PIN VDD
    DIRECTION INOUT ;
    USE POWER ;
    SHAPE ABUTMENT ;
    PORT
      LAYER M0 ;
        RECT 0.0000 0.1260 0.2700 0.1620 ;
    END
  END VDD
  PIN VSS
    DIRECTION INOUT ;
    USE GROUND ;
    SHAPE ABUTMENT ;
    PORT
      LAYER M0 ;
        RECT 0.0000 -0.0180 0.2700 0.0180 ;
    END
  END VSS
  OBS
      LAYER V1 ;
        RECT 0.2270 0.0290 0.2410 0.0430 ;
        RECT 0.0650 0.0290 0.0790 0.0430 ;
      LAYER V0 ;
        RECT 0.0380 0.0290 0.0520 0.0430 ;
        RECT 0.1730 0.0290 0.1870 0.0430 ;
        RECT 0.2270 0.0290 0.2410 0.0430 ;
        RECT 0.0380 0.0770 0.0520 0.0910 ;
        RECT 0.1730 0.0770 0.1870 0.0910 ;
        RECT 0.0650 0.1010 0.0790 0.1150 ;
      LAYER M0 ;
        RECT 0.1430 0.1010 0.2575 0.1150 ;
        RECT 0.0125 0.0770 0.1450 0.0910 ;
        RECT 0.0350 0.0290 0.0775 0.0430 ;
      LAYER M1 ;
        RECT 0.0375 0.1200 0.0525 0.0240 ;
  END
END XOR2_X1_6T_2F_45CPP_24M0P_27M1P_OF18_24M2P_2MPO_ET_M0

MACRO AND2_X2_6T_2F_45CPP_24M0P_27M1P_OF18_24M2P_2MPO_ET_M0
  CLASS CORE ;
  ORIGIN 0 0 ;
  FOREIGN AND2_X2_6T_2F_45CPP_24M0P_27M1P_OF18_24M2P_2MPO_ET_M0 0 0 ;
  SIZE 0.2250 BY 0.1440 ;
  SYMMETRY X Y ;
  SITE coresite ;
  PIN A1
    DIRECTION INPUT ;
    USE SIGNAL ;
    PORT
      LAYER M0 ;
        RECT 0.0125 0.0670 0.1090 0.0530 ;
    END
  END A1
  PIN Z
    DIRECTION OUTPUT ;
    USE SIGNAL ;
    PORT
      LAYER M0 ;
        RECT 0.1160 0.1150 0.2125 0.1010 ;
    END
  END Z
  PIN A2
    DIRECTION INPUT ;
    USE SIGNAL ;
    PORT
      LAYER M0 ;
        RECT 0.0620 0.0430 0.1450 0.0290 ;
    END
  END A2
  PIN VDD
    DIRECTION INOUT ;
    USE POWER ;
    SHAPE ABUTMENT ;
    PORT
      LAYER M0 ;
        RECT 0.0000 0.1260 0.2250 0.1620 ;
    END
  END VDD
  PIN VSS
    DIRECTION INOUT ;
    USE GROUND ;
    SHAPE ABUTMENT ;
    PORT
      LAYER M0 ;
        RECT 0.0000 -0.0180 0.2250 0.0180 ;
    END
  END VSS
  OBS
      LAYER V0 ;
        RECT 0.0380 0.0290 0.0520 0.0430 ;
        RECT 0.0380 0.0770 0.0520 0.0910 ;
      LAYER M0 ;
        RECT 0.0350 0.0770 0.1900 0.0910 ;
        RECT 0.0125 0.0290 0.0550 0.0430 ;
      LAYER M1 ;
        RECT 0.0375 0.1200 0.0525 0.0240 ;
  END
END AND2_X2_6T_2F_45CPP_24M0P_27M1P_OF18_24M2P_2MPO_ET_M0

MACRO OR2_X2_6T_2F_45CPP_24M0P_27M1P_OF18_24M2P_2MPO_ET_M0
  CLASS CORE ;
  ORIGIN 0 0 ;
  FOREIGN OR2_X2_6T_2F_45CPP_24M0P_27M1P_OF18_24M2P_2MPO_ET_M0 0 0 ;
  SIZE 0.2250 BY 0.1440 ;
  SYMMETRY X Y ;
  SITE coresite ;
  PIN Z
    DIRECTION OUTPUT ;
    USE SIGNAL ;
    PORT
      LAYER M0 ;
        RECT 0.1160 0.0670 0.2125 0.0530 ;
    END
  END Z
  PIN A1
    DIRECTION INPUT ;
    USE SIGNAL ;
    PORT
      LAYER M0 ;
        RECT 0.0125 0.0430 0.0550 0.0290 ;
    END
  END A1
  PIN A2
    DIRECTION INPUT ;
    USE SIGNAL ;
    PORT
      LAYER M0 ;
        RECT 0.0620 0.1150 0.1675 0.1010 ;
    END
  END A2
  PIN VDD
    DIRECTION INOUT ;
    USE POWER ;
    SHAPE ABUTMENT ;
    PORT
      LAYER M0 ;
        RECT 0.0000 0.1260 0.2250 0.1620 ;
    END
  END VDD
  PIN VSS
    DIRECTION INOUT ;
    USE GROUND ;
    SHAPE ABUTMENT ;
    PORT
      LAYER M0 ;
        RECT 0.0000 -0.0180 0.2250 0.0180 ;
    END
  END VSS
  OBS
      LAYER V0 ;
        RECT 0.0920 0.0530 0.1060 0.0670 ;
        RECT 0.0920 0.0770 0.1060 0.0910 ;
      LAYER M0 ;
        RECT 0.0125 0.0770 0.1900 0.0910 ;
        RECT 0.0575 0.0530 0.1090 0.0670 ;
      LAYER M1 ;
        RECT 0.0915 0.1200 0.1065 0.0240 ;
  END
END OR2_X2_6T_2F_45CPP_24M0P_27M1P_OF18_24M2P_2MPO_ET_M0

MACRO OR2_X1_6T_2F_45CPP_24M0P_27M1P_OF18_24M2P_2MPO_ET_M0
  CLASS CORE ;
  ORIGIN 0 0 ;
  FOREIGN OR2_X1_6T_2F_45CPP_24M0P_27M1P_OF18_24M2P_2MPO_ET_M0 0 0 ;
  SIZE 0.1800 BY 0.1440 ;
  SYMMETRY X Y ;
  SITE coresite ;
  PIN A1
    DIRECTION INPUT ;
    USE SIGNAL ;
    PORT
      LAYER M0 ;
        RECT 0.0125 0.0670 0.0550 0.0530 ;
    END
  END A1
  PIN A2
    DIRECTION INPUT ;
    USE SIGNAL ;
    PORT
      LAYER M0 ;
        RECT 0.0800 0.1150 0.1630 0.1010 ;
    END
  END A2
  PIN Z
    DIRECTION OUTPUT ;
    USE SIGNAL ;
    PORT
      LAYER M0 ;
        RECT 0.0890 0.0430 0.1675 0.0290 ;
    END
  END Z
  PIN VDD
    DIRECTION INOUT ;
    USE POWER ;
    SHAPE ABUTMENT ;
    PORT
      LAYER M0 ;
        RECT 0.0000 0.1260 0.1800 0.1620 ;
    END
  END VDD
  PIN VSS
    DIRECTION INOUT ;
    USE GROUND ;
    SHAPE ABUTMENT ;
    PORT
      LAYER M0 ;
        RECT 0.0000 -0.0180 0.1800 0.0180 ;
    END
  END VSS
  OBS
      LAYER V0 ;
        RECT 0.0380 0.0290 0.0520 0.0430 ;
        RECT 0.0380 0.0770 0.0520 0.0910 ;
      LAYER M0 ;
        RECT 0.0125 0.0770 0.1450 0.0910 ;
        RECT 0.0350 0.0290 0.0775 0.0430 ;
      LAYER M1 ;
        RECT 0.0375 0.1200 0.0525 0.0240 ;
  END
END OR2_X1_6T_2F_45CPP_24M0P_27M1P_OF18_24M2P_2MPO_ET_M0

MACRO AND2_X1_6T_2F_45CPP_24M0P_27M1P_OF18_24M2P_2MPO_ET_M0
  CLASS CORE ;
  ORIGIN 0 0 ;
  FOREIGN AND2_X1_6T_2F_45CPP_24M0P_27M1P_OF18_24M2P_2MPO_ET_M0 0 0 ;
  SIZE 0.1800 BY 0.1440 ;
  SYMMETRY X Y ;
  SITE coresite ;
  PIN A1
    DIRECTION INPUT ;
    USE SIGNAL ;
    PORT
      LAYER M0 ;
        RECT 0.0350 0.0670 0.1360 0.0530 ;
    END
  END A1
  PIN A2
    DIRECTION INPUT ;
    USE SIGNAL ;
    PORT
      LAYER M0 ;
        RECT 0.0575 0.0430 0.1360 0.0290 ;
    END
  END A2
  PIN Z
    DIRECTION OUTPUT ;
    USE SIGNAL ;
    PORT
      LAYER M0 ;
        RECT 0.1430 0.1150 0.1675 0.1010 ;
    END
  END Z
  PIN VDD
    DIRECTION INOUT ;
    USE POWER ;
    SHAPE ABUTMENT ;
    PORT
      LAYER M0 ;
        RECT 0.0000 0.1260 0.1800 0.1620 ;
    END
  END VDD
  PIN VSS
    DIRECTION INOUT ;
    USE GROUND ;
    SHAPE ABUTMENT ;
    PORT
      LAYER M0 ;
        RECT 0.0000 -0.0180 0.1800 0.0180 ;
    END
  END VSS
  OBS
      LAYER V0 ;
        RECT 0.0380 0.0770 0.0520 0.0910 ;
        RECT 0.0380 0.0290 0.0520 0.0430 ;
      LAYER M0 ;
        RECT 0.0125 0.0770 0.1675 0.0910 ;
        RECT 0.0125 0.0290 0.0400 0.0430 ;
      LAYER M1 ;
        RECT 0.0375 0.1200 0.0525 0.0240 ;
  END
END AND2_X1_6T_2F_45CPP_24M0P_27M1P_OF18_24M2P_2MPO_ET_M0

